VERSION 5.8 ;
BUSBITCHARS "[]" ;
DIVIDERCHAR "/" ;
UNITS
    DATABASE MICRONS 1000 ;
END UNITS

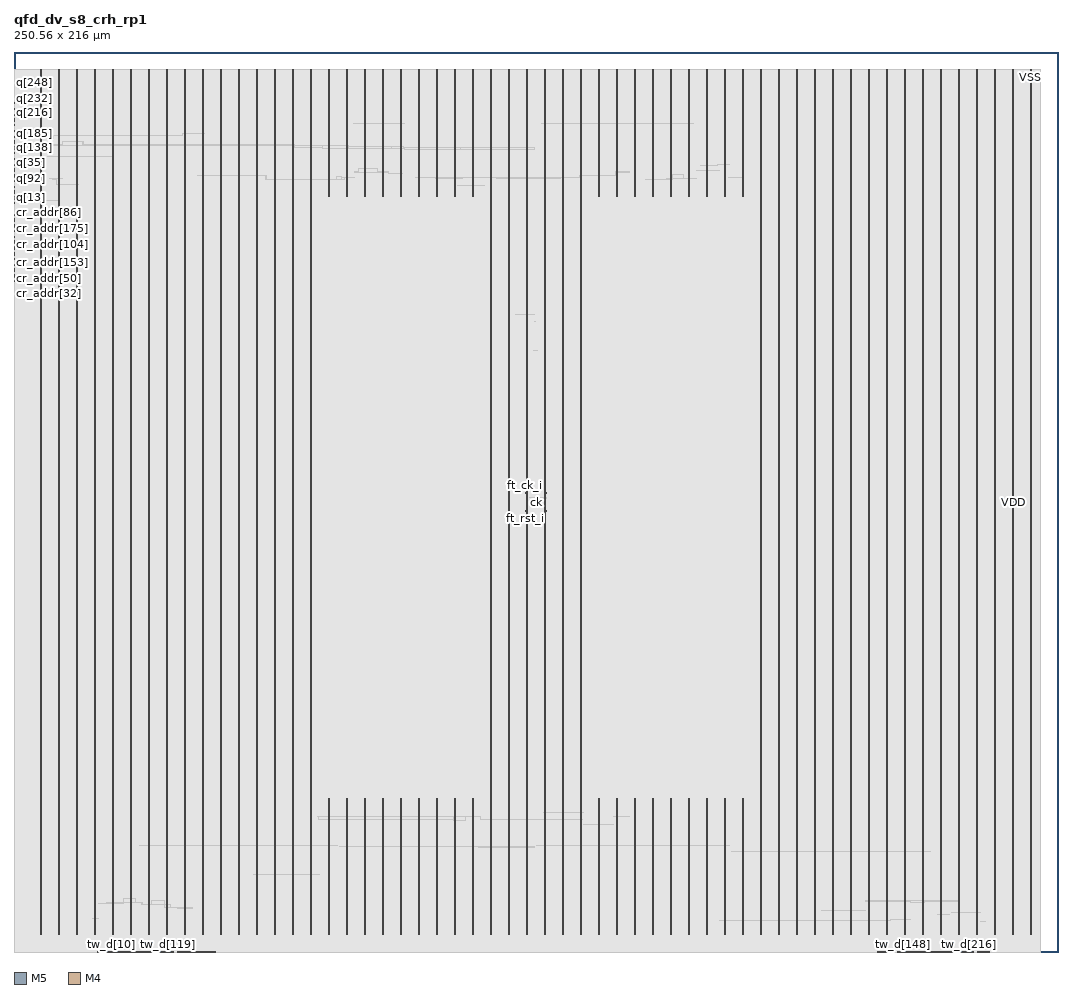
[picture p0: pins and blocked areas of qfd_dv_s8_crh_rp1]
MACRO qfd_dv_s8_crh_rp1
  FOREIGN qfd_dv_s8_crh_rp1 0 0 ;
  CLASS BLOCK ;
  SIZE 250.56 BY 216 ;
  PIN ck
    DIRECTION INPUT ;
    USE SIGNAL ;
    PORT
      LAYER M5 ;
        RECT  125.28 107.808 125.304 108.192 ;
    END
  END ck
  PIN cr_addr[0]
    DIRECTION INPUT ;
    USE SIGNAL ;
    PORT
      LAYER M4 ;
        RECT  0 166.032 0.084 166.056 ;
    END
  END cr_addr[0]
  PIN cr_addr[100]
    DIRECTION INPUT ;
    USE SIGNAL ;
    PORT
      LAYER M4 ;
        RECT  0 169.488 0.084 169.512 ;
    END
  END cr_addr[100]
  PIN cr_addr[101]
    DIRECTION INPUT ;
    USE SIGNAL ;
    PORT
      LAYER M4 ;
        RECT  0 169.584 0.084 169.608 ;
    END
  END cr_addr[101]
  PIN cr_addr[102]
    DIRECTION INPUT ;
    USE SIGNAL ;
    PORT
      LAYER M4 ;
        RECT  0 169.68 0.084 169.704 ;
    END
  END cr_addr[102]
  PIN cr_addr[103]
    DIRECTION INPUT ;
    USE SIGNAL ;
    PORT
      LAYER M4 ;
        RECT  0 169.776 0.084 169.8 ;
    END
  END cr_addr[103]
  PIN cr_addr[104]
    DIRECTION INPUT ;
    USE SIGNAL ;
    PORT
      LAYER M4 ;
        RECT  0 169.872 0.084 169.896 ;
    END
  END cr_addr[104]
  PIN cr_addr[105]
    DIRECTION INPUT ;
    USE SIGNAL ;
    PORT
      LAYER M4 ;
        RECT  0 169.968 0.084 169.992 ;
    END
  END cr_addr[105]
  PIN cr_addr[106]
    DIRECTION INPUT ;
    USE SIGNAL ;
    PORT
      LAYER M4 ;
        RECT  0 170.064 0.084 170.088 ;
    END
  END cr_addr[106]
  PIN cr_addr[107]
    DIRECTION INPUT ;
    USE SIGNAL ;
    PORT
      LAYER M4 ;
        RECT  0 170.16 0.084 170.184 ;
    END
  END cr_addr[107]
  PIN cr_addr[108]
    DIRECTION INPUT ;
    USE SIGNAL ;
    PORT
      LAYER M4 ;
        RECT  0 170.256 0.084 170.28 ;
    END
  END cr_addr[108]
  PIN cr_addr[109]
    DIRECTION INPUT ;
    USE SIGNAL ;
    PORT
      LAYER M4 ;
        RECT  0 170.352 0.084 170.376 ;
    END
  END cr_addr[109]
  PIN cr_addr[10]
    DIRECTION INPUT ;
    USE SIGNAL ;
    PORT
      LAYER M4 ;
        RECT  0 166.992 0.084 167.016 ;
    END
  END cr_addr[10]
  PIN cr_addr[110]
    DIRECTION INPUT ;
    USE SIGNAL ;
    PORT
      LAYER M4 ;
        RECT  0 170.448 0.084 170.472 ;
    END
  END cr_addr[110]
  PIN cr_addr[111]
    DIRECTION INPUT ;
    USE SIGNAL ;
    PORT
      LAYER M4 ;
        RECT  0 170.544 0.084 170.568 ;
    END
  END cr_addr[111]
  PIN cr_addr[112]
    DIRECTION INPUT ;
    USE SIGNAL ;
    PORT
      LAYER M4 ;
        RECT  0 170.64 0.084 170.664 ;
    END
  END cr_addr[112]
  PIN cr_addr[113]
    DIRECTION INPUT ;
    USE SIGNAL ;
    PORT
      LAYER M4 ;
        RECT  0 170.736 0.084 170.76 ;
    END
  END cr_addr[113]
  PIN cr_addr[114]
    DIRECTION INPUT ;
    USE SIGNAL ;
    PORT
      LAYER M4 ;
        RECT  0 170.832 0.084 170.856 ;
    END
  END cr_addr[114]
  PIN cr_addr[115]
    DIRECTION INPUT ;
    USE SIGNAL ;
    PORT
      LAYER M4 ;
        RECT  0 170.928 0.084 170.952 ;
    END
  END cr_addr[115]
  PIN cr_addr[116]
    DIRECTION INPUT ;
    USE SIGNAL ;
    PORT
      LAYER M4 ;
        RECT  0 171.024 0.084 171.048 ;
    END
  END cr_addr[116]
  PIN cr_addr[117]
    DIRECTION INPUT ;
    USE SIGNAL ;
    PORT
      LAYER M4 ;
        RECT  0 171.12 0.084 171.144 ;
    END
  END cr_addr[117]
  PIN cr_addr[118]
    DIRECTION INPUT ;
    USE SIGNAL ;
    PORT
      LAYER M4 ;
        RECT  0 171.216 0.084 171.24 ;
    END
  END cr_addr[118]
  PIN cr_addr[119]
    DIRECTION INPUT ;
    USE SIGNAL ;
    PORT
      LAYER M4 ;
        RECT  0 171.312 0.084 171.336 ;
    END
  END cr_addr[119]
  PIN cr_addr[11]
    DIRECTION INPUT ;
    USE SIGNAL ;
    PORT
      LAYER M4 ;
        RECT  0 167.088 0.084 167.112 ;
    END
  END cr_addr[11]
  PIN cr_addr[120]
    DIRECTION INPUT ;
    USE SIGNAL ;
    PORT
      LAYER M4 ;
        RECT  0 171.408 0.084 171.432 ;
    END
  END cr_addr[120]
  PIN cr_addr[121]
    DIRECTION INPUT ;
    USE SIGNAL ;
    PORT
      LAYER M4 ;
        RECT  0 171.504 0.084 171.528 ;
    END
  END cr_addr[121]
  PIN cr_addr[122]
    DIRECTION INPUT ;
    USE SIGNAL ;
    PORT
      LAYER M4 ;
        RECT  0 171.6 0.084 171.624 ;
    END
  END cr_addr[122]
  PIN cr_addr[123]
    DIRECTION INPUT ;
    USE SIGNAL ;
    PORT
      LAYER M4 ;
        RECT  0 171.696 0.084 171.72 ;
    END
  END cr_addr[123]
  PIN cr_addr[124]
    DIRECTION INPUT ;
    USE SIGNAL ;
    PORT
      LAYER M4 ;
        RECT  0 171.792 0.084 171.816 ;
    END
  END cr_addr[124]
  PIN cr_addr[125]
    DIRECTION INPUT ;
    USE SIGNAL ;
    PORT
      LAYER M4 ;
        RECT  0 171.888 0.084 171.912 ;
    END
  END cr_addr[125]
  PIN cr_addr[126]
    DIRECTION INPUT ;
    USE SIGNAL ;
    PORT
      LAYER M4 ;
        RECT  0 171.984 0.084 172.008 ;
    END
  END cr_addr[126]
  PIN cr_addr[127]
    DIRECTION INPUT ;
    USE SIGNAL ;
    PORT
      LAYER M4 ;
        RECT  0 172.08 0.084 172.104 ;
    END
  END cr_addr[127]
  PIN cr_addr[128]
    DIRECTION INPUT ;
    USE SIGNAL ;
    PORT
      LAYER M4 ;
        RECT  0 162.96 0.084 162.984 ;
    END
  END cr_addr[128]
  PIN cr_addr[129]
    DIRECTION INPUT ;
    USE SIGNAL ;
    PORT
      LAYER M4 ;
        RECT  0 163.056 0.084 163.08 ;
    END
  END cr_addr[129]
  PIN cr_addr[12]
    DIRECTION INPUT ;
    USE SIGNAL ;
    PORT
      LAYER M4 ;
        RECT  0 167.184 0.084 167.208 ;
    END
  END cr_addr[12]
  PIN cr_addr[130]
    DIRECTION INPUT ;
    USE SIGNAL ;
    PORT
      LAYER M4 ;
        RECT  0 163.152 0.084 163.176 ;
    END
  END cr_addr[130]
  PIN cr_addr[131]
    DIRECTION INPUT ;
    USE SIGNAL ;
    PORT
      LAYER M4 ;
        RECT  0 163.248 0.084 163.272 ;
    END
  END cr_addr[131]
  PIN cr_addr[132]
    DIRECTION INPUT ;
    USE SIGNAL ;
    PORT
      LAYER M4 ;
        RECT  0 163.344 0.084 163.368 ;
    END
  END cr_addr[132]
  PIN cr_addr[133]
    DIRECTION INPUT ;
    USE SIGNAL ;
    PORT
      LAYER M4 ;
        RECT  0 163.44 0.084 163.464 ;
    END
  END cr_addr[133]
  PIN cr_addr[134]
    DIRECTION INPUT ;
    USE SIGNAL ;
    PORT
      LAYER M4 ;
        RECT  0 163.536 0.084 163.56 ;
    END
  END cr_addr[134]
  PIN cr_addr[135]
    DIRECTION INPUT ;
    USE SIGNAL ;
    PORT
      LAYER M4 ;
        RECT  0 163.632 0.084 163.656 ;
    END
  END cr_addr[135]
  PIN cr_addr[136]
    DIRECTION INPUT ;
    USE SIGNAL ;
    PORT
      LAYER M4 ;
        RECT  0 163.728 0.084 163.752 ;
    END
  END cr_addr[136]
  PIN cr_addr[137]
    DIRECTION INPUT ;
    USE SIGNAL ;
    PORT
      LAYER M4 ;
        RECT  0 163.824 0.084 163.848 ;
    END
  END cr_addr[137]
  PIN cr_addr[138]
    DIRECTION INPUT ;
    USE SIGNAL ;
    PORT
      LAYER M4 ;
        RECT  0 163.92 0.084 163.944 ;
    END
  END cr_addr[138]
  PIN cr_addr[139]
    DIRECTION INPUT ;
    USE SIGNAL ;
    PORT
      LAYER M4 ;
        RECT  0 164.016 0.084 164.04 ;
    END
  END cr_addr[139]
  PIN cr_addr[13]
    DIRECTION INPUT ;
    USE SIGNAL ;
    PORT
      LAYER M4 ;
        RECT  0 167.28 0.084 167.304 ;
    END
  END cr_addr[13]
  PIN cr_addr[140]
    DIRECTION INPUT ;
    USE SIGNAL ;
    PORT
      LAYER M4 ;
        RECT  0 164.112 0.084 164.136 ;
    END
  END cr_addr[140]
  PIN cr_addr[141]
    DIRECTION INPUT ;
    USE SIGNAL ;
    PORT
      LAYER M4 ;
        RECT  0 164.208 0.084 164.232 ;
    END
  END cr_addr[141]
  PIN cr_addr[142]
    DIRECTION INPUT ;
    USE SIGNAL ;
    PORT
      LAYER M4 ;
        RECT  0 164.304 0.084 164.328 ;
    END
  END cr_addr[142]
  PIN cr_addr[143]
    DIRECTION INPUT ;
    USE SIGNAL ;
    PORT
      LAYER M4 ;
        RECT  0 164.4 0.084 164.424 ;
    END
  END cr_addr[143]
  PIN cr_addr[144]
    DIRECTION INPUT ;
    USE SIGNAL ;
    PORT
      LAYER M4 ;
        RECT  0 164.496 0.084 164.52 ;
    END
  END cr_addr[144]
  PIN cr_addr[145]
    DIRECTION INPUT ;
    USE SIGNAL ;
    PORT
      LAYER M4 ;
        RECT  0 164.592 0.084 164.616 ;
    END
  END cr_addr[145]
  PIN cr_addr[146]
    DIRECTION INPUT ;
    USE SIGNAL ;
    PORT
      LAYER M4 ;
        RECT  0 164.688 0.084 164.712 ;
    END
  END cr_addr[146]
  PIN cr_addr[147]
    DIRECTION INPUT ;
    USE SIGNAL ;
    PORT
      LAYER M4 ;
        RECT  0 164.784 0.084 164.808 ;
    END
  END cr_addr[147]
  PIN cr_addr[148]
    DIRECTION INPUT ;
    USE SIGNAL ;
    PORT
      LAYER M4 ;
        RECT  0 164.88 0.084 164.904 ;
    END
  END cr_addr[148]
  PIN cr_addr[149]
    DIRECTION INPUT ;
    USE SIGNAL ;
    PORT
      LAYER M4 ;
        RECT  0 164.976 0.084 165 ;
    END
  END cr_addr[149]
  PIN cr_addr[14]
    DIRECTION INPUT ;
    USE SIGNAL ;
    PORT
      LAYER M4 ;
        RECT  0 167.376 0.084 167.4 ;
    END
  END cr_addr[14]
  PIN cr_addr[150]
    DIRECTION INPUT ;
    USE SIGNAL ;
    PORT
      LAYER M4 ;
        RECT  0 165.072 0.084 165.096 ;
    END
  END cr_addr[150]
  PIN cr_addr[151]
    DIRECTION INPUT ;
    USE SIGNAL ;
    PORT
      LAYER M4 ;
        RECT  0 165.168 0.084 165.192 ;
    END
  END cr_addr[151]
  PIN cr_addr[152]
    DIRECTION INPUT ;
    USE SIGNAL ;
    PORT
      LAYER M4 ;
        RECT  0 165.264 0.084 165.288 ;
    END
  END cr_addr[152]
  PIN cr_addr[153]
    DIRECTION INPUT ;
    USE SIGNAL ;
    PORT
      LAYER M4 ;
        RECT  0 165.36 0.084 165.384 ;
    END
  END cr_addr[153]
  PIN cr_addr[154]
    DIRECTION INPUT ;
    USE SIGNAL ;
    PORT
      LAYER M4 ;
        RECT  0 165.456 0.084 165.48 ;
    END
  END cr_addr[154]
  PIN cr_addr[155]
    DIRECTION INPUT ;
    USE SIGNAL ;
    PORT
      LAYER M4 ;
        RECT  0 165.552 0.084 165.576 ;
    END
  END cr_addr[155]
  PIN cr_addr[156]
    DIRECTION INPUT ;
    USE SIGNAL ;
    PORT
      LAYER M4 ;
        RECT  0 165.648 0.084 165.672 ;
    END
  END cr_addr[156]
  PIN cr_addr[157]
    DIRECTION INPUT ;
    USE SIGNAL ;
    PORT
      LAYER M4 ;
        RECT  0 165.744 0.084 165.768 ;
    END
  END cr_addr[157]
  PIN cr_addr[158]
    DIRECTION INPUT ;
    USE SIGNAL ;
    PORT
      LAYER M4 ;
        RECT  0 165.84 0.084 165.864 ;
    END
  END cr_addr[158]
  PIN cr_addr[159]
    DIRECTION INPUT ;
    USE SIGNAL ;
    PORT
      LAYER M4 ;
        RECT  0 165.936 0.084 165.96 ;
    END
  END cr_addr[159]
  PIN cr_addr[15]
    DIRECTION INPUT ;
    USE SIGNAL ;
    PORT
      LAYER M4 ;
        RECT  0 167.472 0.084 167.496 ;
    END
  END cr_addr[15]
  PIN cr_addr[160]
    DIRECTION INPUT ;
    USE SIGNAL ;
    PORT
      LAYER M4 ;
        RECT  0 172.176 0.084 172.2 ;
    END
  END cr_addr[160]
  PIN cr_addr[161]
    DIRECTION INPUT ;
    USE SIGNAL ;
    PORT
      LAYER M4 ;
        RECT  0 172.272 0.084 172.296 ;
    END
  END cr_addr[161]
  PIN cr_addr[162]
    DIRECTION INPUT ;
    USE SIGNAL ;
    PORT
      LAYER M4 ;
        RECT  0 172.368 0.084 172.392 ;
    END
  END cr_addr[162]
  PIN cr_addr[163]
    DIRECTION INPUT ;
    USE SIGNAL ;
    PORT
      LAYER M4 ;
        RECT  0 172.464 0.084 172.488 ;
    END
  END cr_addr[163]
  PIN cr_addr[164]
    DIRECTION INPUT ;
    USE SIGNAL ;
    PORT
      LAYER M4 ;
        RECT  0 172.56 0.084 172.584 ;
    END
  END cr_addr[164]
  PIN cr_addr[165]
    DIRECTION INPUT ;
    USE SIGNAL ;
    PORT
      LAYER M4 ;
        RECT  0 172.656 0.084 172.68 ;
    END
  END cr_addr[165]
  PIN cr_addr[166]
    DIRECTION INPUT ;
    USE SIGNAL ;
    PORT
      LAYER M4 ;
        RECT  0 172.752 0.084 172.776 ;
    END
  END cr_addr[166]
  PIN cr_addr[167]
    DIRECTION INPUT ;
    USE SIGNAL ;
    PORT
      LAYER M4 ;
        RECT  0 172.848 0.084 172.872 ;
    END
  END cr_addr[167]
  PIN cr_addr[168]
    DIRECTION INPUT ;
    USE SIGNAL ;
    PORT
      LAYER M4 ;
        RECT  0 172.944 0.084 172.968 ;
    END
  END cr_addr[168]
  PIN cr_addr[169]
    DIRECTION INPUT ;
    USE SIGNAL ;
    PORT
      LAYER M4 ;
        RECT  0 173.04 0.084 173.064 ;
    END
  END cr_addr[169]
  PIN cr_addr[16]
    DIRECTION INPUT ;
    USE SIGNAL ;
    PORT
      LAYER M4 ;
        RECT  0 167.568 0.084 167.592 ;
    END
  END cr_addr[16]
  PIN cr_addr[170]
    DIRECTION INPUT ;
    USE SIGNAL ;
    PORT
      LAYER M4 ;
        RECT  0 173.136 0.084 173.16 ;
    END
  END cr_addr[170]
  PIN cr_addr[171]
    DIRECTION INPUT ;
    USE SIGNAL ;
    PORT
      LAYER M4 ;
        RECT  0 173.232 0.084 173.256 ;
    END
  END cr_addr[171]
  PIN cr_addr[172]
    DIRECTION INPUT ;
    USE SIGNAL ;
    PORT
      LAYER M4 ;
        RECT  0 173.328 0.084 173.352 ;
    END
  END cr_addr[172]
  PIN cr_addr[173]
    DIRECTION INPUT ;
    USE SIGNAL ;
    PORT
      LAYER M4 ;
        RECT  0 173.424 0.084 173.448 ;
    END
  END cr_addr[173]
  PIN cr_addr[174]
    DIRECTION INPUT ;
    USE SIGNAL ;
    PORT
      LAYER M4 ;
        RECT  0 173.52 0.084 173.544 ;
    END
  END cr_addr[174]
  PIN cr_addr[175]
    DIRECTION INPUT ;
    USE SIGNAL ;
    PORT
      LAYER M4 ;
        RECT  0 173.616 0.084 173.64 ;
    END
  END cr_addr[175]
  PIN cr_addr[176]
    DIRECTION INPUT ;
    USE SIGNAL ;
    PORT
      LAYER M4 ;
        RECT  0 173.712 0.084 173.736 ;
    END
  END cr_addr[176]
  PIN cr_addr[177]
    DIRECTION INPUT ;
    USE SIGNAL ;
    PORT
      LAYER M4 ;
        RECT  0 173.808 0.084 173.832 ;
    END
  END cr_addr[177]
  PIN cr_addr[178]
    DIRECTION INPUT ;
    USE SIGNAL ;
    PORT
      LAYER M4 ;
        RECT  0 173.904 0.084 173.928 ;
    END
  END cr_addr[178]
  PIN cr_addr[179]
    DIRECTION INPUT ;
    USE SIGNAL ;
    PORT
      LAYER M4 ;
        RECT  0 174 0.084 174.024 ;
    END
  END cr_addr[179]
  PIN cr_addr[17]
    DIRECTION INPUT ;
    USE SIGNAL ;
    PORT
      LAYER M4 ;
        RECT  0 167.664 0.084 167.688 ;
    END
  END cr_addr[17]
  PIN cr_addr[180]
    DIRECTION INPUT ;
    USE SIGNAL ;
    PORT
      LAYER M4 ;
        RECT  0 174.096 0.084 174.12 ;
    END
  END cr_addr[180]
  PIN cr_addr[181]
    DIRECTION INPUT ;
    USE SIGNAL ;
    PORT
      LAYER M4 ;
        RECT  0 174.192 0.084 174.216 ;
    END
  END cr_addr[181]
  PIN cr_addr[182]
    DIRECTION INPUT ;
    USE SIGNAL ;
    PORT
      LAYER M4 ;
        RECT  0 174.288 0.084 174.312 ;
    END
  END cr_addr[182]
  PIN cr_addr[183]
    DIRECTION INPUT ;
    USE SIGNAL ;
    PORT
      LAYER M4 ;
        RECT  0 174.384 0.084 174.408 ;
    END
  END cr_addr[183]
  PIN cr_addr[184]
    DIRECTION INPUT ;
    USE SIGNAL ;
    PORT
      LAYER M4 ;
        RECT  0 174.48 0.084 174.504 ;
    END
  END cr_addr[184]
  PIN cr_addr[185]
    DIRECTION INPUT ;
    USE SIGNAL ;
    PORT
      LAYER M4 ;
        RECT  0 174.576 0.084 174.6 ;
    END
  END cr_addr[185]
  PIN cr_addr[186]
    DIRECTION INPUT ;
    USE SIGNAL ;
    PORT
      LAYER M4 ;
        RECT  0 174.672 0.084 174.696 ;
    END
  END cr_addr[186]
  PIN cr_addr[187]
    DIRECTION INPUT ;
    USE SIGNAL ;
    PORT
      LAYER M4 ;
        RECT  0 174.768 0.084 174.792 ;
    END
  END cr_addr[187]
  PIN cr_addr[188]
    DIRECTION INPUT ;
    USE SIGNAL ;
    PORT
      LAYER M4 ;
        RECT  0 174.864 0.084 174.888 ;
    END
  END cr_addr[188]
  PIN cr_addr[189]
    DIRECTION INPUT ;
    USE SIGNAL ;
    PORT
      LAYER M4 ;
        RECT  0 174.96 0.084 174.984 ;
    END
  END cr_addr[189]
  PIN cr_addr[18]
    DIRECTION INPUT ;
    USE SIGNAL ;
    PORT
      LAYER M4 ;
        RECT  0 167.76 0.084 167.784 ;
    END
  END cr_addr[18]
  PIN cr_addr[190]
    DIRECTION INPUT ;
    USE SIGNAL ;
    PORT
      LAYER M4 ;
        RECT  0 175.056 0.084 175.08 ;
    END
  END cr_addr[190]
  PIN cr_addr[191]
    DIRECTION INPUT ;
    USE SIGNAL ;
    PORT
      LAYER M4 ;
        RECT  0 175.152 0.084 175.176 ;
    END
  END cr_addr[191]
  PIN cr_addr[19]
    DIRECTION INPUT ;
    USE SIGNAL ;
    PORT
      LAYER M4 ;
        RECT  0 167.856 0.084 167.88 ;
    END
  END cr_addr[19]
  PIN cr_addr[1]
    DIRECTION INPUT ;
    USE SIGNAL ;
    PORT
      LAYER M4 ;
        RECT  0 166.128 0.084 166.152 ;
    END
  END cr_addr[1]
  PIN cr_addr[20]
    DIRECTION INPUT ;
    USE SIGNAL ;
    PORT
      LAYER M4 ;
        RECT  0 167.952 0.084 167.976 ;
    END
  END cr_addr[20]
  PIN cr_addr[21]
    DIRECTION INPUT ;
    USE SIGNAL ;
    PORT
      LAYER M4 ;
        RECT  0 168.048 0.084 168.072 ;
    END
  END cr_addr[21]
  PIN cr_addr[22]
    DIRECTION INPUT ;
    USE SIGNAL ;
    PORT
      LAYER M4 ;
        RECT  0 168.144 0.084 168.168 ;
    END
  END cr_addr[22]
  PIN cr_addr[23]
    DIRECTION INPUT ;
    USE SIGNAL ;
    PORT
      LAYER M4 ;
        RECT  0 168.24 0.084 168.264 ;
    END
  END cr_addr[23]
  PIN cr_addr[24]
    DIRECTION INPUT ;
    USE SIGNAL ;
    PORT
      LAYER M4 ;
        RECT  0 168.336 0.084 168.36 ;
    END
  END cr_addr[24]
  PIN cr_addr[25]
    DIRECTION INPUT ;
    USE SIGNAL ;
    PORT
      LAYER M4 ;
        RECT  0 168.432 0.084 168.456 ;
    END
  END cr_addr[25]
  PIN cr_addr[26]
    DIRECTION INPUT ;
    USE SIGNAL ;
    PORT
      LAYER M4 ;
        RECT  0 168.528 0.084 168.552 ;
    END
  END cr_addr[26]
  PIN cr_addr[27]
    DIRECTION INPUT ;
    USE SIGNAL ;
    PORT
      LAYER M4 ;
        RECT  0 168.624 0.084 168.648 ;
    END
  END cr_addr[27]
  PIN cr_addr[28]
    DIRECTION INPUT ;
    USE SIGNAL ;
    PORT
      LAYER M4 ;
        RECT  0 168.72 0.084 168.744 ;
    END
  END cr_addr[28]
  PIN cr_addr[29]
    DIRECTION INPUT ;
    USE SIGNAL ;
    PORT
      LAYER M4 ;
        RECT  0 168.816 0.084 168.84 ;
    END
  END cr_addr[29]
  PIN cr_addr[2]
    DIRECTION INPUT ;
    USE SIGNAL ;
    PORT
      LAYER M4 ;
        RECT  0 166.224 0.084 166.248 ;
    END
  END cr_addr[2]
  PIN cr_addr[30]
    DIRECTION INPUT ;
    USE SIGNAL ;
    PORT
      LAYER M4 ;
        RECT  0 168.912 0.084 168.936 ;
    END
  END cr_addr[30]
  PIN cr_addr[31]
    DIRECTION INPUT ;
    USE SIGNAL ;
    PORT
      LAYER M4 ;
        RECT  0 169.008 0.084 169.032 ;
    END
  END cr_addr[31]
  PIN cr_addr[32]
    DIRECTION INPUT ;
    USE SIGNAL ;
    PORT
      LAYER M4 ;
        RECT  0 159.888 0.084 159.912 ;
    END
  END cr_addr[32]
  PIN cr_addr[33]
    DIRECTION INPUT ;
    USE SIGNAL ;
    PORT
      LAYER M4 ;
        RECT  0 159.984 0.084 160.008 ;
    END
  END cr_addr[33]
  PIN cr_addr[34]
    DIRECTION INPUT ;
    USE SIGNAL ;
    PORT
      LAYER M4 ;
        RECT  0 160.08 0.084 160.104 ;
    END
  END cr_addr[34]
  PIN cr_addr[35]
    DIRECTION INPUT ;
    USE SIGNAL ;
    PORT
      LAYER M4 ;
        RECT  0 160.176 0.084 160.2 ;
    END
  END cr_addr[35]
  PIN cr_addr[36]
    DIRECTION INPUT ;
    USE SIGNAL ;
    PORT
      LAYER M4 ;
        RECT  0 160.272 0.084 160.296 ;
    END
  END cr_addr[36]
  PIN cr_addr[37]
    DIRECTION INPUT ;
    USE SIGNAL ;
    PORT
      LAYER M4 ;
        RECT  0 160.368 0.084 160.392 ;
    END
  END cr_addr[37]
  PIN cr_addr[38]
    DIRECTION INPUT ;
    USE SIGNAL ;
    PORT
      LAYER M4 ;
        RECT  0 160.464 0.084 160.488 ;
    END
  END cr_addr[38]
  PIN cr_addr[39]
    DIRECTION INPUT ;
    USE SIGNAL ;
    PORT
      LAYER M4 ;
        RECT  0 160.56 0.084 160.584 ;
    END
  END cr_addr[39]
  PIN cr_addr[3]
    DIRECTION INPUT ;
    USE SIGNAL ;
    PORT
      LAYER M4 ;
        RECT  0 166.32 0.084 166.344 ;
    END
  END cr_addr[3]
  PIN cr_addr[40]
    DIRECTION INPUT ;
    USE SIGNAL ;
    PORT
      LAYER M4 ;
        RECT  0 160.656 0.084 160.68 ;
    END
  END cr_addr[40]
  PIN cr_addr[41]
    DIRECTION INPUT ;
    USE SIGNAL ;
    PORT
      LAYER M4 ;
        RECT  0 160.752 0.084 160.776 ;
    END
  END cr_addr[41]
  PIN cr_addr[42]
    DIRECTION INPUT ;
    USE SIGNAL ;
    PORT
      LAYER M4 ;
        RECT  0 160.848 0.084 160.872 ;
    END
  END cr_addr[42]
  PIN cr_addr[43]
    DIRECTION INPUT ;
    USE SIGNAL ;
    PORT
      LAYER M4 ;
        RECT  0 160.944 0.084 160.968 ;
    END
  END cr_addr[43]
  PIN cr_addr[44]
    DIRECTION INPUT ;
    USE SIGNAL ;
    PORT
      LAYER M4 ;
        RECT  0 161.04 0.084 161.064 ;
    END
  END cr_addr[44]
  PIN cr_addr[45]
    DIRECTION INPUT ;
    USE SIGNAL ;
    PORT
      LAYER M4 ;
        RECT  0 161.136 0.084 161.16 ;
    END
  END cr_addr[45]
  PIN cr_addr[46]
    DIRECTION INPUT ;
    USE SIGNAL ;
    PORT
      LAYER M4 ;
        RECT  0 161.232 0.084 161.256 ;
    END
  END cr_addr[46]
  PIN cr_addr[47]
    DIRECTION INPUT ;
    USE SIGNAL ;
    PORT
      LAYER M4 ;
        RECT  0 161.328 0.084 161.352 ;
    END
  END cr_addr[47]
  PIN cr_addr[48]
    DIRECTION INPUT ;
    USE SIGNAL ;
    PORT
      LAYER M4 ;
        RECT  0 161.424 0.084 161.448 ;
    END
  END cr_addr[48]
  PIN cr_addr[49]
    DIRECTION INPUT ;
    USE SIGNAL ;
    PORT
      LAYER M4 ;
        RECT  0 161.52 0.084 161.544 ;
    END
  END cr_addr[49]
  PIN cr_addr[4]
    DIRECTION INPUT ;
    USE SIGNAL ;
    PORT
      LAYER M4 ;
        RECT  0 166.416 0.084 166.44 ;
    END
  END cr_addr[4]
  PIN cr_addr[50]
    DIRECTION INPUT ;
    USE SIGNAL ;
    PORT
      LAYER M4 ;
        RECT  0 161.616 0.084 161.64 ;
    END
  END cr_addr[50]
  PIN cr_addr[51]
    DIRECTION INPUT ;
    USE SIGNAL ;
    PORT
      LAYER M4 ;
        RECT  0 161.712 0.084 161.736 ;
    END
  END cr_addr[51]
  PIN cr_addr[52]
    DIRECTION INPUT ;
    USE SIGNAL ;
    PORT
      LAYER M4 ;
        RECT  0 161.808 0.084 161.832 ;
    END
  END cr_addr[52]
  PIN cr_addr[53]
    DIRECTION INPUT ;
    USE SIGNAL ;
    PORT
      LAYER M4 ;
        RECT  0 161.904 0.084 161.928 ;
    END
  END cr_addr[53]
  PIN cr_addr[54]
    DIRECTION INPUT ;
    USE SIGNAL ;
    PORT
      LAYER M4 ;
        RECT  0 162 0.084 162.024 ;
    END
  END cr_addr[54]
  PIN cr_addr[55]
    DIRECTION INPUT ;
    USE SIGNAL ;
    PORT
      LAYER M4 ;
        RECT  0 162.096 0.084 162.12 ;
    END
  END cr_addr[55]
  PIN cr_addr[56]
    DIRECTION INPUT ;
    USE SIGNAL ;
    PORT
      LAYER M4 ;
        RECT  0 162.192 0.084 162.216 ;
    END
  END cr_addr[56]
  PIN cr_addr[57]
    DIRECTION INPUT ;
    USE SIGNAL ;
    PORT
      LAYER M4 ;
        RECT  0 162.288 0.084 162.312 ;
    END
  END cr_addr[57]
  PIN cr_addr[58]
    DIRECTION INPUT ;
    USE SIGNAL ;
    PORT
      LAYER M4 ;
        RECT  0 162.384 0.084 162.408 ;
    END
  END cr_addr[58]
  PIN cr_addr[59]
    DIRECTION INPUT ;
    USE SIGNAL ;
    PORT
      LAYER M4 ;
        RECT  0 162.48 0.084 162.504 ;
    END
  END cr_addr[59]
  PIN cr_addr[5]
    DIRECTION INPUT ;
    USE SIGNAL ;
    PORT
      LAYER M4 ;
        RECT  0 166.512 0.084 166.536 ;
    END
  END cr_addr[5]
  PIN cr_addr[60]
    DIRECTION INPUT ;
    USE SIGNAL ;
    PORT
      LAYER M4 ;
        RECT  0 162.576 0.084 162.6 ;
    END
  END cr_addr[60]
  PIN cr_addr[61]
    DIRECTION INPUT ;
    USE SIGNAL ;
    PORT
      LAYER M4 ;
        RECT  0 162.672 0.084 162.696 ;
    END
  END cr_addr[61]
  PIN cr_addr[62]
    DIRECTION INPUT ;
    USE SIGNAL ;
    PORT
      LAYER M4 ;
        RECT  0 162.768 0.084 162.792 ;
    END
  END cr_addr[62]
  PIN cr_addr[63]
    DIRECTION INPUT ;
    USE SIGNAL ;
    PORT
      LAYER M4 ;
        RECT  0 162.864 0.084 162.888 ;
    END
  END cr_addr[63]
  PIN cr_addr[64]
    DIRECTION INPUT ;
    USE SIGNAL ;
    PORT
      LAYER M4 ;
        RECT  0 175.248 0.084 175.272 ;
    END
  END cr_addr[64]
  PIN cr_addr[65]
    DIRECTION INPUT ;
    USE SIGNAL ;
    PORT
      LAYER M4 ;
        RECT  0 175.344 0.084 175.368 ;
    END
  END cr_addr[65]
  PIN cr_addr[66]
    DIRECTION INPUT ;
    USE SIGNAL ;
    PORT
      LAYER M4 ;
        RECT  0 175.44 0.084 175.464 ;
    END
  END cr_addr[66]
  PIN cr_addr[67]
    DIRECTION INPUT ;
    USE SIGNAL ;
    PORT
      LAYER M4 ;
        RECT  0 175.536 0.084 175.56 ;
    END
  END cr_addr[67]
  PIN cr_addr[68]
    DIRECTION INPUT ;
    USE SIGNAL ;
    PORT
      LAYER M4 ;
        RECT  0 175.632 0.084 175.656 ;
    END
  END cr_addr[68]
  PIN cr_addr[69]
    DIRECTION INPUT ;
    USE SIGNAL ;
    PORT
      LAYER M4 ;
        RECT  0 175.728 0.084 175.752 ;
    END
  END cr_addr[69]
  PIN cr_addr[6]
    DIRECTION INPUT ;
    USE SIGNAL ;
    PORT
      LAYER M4 ;
        RECT  0 166.608 0.084 166.632 ;
    END
  END cr_addr[6]
  PIN cr_addr[70]
    DIRECTION INPUT ;
    USE SIGNAL ;
    PORT
      LAYER M4 ;
        RECT  0 175.824 0.084 175.848 ;
    END
  END cr_addr[70]
  PIN cr_addr[71]
    DIRECTION INPUT ;
    USE SIGNAL ;
    PORT
      LAYER M4 ;
        RECT  0 175.92 0.084 175.944 ;
    END
  END cr_addr[71]
  PIN cr_addr[72]
    DIRECTION INPUT ;
    USE SIGNAL ;
    PORT
      LAYER M4 ;
        RECT  0 176.016 0.084 176.04 ;
    END
  END cr_addr[72]
  PIN cr_addr[73]
    DIRECTION INPUT ;
    USE SIGNAL ;
    PORT
      LAYER M4 ;
        RECT  0 176.112 0.084 176.136 ;
    END
  END cr_addr[73]
  PIN cr_addr[74]
    DIRECTION INPUT ;
    USE SIGNAL ;
    PORT
      LAYER M4 ;
        RECT  0 176.208 0.084 176.232 ;
    END
  END cr_addr[74]
  PIN cr_addr[75]
    DIRECTION INPUT ;
    USE SIGNAL ;
    PORT
      LAYER M4 ;
        RECT  0 176.304 0.084 176.328 ;
    END
  END cr_addr[75]
  PIN cr_addr[76]
    DIRECTION INPUT ;
    USE SIGNAL ;
    PORT
      LAYER M4 ;
        RECT  0 176.4 0.084 176.424 ;
    END
  END cr_addr[76]
  PIN cr_addr[77]
    DIRECTION INPUT ;
    USE SIGNAL ;
    PORT
      LAYER M4 ;
        RECT  0 176.496 0.084 176.52 ;
    END
  END cr_addr[77]
  PIN cr_addr[78]
    DIRECTION INPUT ;
    USE SIGNAL ;
    PORT
      LAYER M4 ;
        RECT  0 176.592 0.084 176.616 ;
    END
  END cr_addr[78]
  PIN cr_addr[79]
    DIRECTION INPUT ;
    USE SIGNAL ;
    PORT
      LAYER M4 ;
        RECT  0 176.688 0.084 176.712 ;
    END
  END cr_addr[79]
  PIN cr_addr[7]
    DIRECTION INPUT ;
    USE SIGNAL ;
    PORT
      LAYER M4 ;
        RECT  0 166.704 0.084 166.728 ;
    END
  END cr_addr[7]
  PIN cr_addr[80]
    DIRECTION INPUT ;
    USE SIGNAL ;
    PORT
      LAYER M4 ;
        RECT  0 176.784 0.084 176.808 ;
    END
  END cr_addr[80]
  PIN cr_addr[81]
    DIRECTION INPUT ;
    USE SIGNAL ;
    PORT
      LAYER M4 ;
        RECT  0 176.88 0.084 176.904 ;
    END
  END cr_addr[81]
  PIN cr_addr[82]
    DIRECTION INPUT ;
    USE SIGNAL ;
    PORT
      LAYER M4 ;
        RECT  0 176.976 0.084 177 ;
    END
  END cr_addr[82]
  PIN cr_addr[83]
    DIRECTION INPUT ;
    USE SIGNAL ;
    PORT
      LAYER M4 ;
        RECT  0 177.072 0.084 177.096 ;
    END
  END cr_addr[83]
  PIN cr_addr[84]
    DIRECTION INPUT ;
    USE SIGNAL ;
    PORT
      LAYER M4 ;
        RECT  0 177.168 0.084 177.192 ;
    END
  END cr_addr[84]
  PIN cr_addr[85]
    DIRECTION INPUT ;
    USE SIGNAL ;
    PORT
      LAYER M4 ;
        RECT  0 177.264 0.084 177.288 ;
    END
  END cr_addr[85]
  PIN cr_addr[86]
    DIRECTION INPUT ;
    USE SIGNAL ;
    PORT
      LAYER M4 ;
        RECT  0 177.36 0.084 177.384 ;
    END
  END cr_addr[86]
  PIN cr_addr[87]
    DIRECTION INPUT ;
    USE SIGNAL ;
    PORT
      LAYER M4 ;
        RECT  0 177.456 0.084 177.48 ;
    END
  END cr_addr[87]
  PIN cr_addr[88]
    DIRECTION INPUT ;
    USE SIGNAL ;
    PORT
      LAYER M4 ;
        RECT  0 177.552 0.084 177.576 ;
    END
  END cr_addr[88]
  PIN cr_addr[89]
    DIRECTION INPUT ;
    USE SIGNAL ;
    PORT
      LAYER M4 ;
        RECT  0 177.648 0.084 177.672 ;
    END
  END cr_addr[89]
  PIN cr_addr[8]
    DIRECTION INPUT ;
    USE SIGNAL ;
    PORT
      LAYER M4 ;
        RECT  0 166.8 0.084 166.824 ;
    END
  END cr_addr[8]
  PIN cr_addr[90]
    DIRECTION INPUT ;
    USE SIGNAL ;
    PORT
      LAYER M4 ;
        RECT  0 177.744 0.084 177.768 ;
    END
  END cr_addr[90]
  PIN cr_addr[91]
    DIRECTION INPUT ;
    USE SIGNAL ;
    PORT
      LAYER M4 ;
        RECT  0 177.84 0.084 177.864 ;
    END
  END cr_addr[91]
  PIN cr_addr[92]
    DIRECTION INPUT ;
    USE SIGNAL ;
    PORT
      LAYER M4 ;
        RECT  0 177.936 0.084 177.96 ;
    END
  END cr_addr[92]
  PIN cr_addr[93]
    DIRECTION INPUT ;
    USE SIGNAL ;
    PORT
      LAYER M4 ;
        RECT  0 178.032 0.084 178.056 ;
    END
  END cr_addr[93]
  PIN cr_addr[94]
    DIRECTION INPUT ;
    USE SIGNAL ;
    PORT
      LAYER M4 ;
        RECT  0 178.128 0.084 178.152 ;
    END
  END cr_addr[94]
  PIN cr_addr[95]
    DIRECTION INPUT ;
    USE SIGNAL ;
    PORT
      LAYER M4 ;
        RECT  0 178.224 0.084 178.248 ;
    END
  END cr_addr[95]
  PIN cr_addr[96]
    DIRECTION INPUT ;
    USE SIGNAL ;
    PORT
      LAYER M4 ;
        RECT  0 169.104 0.084 169.128 ;
    END
  END cr_addr[96]
  PIN cr_addr[97]
    DIRECTION INPUT ;
    USE SIGNAL ;
    PORT
      LAYER M4 ;
        RECT  0 169.2 0.084 169.224 ;
    END
  END cr_addr[97]
  PIN cr_addr[98]
    DIRECTION INPUT ;
    USE SIGNAL ;
    PORT
      LAYER M4 ;
        RECT  0 169.296 0.084 169.32 ;
    END
  END cr_addr[98]
  PIN cr_addr[99]
    DIRECTION INPUT ;
    USE SIGNAL ;
    PORT
      LAYER M4 ;
        RECT  0 169.392 0.084 169.416 ;
    END
  END cr_addr[99]
  PIN cr_addr[9]
    DIRECTION INPUT ;
    USE SIGNAL ;
    PORT
      LAYER M4 ;
        RECT  0 166.896 0.084 166.92 ;
    END
  END cr_addr[9]
  PIN cr_re[0]
    DIRECTION INPUT ;
    USE SIGNAL ;
    PORT
      LAYER M4 ;
        RECT  0 179.088 0.084 179.112 ;
    END
  END cr_re[0]
  PIN cr_re[1]
    DIRECTION INPUT ;
    USE SIGNAL ;
    PORT
      LAYER M4 ;
        RECT  0 179.184 0.084 179.208 ;
    END
  END cr_re[1]
  PIN cr_re[2]
    DIRECTION INPUT ;
    USE SIGNAL ;
    PORT
      LAYER M4 ;
        RECT  0 179.28 0.084 179.304 ;
    END
  END cr_re[2]
  PIN cr_re[3]
    DIRECTION INPUT ;
    USE SIGNAL ;
    PORT
      LAYER M4 ;
        RECT  0 179.376 0.084 179.4 ;
    END
  END cr_re[3]
  PIN cr_re[4]
    DIRECTION INPUT ;
    USE SIGNAL ;
    PORT
      LAYER M4 ;
        RECT  0 179.472 0.084 179.496 ;
    END
  END cr_re[4]
  PIN cr_re[5]
    DIRECTION INPUT ;
    USE SIGNAL ;
    PORT
      LAYER M4 ;
        RECT  0 179.568 0.084 179.592 ;
    END
  END cr_re[5]
  PIN cr_re[6]
    DIRECTION INPUT ;
    USE SIGNAL ;
    PORT
      LAYER M4 ;
        RECT  0 179.664 0.084 179.688 ;
    END
  END cr_re[6]
  PIN cr_re[7]
    DIRECTION INPUT ;
    USE SIGNAL ;
    PORT
      LAYER M4 ;
        RECT  0 179.76 0.084 179.784 ;
    END
  END cr_re[7]
  PIN fault
    DIRECTION OUTPUT ;
    USE SIGNAL ;
    PORT
      LAYER M5 ;
        RECT  20.016 0 20.04 0.084 ;
    END
  END fault
  PIN q[0]
    DIRECTION OUTPUT ;
    USE SIGNAL ;
    PORT
      LAYER M4 ;
        RECT  0 179.856 0.084 179.88 ;
    END
  END q[0]
  PIN q[100]
    DIRECTION OUTPUT ;
    USE SIGNAL ;
    PORT
      LAYER M4 ;
        RECT  0 186.384 0.084 186.408 ;
    END
  END q[100]
  PIN q[101]
    DIRECTION OUTPUT ;
    USE SIGNAL ;
    PORT
      LAYER M4 ;
        RECT  0 186.48 0.084 186.504 ;
    END
  END q[101]
  PIN q[102]
    DIRECTION OUTPUT ;
    USE SIGNAL ;
    PORT
      LAYER M4 ;
        RECT  0 186.576 0.084 186.6 ;
    END
  END q[102]
  PIN q[103]
    DIRECTION OUTPUT ;
    USE SIGNAL ;
    PORT
      LAYER M4 ;
        RECT  0 186.672 0.084 186.696 ;
    END
  END q[103]
  PIN q[104]
    DIRECTION OUTPUT ;
    USE SIGNAL ;
    PORT
      LAYER M4 ;
        RECT  0 186.768 0.084 186.792 ;
    END
  END q[104]
  PIN q[105]
    DIRECTION OUTPUT ;
    USE SIGNAL ;
    PORT
      LAYER M4 ;
        RECT  0 186.864 0.084 186.888 ;
    END
  END q[105]
  PIN q[106]
    DIRECTION OUTPUT ;
    USE SIGNAL ;
    PORT
      LAYER M4 ;
        RECT  0 186.96 0.084 186.984 ;
    END
  END q[106]
  PIN q[107]
    DIRECTION OUTPUT ;
    USE SIGNAL ;
    PORT
      LAYER M4 ;
        RECT  0 187.056 0.084 187.08 ;
    END
  END q[107]
  PIN q[108]
    DIRECTION OUTPUT ;
    USE SIGNAL ;
    PORT
      LAYER M4 ;
        RECT  0 187.152 0.084 187.176 ;
    END
  END q[108]
  PIN q[109]
    DIRECTION OUTPUT ;
    USE SIGNAL ;
    PORT
      LAYER M4 ;
        RECT  0 187.248 0.084 187.272 ;
    END
  END q[109]
  PIN q[10]
    DIRECTION OUTPUT ;
    USE SIGNAL ;
    PORT
      LAYER M4 ;
        RECT  0 180.816 0.084 180.84 ;
    END
  END q[10]
  PIN q[110]
    DIRECTION OUTPUT ;
    USE SIGNAL ;
    PORT
      LAYER M4 ;
        RECT  0 187.344 0.084 187.368 ;
    END
  END q[110]
  PIN q[111]
    DIRECTION OUTPUT ;
    USE SIGNAL ;
    PORT
      LAYER M4 ;
        RECT  0 187.44 0.084 187.464 ;
    END
  END q[111]
  PIN q[112]
    DIRECTION OUTPUT ;
    USE SIGNAL ;
    PORT
      LAYER M4 ;
        RECT  0 187.536 0.084 187.56 ;
    END
  END q[112]
  PIN q[113]
    DIRECTION OUTPUT ;
    USE SIGNAL ;
    PORT
      LAYER M4 ;
        RECT  0 187.632 0.084 187.656 ;
    END
  END q[113]
  PIN q[114]
    DIRECTION OUTPUT ;
    USE SIGNAL ;
    PORT
      LAYER M4 ;
        RECT  0 187.728 0.084 187.752 ;
    END
  END q[114]
  PIN q[115]
    DIRECTION OUTPUT ;
    USE SIGNAL ;
    PORT
      LAYER M4 ;
        RECT  0 187.824 0.084 187.848 ;
    END
  END q[115]
  PIN q[116]
    DIRECTION OUTPUT ;
    USE SIGNAL ;
    PORT
      LAYER M4 ;
        RECT  0 187.92 0.084 187.944 ;
    END
  END q[116]
  PIN q[117]
    DIRECTION OUTPUT ;
    USE SIGNAL ;
    PORT
      LAYER M4 ;
        RECT  0 188.016 0.084 188.04 ;
    END
  END q[117]
  PIN q[118]
    DIRECTION OUTPUT ;
    USE SIGNAL ;
    PORT
      LAYER M4 ;
        RECT  0 188.112 0.084 188.136 ;
    END
  END q[118]
  PIN q[119]
    DIRECTION OUTPUT ;
    USE SIGNAL ;
    PORT
      LAYER M4 ;
        RECT  0 188.208 0.084 188.232 ;
    END
  END q[119]
  PIN q[11]
    DIRECTION OUTPUT ;
    USE SIGNAL ;
    PORT
      LAYER M4 ;
        RECT  0 180.912 0.084 180.936 ;
    END
  END q[11]
  PIN q[120]
    DIRECTION OUTPUT ;
    USE SIGNAL ;
    PORT
      LAYER M4 ;
        RECT  0 191.376 0.084 191.4 ;
    END
  END q[120]
  PIN q[121]
    DIRECTION OUTPUT ;
    USE SIGNAL ;
    PORT
      LAYER M4 ;
        RECT  0 191.472 0.084 191.496 ;
    END
  END q[121]
  PIN q[122]
    DIRECTION OUTPUT ;
    USE SIGNAL ;
    PORT
      LAYER M4 ;
        RECT  0 191.568 0.084 191.592 ;
    END
  END q[122]
  PIN q[123]
    DIRECTION OUTPUT ;
    USE SIGNAL ;
    PORT
      LAYER M4 ;
        RECT  0 191.664 0.084 191.688 ;
    END
  END q[123]
  PIN q[124]
    DIRECTION OUTPUT ;
    USE SIGNAL ;
    PORT
      LAYER M4 ;
        RECT  0 191.76 0.084 191.784 ;
    END
  END q[124]
  PIN q[125]
    DIRECTION OUTPUT ;
    USE SIGNAL ;
    PORT
      LAYER M4 ;
        RECT  0 191.856 0.084 191.88 ;
    END
  END q[125]
  PIN q[126]
    DIRECTION OUTPUT ;
    USE SIGNAL ;
    PORT
      LAYER M4 ;
        RECT  0 191.952 0.084 191.976 ;
    END
  END q[126]
  PIN q[127]
    DIRECTION OUTPUT ;
    USE SIGNAL ;
    PORT
      LAYER M4 ;
        RECT  0 192.048 0.084 192.072 ;
    END
  END q[127]
  PIN q[128]
    DIRECTION OUTPUT ;
    USE SIGNAL ;
    PORT
      LAYER M4 ;
        RECT  0 192.144 0.084 192.168 ;
    END
  END q[128]
  PIN q[129]
    DIRECTION OUTPUT ;
    USE SIGNAL ;
    PORT
      LAYER M4 ;
        RECT  0 192.24 0.084 192.264 ;
    END
  END q[129]
  PIN q[12]
    DIRECTION OUTPUT ;
    USE SIGNAL ;
    PORT
      LAYER M4 ;
        RECT  0 181.008 0.084 181.032 ;
    END
  END q[12]
  PIN q[130]
    DIRECTION OUTPUT ;
    USE SIGNAL ;
    PORT
      LAYER M4 ;
        RECT  0 192.336 0.084 192.36 ;
    END
  END q[130]
  PIN q[131]
    DIRECTION OUTPUT ;
    USE SIGNAL ;
    PORT
      LAYER M4 ;
        RECT  0 192.432 0.084 192.456 ;
    END
  END q[131]
  PIN q[132]
    DIRECTION OUTPUT ;
    USE SIGNAL ;
    PORT
      LAYER M4 ;
        RECT  0 192.528 0.084 192.552 ;
    END
  END q[132]
  PIN q[133]
    DIRECTION OUTPUT ;
    USE SIGNAL ;
    PORT
      LAYER M4 ;
        RECT  0 192.624 0.084 192.648 ;
    END
  END q[133]
  PIN q[134]
    DIRECTION OUTPUT ;
    USE SIGNAL ;
    PORT
      LAYER M4 ;
        RECT  0 192.72 0.084 192.744 ;
    END
  END q[134]
  PIN q[135]
    DIRECTION OUTPUT ;
    USE SIGNAL ;
    PORT
      LAYER M4 ;
        RECT  0 192.816 0.084 192.84 ;
    END
  END q[135]
  PIN q[136]
    DIRECTION OUTPUT ;
    USE SIGNAL ;
    PORT
      LAYER M4 ;
        RECT  0 192.912 0.084 192.936 ;
    END
  END q[136]
  PIN q[137]
    DIRECTION OUTPUT ;
    USE SIGNAL ;
    PORT
      LAYER M4 ;
        RECT  0 193.008 0.084 193.032 ;
    END
  END q[137]
  PIN q[138]
    DIRECTION OUTPUT ;
    USE SIGNAL ;
    PORT
      LAYER M4 ;
        RECT  0 193.104 0.084 193.128 ;
    END
  END q[138]
  PIN q[139]
    DIRECTION OUTPUT ;
    USE SIGNAL ;
    PORT
      LAYER M4 ;
        RECT  0 193.2 0.084 193.224 ;
    END
  END q[139]
  PIN q[13]
    DIRECTION OUTPUT ;
    USE SIGNAL ;
    PORT
      LAYER M4 ;
        RECT  0 181.104 0.084 181.128 ;
    END
  END q[13]
  PIN q[140]
    DIRECTION OUTPUT ;
    USE SIGNAL ;
    PORT
      LAYER M4 ;
        RECT  0 193.296 0.084 193.32 ;
    END
  END q[140]
  PIN q[141]
    DIRECTION OUTPUT ;
    USE SIGNAL ;
    PORT
      LAYER M4 ;
        RECT  0 193.392 0.084 193.416 ;
    END
  END q[141]
  PIN q[142]
    DIRECTION OUTPUT ;
    USE SIGNAL ;
    PORT
      LAYER M4 ;
        RECT  0 193.488 0.084 193.512 ;
    END
  END q[142]
  PIN q[143]
    DIRECTION OUTPUT ;
    USE SIGNAL ;
    PORT
      LAYER M4 ;
        RECT  0 193.584 0.084 193.608 ;
    END
  END q[143]
  PIN q[144]
    DIRECTION OUTPUT ;
    USE SIGNAL ;
    PORT
      LAYER M4 ;
        RECT  0 193.68 0.084 193.704 ;
    END
  END q[144]
  PIN q[145]
    DIRECTION OUTPUT ;
    USE SIGNAL ;
    PORT
      LAYER M4 ;
        RECT  0 193.776 0.084 193.8 ;
    END
  END q[145]
  PIN q[146]
    DIRECTION OUTPUT ;
    USE SIGNAL ;
    PORT
      LAYER M4 ;
        RECT  0 193.872 0.084 193.896 ;
    END
  END q[146]
  PIN q[147]
    DIRECTION OUTPUT ;
    USE SIGNAL ;
    PORT
      LAYER M4 ;
        RECT  0 193.968 0.084 193.992 ;
    END
  END q[147]
  PIN q[148]
    DIRECTION OUTPUT ;
    USE SIGNAL ;
    PORT
      LAYER M4 ;
        RECT  0 194.064 0.084 194.088 ;
    END
  END q[148]
  PIN q[149]
    DIRECTION OUTPUT ;
    USE SIGNAL ;
    PORT
      LAYER M4 ;
        RECT  0 194.16 0.084 194.184 ;
    END
  END q[149]
  PIN q[14]
    DIRECTION OUTPUT ;
    USE SIGNAL ;
    PORT
      LAYER M4 ;
        RECT  0 181.2 0.084 181.224 ;
    END
  END q[14]
  PIN q[150]
    DIRECTION OUTPUT ;
    USE SIGNAL ;
    PORT
      LAYER M4 ;
        RECT  0 194.256 0.084 194.28 ;
    END
  END q[150]
  PIN q[151]
    DIRECTION OUTPUT ;
    USE SIGNAL ;
    PORT
      LAYER M4 ;
        RECT  0 194.352 0.084 194.376 ;
    END
  END q[151]
  PIN q[152]
    DIRECTION OUTPUT ;
    USE SIGNAL ;
    PORT
      LAYER M4 ;
        RECT  0 182.16 0.084 182.184 ;
    END
  END q[152]
  PIN q[153]
    DIRECTION OUTPUT ;
    USE SIGNAL ;
    PORT
      LAYER M4 ;
        RECT  0 182.256 0.084 182.28 ;
    END
  END q[153]
  PIN q[154]
    DIRECTION OUTPUT ;
    USE SIGNAL ;
    PORT
      LAYER M4 ;
        RECT  0 182.352 0.084 182.376 ;
    END
  END q[154]
  PIN q[155]
    DIRECTION OUTPUT ;
    USE SIGNAL ;
    PORT
      LAYER M4 ;
        RECT  0 182.448 0.084 182.472 ;
    END
  END q[155]
  PIN q[156]
    DIRECTION OUTPUT ;
    USE SIGNAL ;
    PORT
      LAYER M4 ;
        RECT  0 182.544 0.084 182.568 ;
    END
  END q[156]
  PIN q[157]
    DIRECTION OUTPUT ;
    USE SIGNAL ;
    PORT
      LAYER M4 ;
        RECT  0 182.64 0.084 182.664 ;
    END
  END q[157]
  PIN q[158]
    DIRECTION OUTPUT ;
    USE SIGNAL ;
    PORT
      LAYER M4 ;
        RECT  0 182.736 0.084 182.76 ;
    END
  END q[158]
  PIN q[159]
    DIRECTION OUTPUT ;
    USE SIGNAL ;
    PORT
      LAYER M4 ;
        RECT  0 182.832 0.084 182.856 ;
    END
  END q[159]
  PIN q[15]
    DIRECTION OUTPUT ;
    USE SIGNAL ;
    PORT
      LAYER M4 ;
        RECT  0 181.296 0.084 181.32 ;
    END
  END q[15]
  PIN q[160]
    DIRECTION OUTPUT ;
    USE SIGNAL ;
    PORT
      LAYER M4 ;
        RECT  0 182.928 0.084 182.952 ;
    END
  END q[160]
  PIN q[161]
    DIRECTION OUTPUT ;
    USE SIGNAL ;
    PORT
      LAYER M4 ;
        RECT  0 183.024 0.084 183.048 ;
    END
  END q[161]
  PIN q[162]
    DIRECTION OUTPUT ;
    USE SIGNAL ;
    PORT
      LAYER M4 ;
        RECT  0 183.12 0.084 183.144 ;
    END
  END q[162]
  PIN q[163]
    DIRECTION OUTPUT ;
    USE SIGNAL ;
    PORT
      LAYER M4 ;
        RECT  0 183.216 0.084 183.24 ;
    END
  END q[163]
  PIN q[164]
    DIRECTION OUTPUT ;
    USE SIGNAL ;
    PORT
      LAYER M4 ;
        RECT  0 183.312 0.084 183.336 ;
    END
  END q[164]
  PIN q[165]
    DIRECTION OUTPUT ;
    USE SIGNAL ;
    PORT
      LAYER M4 ;
        RECT  0 183.408 0.084 183.432 ;
    END
  END q[165]
  PIN q[166]
    DIRECTION OUTPUT ;
    USE SIGNAL ;
    PORT
      LAYER M4 ;
        RECT  0 183.504 0.084 183.528 ;
    END
  END q[166]
  PIN q[167]
    DIRECTION OUTPUT ;
    USE SIGNAL ;
    PORT
      LAYER M4 ;
        RECT  0 183.6 0.084 183.624 ;
    END
  END q[167]
  PIN q[168]
    DIRECTION OUTPUT ;
    USE SIGNAL ;
    PORT
      LAYER M4 ;
        RECT  0 183.696 0.084 183.72 ;
    END
  END q[168]
  PIN q[169]
    DIRECTION OUTPUT ;
    USE SIGNAL ;
    PORT
      LAYER M4 ;
        RECT  0 183.792 0.084 183.816 ;
    END
  END q[169]
  PIN q[16]
    DIRECTION OUTPUT ;
    USE SIGNAL ;
    PORT
      LAYER M4 ;
        RECT  0 181.392 0.084 181.416 ;
    END
  END q[16]
  PIN q[170]
    DIRECTION OUTPUT ;
    USE SIGNAL ;
    PORT
      LAYER M4 ;
        RECT  0 183.888 0.084 183.912 ;
    END
  END q[170]
  PIN q[171]
    DIRECTION OUTPUT ;
    USE SIGNAL ;
    PORT
      LAYER M4 ;
        RECT  0 183.984 0.084 184.008 ;
    END
  END q[171]
  PIN q[172]
    DIRECTION OUTPUT ;
    USE SIGNAL ;
    PORT
      LAYER M4 ;
        RECT  0 184.08 0.084 184.104 ;
    END
  END q[172]
  PIN q[173]
    DIRECTION OUTPUT ;
    USE SIGNAL ;
    PORT
      LAYER M4 ;
        RECT  0 184.176 0.084 184.2 ;
    END
  END q[173]
  PIN q[174]
    DIRECTION OUTPUT ;
    USE SIGNAL ;
    PORT
      LAYER M4 ;
        RECT  0 184.272 0.084 184.296 ;
    END
  END q[174]
  PIN q[175]
    DIRECTION OUTPUT ;
    USE SIGNAL ;
    PORT
      LAYER M4 ;
        RECT  0 184.368 0.084 184.392 ;
    END
  END q[175]
  PIN q[176]
    DIRECTION OUTPUT ;
    USE SIGNAL ;
    PORT
      LAYER M4 ;
        RECT  0 184.464 0.084 184.488 ;
    END
  END q[176]
  PIN q[177]
    DIRECTION OUTPUT ;
    USE SIGNAL ;
    PORT
      LAYER M4 ;
        RECT  0 184.56 0.084 184.584 ;
    END
  END q[177]
  PIN q[178]
    DIRECTION OUTPUT ;
    USE SIGNAL ;
    PORT
      LAYER M4 ;
        RECT  0 184.656 0.084 184.68 ;
    END
  END q[178]
  PIN q[179]
    DIRECTION OUTPUT ;
    USE SIGNAL ;
    PORT
      LAYER M4 ;
        RECT  0 184.752 0.084 184.776 ;
    END
  END q[179]
  PIN q[17]
    DIRECTION OUTPUT ;
    USE SIGNAL ;
    PORT
      LAYER M4 ;
        RECT  0 181.488 0.084 181.512 ;
    END
  END q[17]
  PIN q[180]
    DIRECTION OUTPUT ;
    USE SIGNAL ;
    PORT
      LAYER M4 ;
        RECT  0 184.848 0.084 184.872 ;
    END
  END q[180]
  PIN q[181]
    DIRECTION OUTPUT ;
    USE SIGNAL ;
    PORT
      LAYER M4 ;
        RECT  0 184.944 0.084 184.968 ;
    END
  END q[181]
  PIN q[182]
    DIRECTION OUTPUT ;
    USE SIGNAL ;
    PORT
      LAYER M4 ;
        RECT  0 185.04 0.084 185.064 ;
    END
  END q[182]
  PIN q[183]
    DIRECTION OUTPUT ;
    USE SIGNAL ;
    PORT
      LAYER M4 ;
        RECT  0 185.136 0.084 185.16 ;
    END
  END q[183]
  PIN q[184]
    DIRECTION OUTPUT ;
    USE SIGNAL ;
    PORT
      LAYER M4 ;
        RECT  0 198.288 0.084 198.312 ;
    END
  END q[184]
  PIN q[185]
    DIRECTION OUTPUT ;
    USE SIGNAL ;
    PORT
      LAYER M4 ;
        RECT  0 198.384 0.084 198.408 ;
    END
  END q[185]
  PIN q[186]
    DIRECTION OUTPUT ;
    USE SIGNAL ;
    PORT
      LAYER M4 ;
        RECT  0 198.48 0.084 198.504 ;
    END
  END q[186]
  PIN q[187]
    DIRECTION OUTPUT ;
    USE SIGNAL ;
    PORT
      LAYER M4 ;
        RECT  0 198.576 0.084 198.6 ;
    END
  END q[187]
  PIN q[188]
    DIRECTION OUTPUT ;
    USE SIGNAL ;
    PORT
      LAYER M4 ;
        RECT  0 198.672 0.084 198.696 ;
    END
  END q[188]
  PIN q[189]
    DIRECTION OUTPUT ;
    USE SIGNAL ;
    PORT
      LAYER M4 ;
        RECT  0 198.768 0.084 198.792 ;
    END
  END q[189]
  PIN q[18]
    DIRECTION OUTPUT ;
    USE SIGNAL ;
    PORT
      LAYER M4 ;
        RECT  0 181.584 0.084 181.608 ;
    END
  END q[18]
  PIN q[190]
    DIRECTION OUTPUT ;
    USE SIGNAL ;
    PORT
      LAYER M4 ;
        RECT  0 198.864 0.084 198.888 ;
    END
  END q[190]
  PIN q[191]
    DIRECTION OUTPUT ;
    USE SIGNAL ;
    PORT
      LAYER M4 ;
        RECT  0 198.96 0.084 198.984 ;
    END
  END q[191]
  PIN q[192]
    DIRECTION OUTPUT ;
    USE SIGNAL ;
    PORT
      LAYER M4 ;
        RECT  0 199.056 0.084 199.08 ;
    END
  END q[192]
  PIN q[193]
    DIRECTION OUTPUT ;
    USE SIGNAL ;
    PORT
      LAYER M4 ;
        RECT  0 199.152 0.084 199.176 ;
    END
  END q[193]
  PIN q[194]
    DIRECTION OUTPUT ;
    USE SIGNAL ;
    PORT
      LAYER M4 ;
        RECT  0 199.248 0.084 199.272 ;
    END
  END q[194]
  PIN q[195]
    DIRECTION OUTPUT ;
    USE SIGNAL ;
    PORT
      LAYER M4 ;
        RECT  0 199.344 0.084 199.368 ;
    END
  END q[195]
  PIN q[196]
    DIRECTION OUTPUT ;
    USE SIGNAL ;
    PORT
      LAYER M4 ;
        RECT  0 199.44 0.084 199.464 ;
    END
  END q[196]
  PIN q[197]
    DIRECTION OUTPUT ;
    USE SIGNAL ;
    PORT
      LAYER M4 ;
        RECT  0 199.536 0.084 199.56 ;
    END
  END q[197]
  PIN q[198]
    DIRECTION OUTPUT ;
    USE SIGNAL ;
    PORT
      LAYER M4 ;
        RECT  0 199.632 0.084 199.656 ;
    END
  END q[198]
  PIN q[199]
    DIRECTION OUTPUT ;
    USE SIGNAL ;
    PORT
      LAYER M4 ;
        RECT  0 199.728 0.084 199.752 ;
    END
  END q[199]
  PIN q[19]
    DIRECTION OUTPUT ;
    USE SIGNAL ;
    PORT
      LAYER M4 ;
        RECT  0 181.68 0.084 181.704 ;
    END
  END q[19]
  PIN q[1]
    DIRECTION OUTPUT ;
    USE SIGNAL ;
    PORT
      LAYER M4 ;
        RECT  0 179.952 0.084 179.976 ;
    END
  END q[1]
  PIN q[200]
    DIRECTION OUTPUT ;
    USE SIGNAL ;
    PORT
      LAYER M4 ;
        RECT  0 199.824 0.084 199.848 ;
    END
  END q[200]
  PIN q[201]
    DIRECTION OUTPUT ;
    USE SIGNAL ;
    PORT
      LAYER M4 ;
        RECT  0 199.92 0.084 199.944 ;
    END
  END q[201]
  PIN q[202]
    DIRECTION OUTPUT ;
    USE SIGNAL ;
    PORT
      LAYER M4 ;
        RECT  0 200.016 0.084 200.04 ;
    END
  END q[202]
  PIN q[203]
    DIRECTION OUTPUT ;
    USE SIGNAL ;
    PORT
      LAYER M4 ;
        RECT  0 200.112 0.084 200.136 ;
    END
  END q[203]
  PIN q[204]
    DIRECTION OUTPUT ;
    USE SIGNAL ;
    PORT
      LAYER M4 ;
        RECT  0 200.208 0.084 200.232 ;
    END
  END q[204]
  PIN q[205]
    DIRECTION OUTPUT ;
    USE SIGNAL ;
    PORT
      LAYER M4 ;
        RECT  0 200.304 0.084 200.328 ;
    END
  END q[205]
  PIN q[206]
    DIRECTION OUTPUT ;
    USE SIGNAL ;
    PORT
      LAYER M4 ;
        RECT  0 200.4 0.084 200.424 ;
    END
  END q[206]
  PIN q[207]
    DIRECTION OUTPUT ;
    USE SIGNAL ;
    PORT
      LAYER M4 ;
        RECT  0 200.496 0.084 200.52 ;
    END
  END q[207]
  PIN q[208]
    DIRECTION OUTPUT ;
    USE SIGNAL ;
    PORT
      LAYER M4 ;
        RECT  0 200.592 0.084 200.616 ;
    END
  END q[208]
  PIN q[209]
    DIRECTION OUTPUT ;
    USE SIGNAL ;
    PORT
      LAYER M4 ;
        RECT  0 200.688 0.084 200.712 ;
    END
  END q[209]
  PIN q[20]
    DIRECTION OUTPUT ;
    USE SIGNAL ;
    PORT
      LAYER M4 ;
        RECT  0 181.776 0.084 181.8 ;
    END
  END q[20]
  PIN q[210]
    DIRECTION OUTPUT ;
    USE SIGNAL ;
    PORT
      LAYER M4 ;
        RECT  0 200.784 0.084 200.808 ;
    END
  END q[210]
  PIN q[211]
    DIRECTION OUTPUT ;
    USE SIGNAL ;
    PORT
      LAYER M4 ;
        RECT  0 200.88 0.084 200.904 ;
    END
  END q[211]
  PIN q[212]
    DIRECTION OUTPUT ;
    USE SIGNAL ;
    PORT
      LAYER M4 ;
        RECT  0 200.976 0.084 201 ;
    END
  END q[212]
  PIN q[213]
    DIRECTION OUTPUT ;
    USE SIGNAL ;
    PORT
      LAYER M4 ;
        RECT  0 201.072 0.084 201.096 ;
    END
  END q[213]
  PIN q[214]
    DIRECTION OUTPUT ;
    USE SIGNAL ;
    PORT
      LAYER M4 ;
        RECT  0 201.168 0.084 201.192 ;
    END
  END q[214]
  PIN q[215]
    DIRECTION OUTPUT ;
    USE SIGNAL ;
    PORT
      LAYER M4 ;
        RECT  0 201.264 0.084 201.288 ;
    END
  END q[215]
  PIN q[216]
    DIRECTION OUTPUT ;
    USE SIGNAL ;
    PORT
      LAYER M4 ;
        RECT  0 201.36 0.084 201.384 ;
    END
  END q[216]
  PIN q[217]
    DIRECTION OUTPUT ;
    USE SIGNAL ;
    PORT
      LAYER M4 ;
        RECT  0 201.456 0.084 201.48 ;
    END
  END q[217]
  PIN q[218]
    DIRECTION OUTPUT ;
    USE SIGNAL ;
    PORT
      LAYER M4 ;
        RECT  0 201.552 0.084 201.576 ;
    END
  END q[218]
  PIN q[219]
    DIRECTION OUTPUT ;
    USE SIGNAL ;
    PORT
      LAYER M4 ;
        RECT  0 201.648 0.084 201.672 ;
    END
  END q[219]
  PIN q[21]
    DIRECTION OUTPUT ;
    USE SIGNAL ;
    PORT
      LAYER M4 ;
        RECT  0 181.872 0.084 181.896 ;
    END
  END q[21]
  PIN q[220]
    DIRECTION OUTPUT ;
    USE SIGNAL ;
    PORT
      LAYER M4 ;
        RECT  0 201.744 0.084 201.768 ;
    END
  END q[220]
  PIN q[221]
    DIRECTION OUTPUT ;
    USE SIGNAL ;
    PORT
      LAYER M4 ;
        RECT  0 201.84 0.084 201.864 ;
    END
  END q[221]
  PIN q[222]
    DIRECTION OUTPUT ;
    USE SIGNAL ;
    PORT
      LAYER M4 ;
        RECT  0 201.936 0.084 201.96 ;
    END
  END q[222]
  PIN q[223]
    DIRECTION OUTPUT ;
    USE SIGNAL ;
    PORT
      LAYER M4 ;
        RECT  0 202.032 0.084 202.056 ;
    END
  END q[223]
  PIN q[224]
    DIRECTION OUTPUT ;
    USE SIGNAL ;
    PORT
      LAYER M4 ;
        RECT  0 202.128 0.084 202.152 ;
    END
  END q[224]
  PIN q[225]
    DIRECTION OUTPUT ;
    USE SIGNAL ;
    PORT
      LAYER M4 ;
        RECT  0 202.224 0.084 202.248 ;
    END
  END q[225]
  PIN q[226]
    DIRECTION OUTPUT ;
    USE SIGNAL ;
    PORT
      LAYER M4 ;
        RECT  0 202.32 0.084 202.344 ;
    END
  END q[226]
  PIN q[227]
    DIRECTION OUTPUT ;
    USE SIGNAL ;
    PORT
      LAYER M4 ;
        RECT  0 202.416 0.084 202.44 ;
    END
  END q[227]
  PIN q[228]
    DIRECTION OUTPUT ;
    USE SIGNAL ;
    PORT
      LAYER M4 ;
        RECT  0 202.512 0.084 202.536 ;
    END
  END q[228]
  PIN q[229]
    DIRECTION OUTPUT ;
    USE SIGNAL ;
    PORT
      LAYER M4 ;
        RECT  0 202.608 0.084 202.632 ;
    END
  END q[229]
  PIN q[22]
    DIRECTION OUTPUT ;
    USE SIGNAL ;
    PORT
      LAYER M4 ;
        RECT  0 181.968 0.084 181.992 ;
    END
  END q[22]
  PIN q[230]
    DIRECTION OUTPUT ;
    USE SIGNAL ;
    PORT
      LAYER M4 ;
        RECT  0 202.704 0.084 202.728 ;
    END
  END q[230]
  PIN q[231]
    DIRECTION OUTPUT ;
    USE SIGNAL ;
    PORT
      LAYER M4 ;
        RECT  0 202.8 0.084 202.824 ;
    END
  END q[231]
  PIN q[232]
    DIRECTION OUTPUT ;
    USE SIGNAL ;
    PORT
      LAYER M4 ;
        RECT  0 202.896 0.084 202.92 ;
    END
  END q[232]
  PIN q[233]
    DIRECTION OUTPUT ;
    USE SIGNAL ;
    PORT
      LAYER M4 ;
        RECT  0 202.992 0.084 203.016 ;
    END
  END q[233]
  PIN q[234]
    DIRECTION OUTPUT ;
    USE SIGNAL ;
    PORT
      LAYER M4 ;
        RECT  0 203.088 0.084 203.112 ;
    END
  END q[234]
  PIN q[235]
    DIRECTION OUTPUT ;
    USE SIGNAL ;
    PORT
      LAYER M4 ;
        RECT  0 203.184 0.084 203.208 ;
    END
  END q[235]
  PIN q[236]
    DIRECTION OUTPUT ;
    USE SIGNAL ;
    PORT
      LAYER M4 ;
        RECT  0 203.28 0.084 203.304 ;
    END
  END q[236]
  PIN q[237]
    DIRECTION OUTPUT ;
    USE SIGNAL ;
    PORT
      LAYER M4 ;
        RECT  0 203.376 0.084 203.4 ;
    END
  END q[237]
  PIN q[238]
    DIRECTION OUTPUT ;
    USE SIGNAL ;
    PORT
      LAYER M4 ;
        RECT  0 203.472 0.084 203.496 ;
    END
  END q[238]
  PIN q[239]
    DIRECTION OUTPUT ;
    USE SIGNAL ;
    PORT
      LAYER M4 ;
        RECT  0 203.568 0.084 203.592 ;
    END
  END q[239]
  PIN q[23]
    DIRECTION OUTPUT ;
    USE SIGNAL ;
    PORT
      LAYER M4 ;
        RECT  0 182.064 0.084 182.088 ;
    END
  END q[23]
  PIN q[240]
    DIRECTION OUTPUT ;
    USE SIGNAL ;
    PORT
      LAYER M4 ;
        RECT  0 203.664 0.084 203.688 ;
    END
  END q[240]
  PIN q[241]
    DIRECTION OUTPUT ;
    USE SIGNAL ;
    PORT
      LAYER M4 ;
        RECT  0 203.76 0.084 203.784 ;
    END
  END q[241]
  PIN q[242]
    DIRECTION OUTPUT ;
    USE SIGNAL ;
    PORT
      LAYER M4 ;
        RECT  0 203.856 0.084 203.88 ;
    END
  END q[242]
  PIN q[243]
    DIRECTION OUTPUT ;
    USE SIGNAL ;
    PORT
      LAYER M4 ;
        RECT  0 203.952 0.084 203.976 ;
    END
  END q[243]
  PIN q[244]
    DIRECTION OUTPUT ;
    USE SIGNAL ;
    PORT
      LAYER M4 ;
        RECT  0 204.048 0.084 204.072 ;
    END
  END q[244]
  PIN q[245]
    DIRECTION OUTPUT ;
    USE SIGNAL ;
    PORT
      LAYER M4 ;
        RECT  0 204.144 0.084 204.168 ;
    END
  END q[245]
  PIN q[246]
    DIRECTION OUTPUT ;
    USE SIGNAL ;
    PORT
      LAYER M4 ;
        RECT  0 204.24 0.084 204.264 ;
    END
  END q[246]
  PIN q[247]
    DIRECTION OUTPUT ;
    USE SIGNAL ;
    PORT
      LAYER M4 ;
        RECT  0 204.336 0.084 204.36 ;
    END
  END q[247]
  PIN q[248]
    DIRECTION OUTPUT ;
    USE SIGNAL ;
    PORT
      LAYER M4 ;
        RECT  0 206.736 0.084 206.76 ;
    END
  END q[248]
  PIN q[249]
    DIRECTION OUTPUT ;
    USE SIGNAL ;
    PORT
      LAYER M4 ;
        RECT  0 206.832 0.084 206.856 ;
    END
  END q[249]
  PIN q[24]
    DIRECTION OUTPUT ;
    USE SIGNAL ;
    PORT
      LAYER M4 ;
        RECT  0 188.304 0.084 188.328 ;
    END
  END q[24]
  PIN q[250]
    DIRECTION OUTPUT ;
    USE SIGNAL ;
    PORT
      LAYER M4 ;
        RECT  0 206.928 0.084 206.952 ;
    END
  END q[250]
  PIN q[251]
    DIRECTION OUTPUT ;
    USE SIGNAL ;
    PORT
      LAYER M4 ;
        RECT  0 207.024 0.084 207.048 ;
    END
  END q[251]
  PIN q[252]
    DIRECTION OUTPUT ;
    USE SIGNAL ;
    PORT
      LAYER M4 ;
        RECT  0 207.12 0.084 207.144 ;
    END
  END q[252]
  PIN q[253]
    DIRECTION OUTPUT ;
    USE SIGNAL ;
    PORT
      LAYER M4 ;
        RECT  0 207.216 0.084 207.24 ;
    END
  END q[253]
  PIN q[254]
    DIRECTION OUTPUT ;
    USE SIGNAL ;
    PORT
      LAYER M4 ;
        RECT  0 207.312 0.084 207.336 ;
    END
  END q[254]
  PIN q[255]
    DIRECTION OUTPUT ;
    USE SIGNAL ;
    PORT
      LAYER M4 ;
        RECT  0 207.408 0.084 207.432 ;
    END
  END q[255]
  PIN q[25]
    DIRECTION OUTPUT ;
    USE SIGNAL ;
    PORT
      LAYER M4 ;
        RECT  0 188.4 0.084 188.424 ;
    END
  END q[25]
  PIN q[26]
    DIRECTION OUTPUT ;
    USE SIGNAL ;
    PORT
      LAYER M4 ;
        RECT  0 188.496 0.084 188.52 ;
    END
  END q[26]
  PIN q[27]
    DIRECTION OUTPUT ;
    USE SIGNAL ;
    PORT
      LAYER M4 ;
        RECT  0 188.592 0.084 188.616 ;
    END
  END q[27]
  PIN q[28]
    DIRECTION OUTPUT ;
    USE SIGNAL ;
    PORT
      LAYER M4 ;
        RECT  0 188.688 0.084 188.712 ;
    END
  END q[28]
  PIN q[29]
    DIRECTION OUTPUT ;
    USE SIGNAL ;
    PORT
      LAYER M4 ;
        RECT  0 188.784 0.084 188.808 ;
    END
  END q[29]
  PIN q[2]
    DIRECTION OUTPUT ;
    USE SIGNAL ;
    PORT
      LAYER M4 ;
        RECT  0 180.048 0.084 180.072 ;
    END
  END q[2]
  PIN q[30]
    DIRECTION OUTPUT ;
    USE SIGNAL ;
    PORT
      LAYER M4 ;
        RECT  0 188.88 0.084 188.904 ;
    END
  END q[30]
  PIN q[31]
    DIRECTION OUTPUT ;
    USE SIGNAL ;
    PORT
      LAYER M4 ;
        RECT  0 188.976 0.084 189 ;
    END
  END q[31]
  PIN q[32]
    DIRECTION OUTPUT ;
    USE SIGNAL ;
    PORT
      LAYER M4 ;
        RECT  0 189.072 0.084 189.096 ;
    END
  END q[32]
  PIN q[33]
    DIRECTION OUTPUT ;
    USE SIGNAL ;
    PORT
      LAYER M4 ;
        RECT  0 189.168 0.084 189.192 ;
    END
  END q[33]
  PIN q[34]
    DIRECTION OUTPUT ;
    USE SIGNAL ;
    PORT
      LAYER M4 ;
        RECT  0 189.264 0.084 189.288 ;
    END
  END q[34]
  PIN q[35]
    DIRECTION OUTPUT ;
    USE SIGNAL ;
    PORT
      LAYER M4 ;
        RECT  0 189.36 0.084 189.384 ;
    END
  END q[35]
  PIN q[36]
    DIRECTION OUTPUT ;
    USE SIGNAL ;
    PORT
      LAYER M4 ;
        RECT  0 189.456 0.084 189.48 ;
    END
  END q[36]
  PIN q[37]
    DIRECTION OUTPUT ;
    USE SIGNAL ;
    PORT
      LAYER M4 ;
        RECT  0 189.552 0.084 189.576 ;
    END
  END q[37]
  PIN q[38]
    DIRECTION OUTPUT ;
    USE SIGNAL ;
    PORT
      LAYER M4 ;
        RECT  0 189.648 0.084 189.672 ;
    END
  END q[38]
  PIN q[39]
    DIRECTION OUTPUT ;
    USE SIGNAL ;
    PORT
      LAYER M4 ;
        RECT  0 189.744 0.084 189.768 ;
    END
  END q[39]
  PIN q[3]
    DIRECTION OUTPUT ;
    USE SIGNAL ;
    PORT
      LAYER M4 ;
        RECT  0 180.144 0.084 180.168 ;
    END
  END q[3]
  PIN q[40]
    DIRECTION OUTPUT ;
    USE SIGNAL ;
    PORT
      LAYER M4 ;
        RECT  0 189.84 0.084 189.864 ;
    END
  END q[40]
  PIN q[41]
    DIRECTION OUTPUT ;
    USE SIGNAL ;
    PORT
      LAYER M4 ;
        RECT  0 189.936 0.084 189.96 ;
    END
  END q[41]
  PIN q[42]
    DIRECTION OUTPUT ;
    USE SIGNAL ;
    PORT
      LAYER M4 ;
        RECT  0 190.032 0.084 190.056 ;
    END
  END q[42]
  PIN q[43]
    DIRECTION OUTPUT ;
    USE SIGNAL ;
    PORT
      LAYER M4 ;
        RECT  0 190.128 0.084 190.152 ;
    END
  END q[43]
  PIN q[44]
    DIRECTION OUTPUT ;
    USE SIGNAL ;
    PORT
      LAYER M4 ;
        RECT  0 190.224 0.084 190.248 ;
    END
  END q[44]
  PIN q[45]
    DIRECTION OUTPUT ;
    USE SIGNAL ;
    PORT
      LAYER M4 ;
        RECT  0 190.32 0.084 190.344 ;
    END
  END q[45]
  PIN q[46]
    DIRECTION OUTPUT ;
    USE SIGNAL ;
    PORT
      LAYER M4 ;
        RECT  0 190.416 0.084 190.44 ;
    END
  END q[46]
  PIN q[47]
    DIRECTION OUTPUT ;
    USE SIGNAL ;
    PORT
      LAYER M4 ;
        RECT  0 190.512 0.084 190.536 ;
    END
  END q[47]
  PIN q[48]
    DIRECTION OUTPUT ;
    USE SIGNAL ;
    PORT
      LAYER M4 ;
        RECT  0 190.608 0.084 190.632 ;
    END
  END q[48]
  PIN q[49]
    DIRECTION OUTPUT ;
    USE SIGNAL ;
    PORT
      LAYER M4 ;
        RECT  0 190.704 0.084 190.728 ;
    END
  END q[49]
  PIN q[4]
    DIRECTION OUTPUT ;
    USE SIGNAL ;
    PORT
      LAYER M4 ;
        RECT  0 180.24 0.084 180.264 ;
    END
  END q[4]
  PIN q[50]
    DIRECTION OUTPUT ;
    USE SIGNAL ;
    PORT
      LAYER M4 ;
        RECT  0 190.8 0.084 190.824 ;
    END
  END q[50]
  PIN q[51]
    DIRECTION OUTPUT ;
    USE SIGNAL ;
    PORT
      LAYER M4 ;
        RECT  0 190.896 0.084 190.92 ;
    END
  END q[51]
  PIN q[52]
    DIRECTION OUTPUT ;
    USE SIGNAL ;
    PORT
      LAYER M4 ;
        RECT  0 190.992 0.084 191.016 ;
    END
  END q[52]
  PIN q[53]
    DIRECTION OUTPUT ;
    USE SIGNAL ;
    PORT
      LAYER M4 ;
        RECT  0 191.088 0.084 191.112 ;
    END
  END q[53]
  PIN q[54]
    DIRECTION OUTPUT ;
    USE SIGNAL ;
    PORT
      LAYER M4 ;
        RECT  0 191.184 0.084 191.208 ;
    END
  END q[54]
  PIN q[55]
    DIRECTION OUTPUT ;
    USE SIGNAL ;
    PORT
      LAYER M4 ;
        RECT  0 191.28 0.084 191.304 ;
    END
  END q[55]
  PIN q[56]
    DIRECTION OUTPUT ;
    USE SIGNAL ;
    PORT
      LAYER M4 ;
        RECT  0 194.448 0.084 194.472 ;
    END
  END q[56]
  PIN q[57]
    DIRECTION OUTPUT ;
    USE SIGNAL ;
    PORT
      LAYER M4 ;
        RECT  0 194.544 0.084 194.568 ;
    END
  END q[57]
  PIN q[58]
    DIRECTION OUTPUT ;
    USE SIGNAL ;
    PORT
      LAYER M4 ;
        RECT  0 194.64 0.084 194.664 ;
    END
  END q[58]
  PIN q[59]
    DIRECTION OUTPUT ;
    USE SIGNAL ;
    PORT
      LAYER M4 ;
        RECT  0 194.736 0.084 194.76 ;
    END
  END q[59]
  PIN q[5]
    DIRECTION OUTPUT ;
    USE SIGNAL ;
    PORT
      LAYER M4 ;
        RECT  0 180.336 0.084 180.36 ;
    END
  END q[5]
  PIN q[60]
    DIRECTION OUTPUT ;
    USE SIGNAL ;
    PORT
      LAYER M4 ;
        RECT  0 194.832 0.084 194.856 ;
    END
  END q[60]
  PIN q[61]
    DIRECTION OUTPUT ;
    USE SIGNAL ;
    PORT
      LAYER M4 ;
        RECT  0 194.928 0.084 194.952 ;
    END
  END q[61]
  PIN q[62]
    DIRECTION OUTPUT ;
    USE SIGNAL ;
    PORT
      LAYER M4 ;
        RECT  0 195.024 0.084 195.048 ;
    END
  END q[62]
  PIN q[63]
    DIRECTION OUTPUT ;
    USE SIGNAL ;
    PORT
      LAYER M4 ;
        RECT  0 195.12 0.084 195.144 ;
    END
  END q[63]
  PIN q[64]
    DIRECTION OUTPUT ;
    USE SIGNAL ;
    PORT
      LAYER M4 ;
        RECT  0 195.216 0.084 195.24 ;
    END
  END q[64]
  PIN q[65]
    DIRECTION OUTPUT ;
    USE SIGNAL ;
    PORT
      LAYER M4 ;
        RECT  0 195.312 0.084 195.336 ;
    END
  END q[65]
  PIN q[66]
    DIRECTION OUTPUT ;
    USE SIGNAL ;
    PORT
      LAYER M4 ;
        RECT  0 195.408 0.084 195.432 ;
    END
  END q[66]
  PIN q[67]
    DIRECTION OUTPUT ;
    USE SIGNAL ;
    PORT
      LAYER M4 ;
        RECT  0 195.504 0.084 195.528 ;
    END
  END q[67]
  PIN q[68]
    DIRECTION OUTPUT ;
    USE SIGNAL ;
    PORT
      LAYER M4 ;
        RECT  0 195.6 0.084 195.624 ;
    END
  END q[68]
  PIN q[69]
    DIRECTION OUTPUT ;
    USE SIGNAL ;
    PORT
      LAYER M4 ;
        RECT  0 195.696 0.084 195.72 ;
    END
  END q[69]
  PIN q[6]
    DIRECTION OUTPUT ;
    USE SIGNAL ;
    PORT
      LAYER M4 ;
        RECT  0 180.432 0.084 180.456 ;
    END
  END q[6]
  PIN q[70]
    DIRECTION OUTPUT ;
    USE SIGNAL ;
    PORT
      LAYER M4 ;
        RECT  0 195.792 0.084 195.816 ;
    END
  END q[70]
  PIN q[71]
    DIRECTION OUTPUT ;
    USE SIGNAL ;
    PORT
      LAYER M4 ;
        RECT  0 195.888 0.084 195.912 ;
    END
  END q[71]
  PIN q[72]
    DIRECTION OUTPUT ;
    USE SIGNAL ;
    PORT
      LAYER M4 ;
        RECT  0 195.984 0.084 196.008 ;
    END
  END q[72]
  PIN q[73]
    DIRECTION OUTPUT ;
    USE SIGNAL ;
    PORT
      LAYER M4 ;
        RECT  0 196.08 0.084 196.104 ;
    END
  END q[73]
  PIN q[74]
    DIRECTION OUTPUT ;
    USE SIGNAL ;
    PORT
      LAYER M4 ;
        RECT  0 196.176 0.084 196.2 ;
    END
  END q[74]
  PIN q[75]
    DIRECTION OUTPUT ;
    USE SIGNAL ;
    PORT
      LAYER M4 ;
        RECT  0 196.272 0.084 196.296 ;
    END
  END q[75]
  PIN q[76]
    DIRECTION OUTPUT ;
    USE SIGNAL ;
    PORT
      LAYER M4 ;
        RECT  0 196.368 0.084 196.392 ;
    END
  END q[76]
  PIN q[77]
    DIRECTION OUTPUT ;
    USE SIGNAL ;
    PORT
      LAYER M4 ;
        RECT  0 196.464 0.084 196.488 ;
    END
  END q[77]
  PIN q[78]
    DIRECTION OUTPUT ;
    USE SIGNAL ;
    PORT
      LAYER M4 ;
        RECT  0 196.56 0.084 196.584 ;
    END
  END q[78]
  PIN q[79]
    DIRECTION OUTPUT ;
    USE SIGNAL ;
    PORT
      LAYER M4 ;
        RECT  0 196.656 0.084 196.68 ;
    END
  END q[79]
  PIN q[7]
    DIRECTION OUTPUT ;
    USE SIGNAL ;
    PORT
      LAYER M4 ;
        RECT  0 180.528 0.084 180.552 ;
    END
  END q[7]
  PIN q[80]
    DIRECTION OUTPUT ;
    USE SIGNAL ;
    PORT
      LAYER M4 ;
        RECT  0 196.752 0.084 196.776 ;
    END
  END q[80]
  PIN q[81]
    DIRECTION OUTPUT ;
    USE SIGNAL ;
    PORT
      LAYER M4 ;
        RECT  0 196.848 0.084 196.872 ;
    END
  END q[81]
  PIN q[82]
    DIRECTION OUTPUT ;
    USE SIGNAL ;
    PORT
      LAYER M4 ;
        RECT  0 196.944 0.084 196.968 ;
    END
  END q[82]
  PIN q[83]
    DIRECTION OUTPUT ;
    USE SIGNAL ;
    PORT
      LAYER M4 ;
        RECT  0 197.04 0.084 197.064 ;
    END
  END q[83]
  PIN q[84]
    DIRECTION OUTPUT ;
    USE SIGNAL ;
    PORT
      LAYER M4 ;
        RECT  0 197.136 0.084 197.16 ;
    END
  END q[84]
  PIN q[85]
    DIRECTION OUTPUT ;
    USE SIGNAL ;
    PORT
      LAYER M4 ;
        RECT  0 197.232 0.084 197.256 ;
    END
  END q[85]
  PIN q[86]
    DIRECTION OUTPUT ;
    USE SIGNAL ;
    PORT
      LAYER M4 ;
        RECT  0 197.328 0.084 197.352 ;
    END
  END q[86]
  PIN q[87]
    DIRECTION OUTPUT ;
    USE SIGNAL ;
    PORT
      LAYER M4 ;
        RECT  0 197.424 0.084 197.448 ;
    END
  END q[87]
  PIN q[88]
    DIRECTION OUTPUT ;
    USE SIGNAL ;
    PORT
      LAYER M4 ;
        RECT  0 185.232 0.084 185.256 ;
    END
  END q[88]
  PIN q[89]
    DIRECTION OUTPUT ;
    USE SIGNAL ;
    PORT
      LAYER M4 ;
        RECT  0 185.328 0.084 185.352 ;
    END
  END q[89]
  PIN q[8]
    DIRECTION OUTPUT ;
    USE SIGNAL ;
    PORT
      LAYER M4 ;
        RECT  0 180.624 0.084 180.648 ;
    END
  END q[8]
  PIN q[90]
    DIRECTION OUTPUT ;
    USE SIGNAL ;
    PORT
      LAYER M4 ;
        RECT  0 185.424 0.084 185.448 ;
    END
  END q[90]
  PIN q[91]
    DIRECTION OUTPUT ;
    USE SIGNAL ;
    PORT
      LAYER M4 ;
        RECT  0 185.52 0.084 185.544 ;
    END
  END q[91]
  PIN q[92]
    DIRECTION OUTPUT ;
    USE SIGNAL ;
    PORT
      LAYER M4 ;
        RECT  0 185.616 0.084 185.64 ;
    END
  END q[92]
  PIN q[93]
    DIRECTION OUTPUT ;
    USE SIGNAL ;
    PORT
      LAYER M4 ;
        RECT  0 185.712 0.084 185.736 ;
    END
  END q[93]
  PIN q[94]
    DIRECTION OUTPUT ;
    USE SIGNAL ;
    PORT
      LAYER M4 ;
        RECT  0 185.808 0.084 185.832 ;
    END
  END q[94]
  PIN q[95]
    DIRECTION OUTPUT ;
    USE SIGNAL ;
    PORT
      LAYER M4 ;
        RECT  0 185.904 0.084 185.928 ;
    END
  END q[95]
  PIN q[96]
    DIRECTION OUTPUT ;
    USE SIGNAL ;
    PORT
      LAYER M4 ;
        RECT  0 186 0.084 186.024 ;
    END
  END q[96]
  PIN q[97]
    DIRECTION OUTPUT ;
    USE SIGNAL ;
    PORT
      LAYER M4 ;
        RECT  0 186.096 0.084 186.12 ;
    END
  END q[97]
  PIN q[98]
    DIRECTION OUTPUT ;
    USE SIGNAL ;
    PORT
      LAYER M4 ;
        RECT  0 186.192 0.084 186.216 ;
    END
  END q[98]
  PIN q[99]
    DIRECTION OUTPUT ;
    USE SIGNAL ;
    PORT
      LAYER M4 ;
        RECT  0 186.288 0.084 186.312 ;
    END
  END q[99]
  PIN q[9]
    DIRECTION OUTPUT ;
    USE SIGNAL ;
    PORT
      LAYER M4 ;
        RECT  0 180.72 0.084 180.744 ;
    END
  END q[9]
  PIN rst_n
    DIRECTION INPUT ;
    USE SIGNAL ;
    PORT
      LAYER M5 ;
        RECT  20.112 0 20.136 0.084 ;
    END
  END rst_n
  PIN tw_addr[0]
    DIRECTION INPUT ;
    USE SIGNAL ;
    PORT
      LAYER M5 ;
        RECT  20.208 0 20.232 0.084 ;
    END
  END tw_addr[0]
  PIN tw_addr[10]
    DIRECTION INPUT ;
    USE SIGNAL ;
    PORT
      LAYER M5 ;
        RECT  21.168 0 21.192 0.084 ;
    END
  END tw_addr[10]
  PIN tw_addr[11]
    DIRECTION INPUT ;
    USE SIGNAL ;
    PORT
      LAYER M5 ;
        RECT  21.264 0 21.288 0.084 ;
    END
  END tw_addr[11]
  PIN tw_addr[12]
    DIRECTION INPUT ;
    USE SIGNAL ;
    PORT
      LAYER M5 ;
        RECT  21.36 0 21.384 0.084 ;
    END
  END tw_addr[12]
  PIN tw_addr[13]
    DIRECTION INPUT ;
    USE SIGNAL ;
    PORT
      LAYER M5 ;
        RECT  21.456 0 21.48 0.084 ;
    END
  END tw_addr[13]
  PIN tw_addr[14]
    DIRECTION INPUT ;
    USE SIGNAL ;
    PORT
      LAYER M5 ;
        RECT  21.552 0 21.576 0.084 ;
    END
  END tw_addr[14]
  PIN tw_addr[15]
    DIRECTION INPUT ;
    USE SIGNAL ;
    PORT
      LAYER M5 ;
        RECT  21.648 0 21.672 0.084 ;
    END
  END tw_addr[15]
  PIN tw_addr[16]
    DIRECTION INPUT ;
    USE SIGNAL ;
    PORT
      LAYER M5 ;
        RECT  21.744 0 21.768 0.084 ;
    END
  END tw_addr[16]
  PIN tw_addr[17]
    DIRECTION INPUT ;
    USE SIGNAL ;
    PORT
      LAYER M5 ;
        RECT  21.84 0 21.864 0.084 ;
    END
  END tw_addr[17]
  PIN tw_addr[18]
    DIRECTION INPUT ;
    USE SIGNAL ;
    PORT
      LAYER M5 ;
        RECT  21.936 0 21.96 0.084 ;
    END
  END tw_addr[18]
  PIN tw_addr[19]
    DIRECTION INPUT ;
    USE SIGNAL ;
    PORT
      LAYER M5 ;
        RECT  22.032 0 22.056 0.084 ;
    END
  END tw_addr[19]
  PIN tw_addr[1]
    DIRECTION INPUT ;
    USE SIGNAL ;
    PORT
      LAYER M5 ;
        RECT  20.304 0 20.328 0.084 ;
    END
  END tw_addr[1]
  PIN tw_addr[20]
    DIRECTION INPUT ;
    USE SIGNAL ;
    PORT
      LAYER M5 ;
        RECT  22.128 0 22.152 0.084 ;
    END
  END tw_addr[20]
  PIN tw_addr[21]
    DIRECTION INPUT ;
    USE SIGNAL ;
    PORT
      LAYER M5 ;
        RECT  22.224 0 22.248 0.084 ;
    END
  END tw_addr[21]
  PIN tw_addr[22]
    DIRECTION INPUT ;
    USE SIGNAL ;
    PORT
      LAYER M5 ;
        RECT  22.32 0 22.344 0.084 ;
    END
  END tw_addr[22]
  PIN tw_addr[23]
    DIRECTION INPUT ;
    USE SIGNAL ;
    PORT
      LAYER M5 ;
        RECT  22.416 0 22.44 0.084 ;
    END
  END tw_addr[23]
  PIN tw_addr[2]
    DIRECTION INPUT ;
    USE SIGNAL ;
    PORT
      LAYER M5 ;
        RECT  20.4 0 20.424 0.084 ;
    END
  END tw_addr[2]
  PIN tw_addr[3]
    DIRECTION INPUT ;
    USE SIGNAL ;
    PORT
      LAYER M5 ;
        RECT  20.496 0 20.52 0.084 ;
    END
  END tw_addr[3]
  PIN tw_addr[4]
    DIRECTION INPUT ;
    USE SIGNAL ;
    PORT
      LAYER M5 ;
        RECT  20.592 0 20.616 0.084 ;
    END
  END tw_addr[4]
  PIN tw_addr[5]
    DIRECTION INPUT ;
    USE SIGNAL ;
    PORT
      LAYER M5 ;
        RECT  20.688 0 20.712 0.084 ;
    END
  END tw_addr[5]
  PIN tw_addr[6]
    DIRECTION INPUT ;
    USE SIGNAL ;
    PORT
      LAYER M5 ;
        RECT  20.784 0 20.808 0.084 ;
    END
  END tw_addr[6]
  PIN tw_addr[7]
    DIRECTION INPUT ;
    USE SIGNAL ;
    PORT
      LAYER M5 ;
        RECT  20.88 0 20.904 0.084 ;
    END
  END tw_addr[7]
  PIN tw_addr[8]
    DIRECTION INPUT ;
    USE SIGNAL ;
    PORT
      LAYER M5 ;
        RECT  20.976 0 21 0.084 ;
    END
  END tw_addr[8]
  PIN tw_addr[9]
    DIRECTION INPUT ;
    USE SIGNAL ;
    PORT
      LAYER M5 ;
        RECT  21.072 0 21.096 0.084 ;
    END
  END tw_addr[9]
  PIN tw_d[0]
    DIRECTION INPUT ;
    USE SIGNAL ;
    PORT
      LAYER M5 ;
        RECT  22.512 0 22.536 0.084 ;
    END
  END tw_d[0]
  PIN tw_d[100]
    DIRECTION INPUT ;
    USE SIGNAL ;
    PORT
      LAYER M5 ;
        RECT  29.04 0 29.064 0.084 ;
    END
  END tw_d[100]
  PIN tw_d[101]
    DIRECTION INPUT ;
    USE SIGNAL ;
    PORT
      LAYER M5 ;
        RECT  35.28 0 35.304 0.084 ;
    END
  END tw_d[101]
  PIN tw_d[102]
    DIRECTION INPUT ;
    USE SIGNAL ;
    PORT
      LAYER M5 ;
        RECT  35.376 0 35.4 0.084 ;
    END
  END tw_d[102]
  PIN tw_d[103]
    DIRECTION INPUT ;
    USE SIGNAL ;
    PORT
      LAYER M5 ;
        RECT  35.472 0 35.496 0.084 ;
    END
  END tw_d[103]
  PIN tw_d[104]
    DIRECTION INPUT ;
    USE SIGNAL ;
    PORT
      LAYER M5 ;
        RECT  35.568 0 35.592 0.084 ;
    END
  END tw_d[104]
  PIN tw_d[105]
    DIRECTION INPUT ;
    USE SIGNAL ;
    PORT
      LAYER M5 ;
        RECT  35.664 0 35.688 0.084 ;
    END
  END tw_d[105]
  PIN tw_d[106]
    DIRECTION INPUT ;
    USE SIGNAL ;
    PORT
      LAYER M5 ;
        RECT  35.76 0 35.784 0.084 ;
    END
  END tw_d[106]
  PIN tw_d[107]
    DIRECTION INPUT ;
    USE SIGNAL ;
    PORT
      LAYER M5 ;
        RECT  35.856 0 35.88 0.084 ;
    END
  END tw_d[107]
  PIN tw_d[108]
    DIRECTION INPUT ;
    USE SIGNAL ;
    PORT
      LAYER M5 ;
        RECT  35.952 0 35.976 0.084 ;
    END
  END tw_d[108]
  PIN tw_d[109]
    DIRECTION INPUT ;
    USE SIGNAL ;
    PORT
      LAYER M5 ;
        RECT  36.048 0 36.072 0.084 ;
    END
  END tw_d[109]
  PIN tw_d[10]
    DIRECTION INPUT ;
    USE SIGNAL ;
    PORT
      LAYER M5 ;
        RECT  23.472 0 23.496 0.084 ;
    END
  END tw_d[10]
  PIN tw_d[110]
    DIRECTION INPUT ;
    USE SIGNAL ;
    PORT
      LAYER M5 ;
        RECT  36.144 0 36.168 0.084 ;
    END
  END tw_d[110]
  PIN tw_d[111]
    DIRECTION INPUT ;
    USE SIGNAL ;
    PORT
      LAYER M5 ;
        RECT  36.24 0 36.264 0.084 ;
    END
  END tw_d[111]
  PIN tw_d[112]
    DIRECTION INPUT ;
    USE SIGNAL ;
    PORT
      LAYER M5 ;
        RECT  36.336 0 36.36 0.084 ;
    END
  END tw_d[112]
  PIN tw_d[113]
    DIRECTION INPUT ;
    USE SIGNAL ;
    PORT
      LAYER M5 ;
        RECT  36.432 0 36.456 0.084 ;
    END
  END tw_d[113]
  PIN tw_d[114]
    DIRECTION INPUT ;
    USE SIGNAL ;
    PORT
      LAYER M5 ;
        RECT  36.528 0 36.552 0.084 ;
    END
  END tw_d[114]
  PIN tw_d[115]
    DIRECTION INPUT ;
    USE SIGNAL ;
    PORT
      LAYER M5 ;
        RECT  36.624 0 36.648 0.084 ;
    END
  END tw_d[115]
  PIN tw_d[116]
    DIRECTION INPUT ;
    USE SIGNAL ;
    PORT
      LAYER M5 ;
        RECT  36.72 0 36.744 0.084 ;
    END
  END tw_d[116]
  PIN tw_d[117]
    DIRECTION INPUT ;
    USE SIGNAL ;
    PORT
      LAYER M5 ;
        RECT  36.816 0 36.84 0.084 ;
    END
  END tw_d[117]
  PIN tw_d[118]
    DIRECTION INPUT ;
    USE SIGNAL ;
    PORT
      LAYER M5 ;
        RECT  36.912 0 36.936 0.084 ;
    END
  END tw_d[118]
  PIN tw_d[119]
    DIRECTION INPUT ;
    USE SIGNAL ;
    PORT
      LAYER M5 ;
        RECT  37.008 0 37.032 0.084 ;
    END
  END tw_d[119]
  PIN tw_d[11]
    DIRECTION INPUT ;
    USE SIGNAL ;
    PORT
      LAYER M5 ;
        RECT  23.568 0 23.592 0.084 ;
    END
  END tw_d[11]
  PIN tw_d[120]
    DIRECTION INPUT ;
    USE SIGNAL ;
    PORT
      LAYER M5 ;
        RECT  37.104 0 37.128 0.084 ;
    END
  END tw_d[120]
  PIN tw_d[121]
    DIRECTION INPUT ;
    USE SIGNAL ;
    PORT
      LAYER M5 ;
        RECT  37.2 0 37.224 0.084 ;
    END
  END tw_d[121]
  PIN tw_d[122]
    DIRECTION INPUT ;
    USE SIGNAL ;
    PORT
      LAYER M5 ;
        RECT  37.296 0 37.32 0.084 ;
    END
  END tw_d[122]
  PIN tw_d[123]
    DIRECTION INPUT ;
    USE SIGNAL ;
    PORT
      LAYER M5 ;
        RECT  37.392 0 37.416 0.084 ;
    END
  END tw_d[123]
  PIN tw_d[124]
    DIRECTION INPUT ;
    USE SIGNAL ;
    PORT
      LAYER M5 ;
        RECT  37.488 0 37.512 0.084 ;
    END
  END tw_d[124]
  PIN tw_d[125]
    DIRECTION INPUT ;
    USE SIGNAL ;
    PORT
      LAYER M5 ;
        RECT  37.584 0 37.608 0.084 ;
    END
  END tw_d[125]
  PIN tw_d[126]
    DIRECTION INPUT ;
    USE SIGNAL ;
    PORT
      LAYER M5 ;
        RECT  37.68 0 37.704 0.084 ;
    END
  END tw_d[126]
  PIN tw_d[127]
    DIRECTION INPUT ;
    USE SIGNAL ;
    PORT
      LAYER M5 ;
        RECT  37.776 0 37.8 0.084 ;
    END
  END tw_d[127]
  PIN tw_d[128]
    DIRECTION INPUT ;
    USE SIGNAL ;
    PORT
      LAYER M5 ;
        RECT  37.872 0 37.896 0.084 ;
    END
  END tw_d[128]
  PIN tw_d[129]
    DIRECTION INPUT ;
    USE SIGNAL ;
    PORT
      LAYER M5 ;
        RECT  37.968 0 37.992 0.084 ;
    END
  END tw_d[129]
  PIN tw_d[12]
    DIRECTION INPUT ;
    USE SIGNAL ;
    PORT
      LAYER M5 ;
        RECT  23.664 0 23.688 0.084 ;
    END
  END tw_d[12]
  PIN tw_d[130]
    DIRECTION INPUT ;
    USE SIGNAL ;
    PORT
      LAYER M5 ;
        RECT  38.064 0 38.088 0.084 ;
    END
  END tw_d[130]
  PIN tw_d[131]
    DIRECTION INPUT ;
    USE SIGNAL ;
    PORT
      LAYER M5 ;
        RECT  38.16 0 38.184 0.084 ;
    END
  END tw_d[131]
  PIN tw_d[132]
    DIRECTION INPUT ;
    USE SIGNAL ;
    PORT
      LAYER M5 ;
        RECT  38.256 0 38.28 0.084 ;
    END
  END tw_d[132]
  PIN tw_d[133]
    DIRECTION INPUT ;
    USE SIGNAL ;
    PORT
      LAYER M5 ;
        RECT  211.92 0 211.944 0.084 ;
    END
  END tw_d[133]
  PIN tw_d[134]
    DIRECTION INPUT ;
    USE SIGNAL ;
    PORT
      LAYER M5 ;
        RECT  212.016 0 212.04 0.084 ;
    END
  END tw_d[134]
  PIN tw_d[135]
    DIRECTION INPUT ;
    USE SIGNAL ;
    PORT
      LAYER M5 ;
        RECT  212.112 0 212.136 0.084 ;
    END
  END tw_d[135]
  PIN tw_d[136]
    DIRECTION INPUT ;
    USE SIGNAL ;
    PORT
      LAYER M5 ;
        RECT  212.208 0 212.232 0.084 ;
    END
  END tw_d[136]
  PIN tw_d[137]
    DIRECTION INPUT ;
    USE SIGNAL ;
    PORT
      LAYER M5 ;
        RECT  212.304 0 212.328 0.084 ;
    END
  END tw_d[137]
  PIN tw_d[138]
    DIRECTION INPUT ;
    USE SIGNAL ;
    PORT
      LAYER M5 ;
        RECT  212.4 0 212.424 0.084 ;
    END
  END tw_d[138]
  PIN tw_d[139]
    DIRECTION INPUT ;
    USE SIGNAL ;
    PORT
      LAYER M5 ;
        RECT  212.496 0 212.52 0.084 ;
    END
  END tw_d[139]
  PIN tw_d[13]
    DIRECTION INPUT ;
    USE SIGNAL ;
    PORT
      LAYER M5 ;
        RECT  23.76 0 23.784 0.084 ;
    END
  END tw_d[13]
  PIN tw_d[140]
    DIRECTION INPUT ;
    USE SIGNAL ;
    PORT
      LAYER M5 ;
        RECT  212.592 0 212.616 0.084 ;
    END
  END tw_d[140]
  PIN tw_d[141]
    DIRECTION INPUT ;
    USE SIGNAL ;
    PORT
      LAYER M5 ;
        RECT  212.688 0 212.712 0.084 ;
    END
  END tw_d[141]
  PIN tw_d[142]
    DIRECTION INPUT ;
    USE SIGNAL ;
    PORT
      LAYER M5 ;
        RECT  212.784 0 212.808 0.084 ;
    END
  END tw_d[142]
  PIN tw_d[143]
    DIRECTION INPUT ;
    USE SIGNAL ;
    PORT
      LAYER M5 ;
        RECT  212.88 0 212.904 0.084 ;
    END
  END tw_d[143]
  PIN tw_d[144]
    DIRECTION INPUT ;
    USE SIGNAL ;
    PORT
      LAYER M5 ;
        RECT  212.976 0 213 0.084 ;
    END
  END tw_d[144]
  PIN tw_d[145]
    DIRECTION INPUT ;
    USE SIGNAL ;
    PORT
      LAYER M5 ;
        RECT  213.072 0 213.096 0.084 ;
    END
  END tw_d[145]
  PIN tw_d[146]
    DIRECTION INPUT ;
    USE SIGNAL ;
    PORT
      LAYER M5 ;
        RECT  213.168 0 213.192 0.084 ;
    END
  END tw_d[146]
  PIN tw_d[147]
    DIRECTION INPUT ;
    USE SIGNAL ;
    PORT
      LAYER M5 ;
        RECT  213.264 0 213.288 0.084 ;
    END
  END tw_d[147]
  PIN tw_d[148]
    DIRECTION INPUT ;
    USE SIGNAL ;
    PORT
      LAYER M5 ;
        RECT  213.36 0 213.384 0.084 ;
    END
  END tw_d[148]
  PIN tw_d[149]
    DIRECTION INPUT ;
    USE SIGNAL ;
    PORT
      LAYER M5 ;
        RECT  213.456 0 213.48 0.084 ;
    END
  END tw_d[149]
  PIN tw_d[14]
    DIRECTION INPUT ;
    USE SIGNAL ;
    PORT
      LAYER M5 ;
        RECT  23.856 0 23.88 0.084 ;
    END
  END tw_d[14]
  PIN tw_d[150]
    DIRECTION INPUT ;
    USE SIGNAL ;
    PORT
      LAYER M5 ;
        RECT  213.552 0 213.576 0.084 ;
    END
  END tw_d[150]
  PIN tw_d[151]
    DIRECTION INPUT ;
    USE SIGNAL ;
    PORT
      LAYER M5 ;
        RECT  213.648 0 213.672 0.084 ;
    END
  END tw_d[151]
  PIN tw_d[152]
    DIRECTION INPUT ;
    USE SIGNAL ;
    PORT
      LAYER M5 ;
        RECT  213.744 0 213.768 0.084 ;
    END
  END tw_d[152]
  PIN tw_d[153]
    DIRECTION INPUT ;
    USE SIGNAL ;
    PORT
      LAYER M5 ;
        RECT  213.84 0 213.864 0.084 ;
    END
  END tw_d[153]
  PIN tw_d[154]
    DIRECTION INPUT ;
    USE SIGNAL ;
    PORT
      LAYER M5 ;
        RECT  213.936 0 213.96 0.084 ;
    END
  END tw_d[154]
  PIN tw_d[155]
    DIRECTION INPUT ;
    USE SIGNAL ;
    PORT
      LAYER M5 ;
        RECT  214.032 0 214.056 0.084 ;
    END
  END tw_d[155]
  PIN tw_d[156]
    DIRECTION INPUT ;
    USE SIGNAL ;
    PORT
      LAYER M5 ;
        RECT  214.128 0 214.152 0.084 ;
    END
  END tw_d[156]
  PIN tw_d[157]
    DIRECTION INPUT ;
    USE SIGNAL ;
    PORT
      LAYER M5 ;
        RECT  214.224 0 214.248 0.084 ;
    END
  END tw_d[157]
  PIN tw_d[158]
    DIRECTION INPUT ;
    USE SIGNAL ;
    PORT
      LAYER M5 ;
        RECT  214.32 0 214.344 0.084 ;
    END
  END tw_d[158]
  PIN tw_d[159]
    DIRECTION INPUT ;
    USE SIGNAL ;
    PORT
      LAYER M5 ;
        RECT  214.416 0 214.44 0.084 ;
    END
  END tw_d[159]
  PIN tw_d[15]
    DIRECTION INPUT ;
    USE SIGNAL ;
    PORT
      LAYER M5 ;
        RECT  23.952 0 23.976 0.084 ;
    END
  END tw_d[15]
  PIN tw_d[160]
    DIRECTION INPUT ;
    USE SIGNAL ;
    PORT
      LAYER M5 ;
        RECT  214.512 0 214.536 0.084 ;
    END
  END tw_d[160]
  PIN tw_d[161]
    DIRECTION INPUT ;
    USE SIGNAL ;
    PORT
      LAYER M5 ;
        RECT  214.608 0 214.632 0.084 ;
    END
  END tw_d[161]
  PIN tw_d[162]
    DIRECTION INPUT ;
    USE SIGNAL ;
    PORT
      LAYER M5 ;
        RECT  214.704 0 214.728 0.084 ;
    END
  END tw_d[162]
  PIN tw_d[163]
    DIRECTION INPUT ;
    USE SIGNAL ;
    PORT
      LAYER M5 ;
        RECT  214.8 0 214.824 0.084 ;
    END
  END tw_d[163]
  PIN tw_d[164]
    DIRECTION INPUT ;
    USE SIGNAL ;
    PORT
      LAYER M5 ;
        RECT  214.896 0 214.92 0.084 ;
    END
  END tw_d[164]
  PIN tw_d[165]
    DIRECTION INPUT ;
    USE SIGNAL ;
    PORT
      LAYER M5 ;
        RECT  224.208 0 224.232 0.084 ;
    END
  END tw_d[165]
  PIN tw_d[166]
    DIRECTION INPUT ;
    USE SIGNAL ;
    PORT
      LAYER M5 ;
        RECT  224.304 0 224.328 0.084 ;
    END
  END tw_d[166]
  PIN tw_d[167]
    DIRECTION INPUT ;
    USE SIGNAL ;
    PORT
      LAYER M5 ;
        RECT  224.4 0 224.424 0.084 ;
    END
  END tw_d[167]
  PIN tw_d[168]
    DIRECTION INPUT ;
    USE SIGNAL ;
    PORT
      LAYER M5 ;
        RECT  224.496 0 224.52 0.084 ;
    END
  END tw_d[168]
  PIN tw_d[169]
    DIRECTION INPUT ;
    USE SIGNAL ;
    PORT
      LAYER M5 ;
        RECT  224.592 0 224.616 0.084 ;
    END
  END tw_d[169]
  PIN tw_d[16]
    DIRECTION INPUT ;
    USE SIGNAL ;
    PORT
      LAYER M5 ;
        RECT  24.048 0 24.072 0.084 ;
    END
  END tw_d[16]
  PIN tw_d[170]
    DIRECTION INPUT ;
    USE SIGNAL ;
    PORT
      LAYER M5 ;
        RECT  224.688 0 224.712 0.084 ;
    END
  END tw_d[170]
  PIN tw_d[171]
    DIRECTION INPUT ;
    USE SIGNAL ;
    PORT
      LAYER M5 ;
        RECT  224.784 0 224.808 0.084 ;
    END
  END tw_d[171]
  PIN tw_d[172]
    DIRECTION INPUT ;
    USE SIGNAL ;
    PORT
      LAYER M5 ;
        RECT  224.88 0 224.904 0.084 ;
    END
  END tw_d[172]
  PIN tw_d[173]
    DIRECTION INPUT ;
    USE SIGNAL ;
    PORT
      LAYER M5 ;
        RECT  224.976 0 225 0.084 ;
    END
  END tw_d[173]
  PIN tw_d[174]
    DIRECTION INPUT ;
    USE SIGNAL ;
    PORT
      LAYER M5 ;
        RECT  225.072 0 225.096 0.084 ;
    END
  END tw_d[174]
  PIN tw_d[175]
    DIRECTION INPUT ;
    USE SIGNAL ;
    PORT
      LAYER M5 ;
        RECT  225.168 0 225.192 0.084 ;
    END
  END tw_d[175]
  PIN tw_d[176]
    DIRECTION INPUT ;
    USE SIGNAL ;
    PORT
      LAYER M5 ;
        RECT  225.264 0 225.288 0.084 ;
    END
  END tw_d[176]
  PIN tw_d[177]
    DIRECTION INPUT ;
    USE SIGNAL ;
    PORT
      LAYER M5 ;
        RECT  225.36 0 225.384 0.084 ;
    END
  END tw_d[177]
  PIN tw_d[178]
    DIRECTION INPUT ;
    USE SIGNAL ;
    PORT
      LAYER M5 ;
        RECT  225.456 0 225.48 0.084 ;
    END
  END tw_d[178]
  PIN tw_d[179]
    DIRECTION INPUT ;
    USE SIGNAL ;
    PORT
      LAYER M5 ;
        RECT  225.552 0 225.576 0.084 ;
    END
  END tw_d[179]
  PIN tw_d[17]
    DIRECTION INPUT ;
    USE SIGNAL ;
    PORT
      LAYER M5 ;
        RECT  24.144 0 24.168 0.084 ;
    END
  END tw_d[17]
  PIN tw_d[180]
    DIRECTION INPUT ;
    USE SIGNAL ;
    PORT
      LAYER M5 ;
        RECT  225.648 0 225.672 0.084 ;
    END
  END tw_d[180]
  PIN tw_d[181]
    DIRECTION INPUT ;
    USE SIGNAL ;
    PORT
      LAYER M5 ;
        RECT  225.744 0 225.768 0.084 ;
    END
  END tw_d[181]
  PIN tw_d[182]
    DIRECTION INPUT ;
    USE SIGNAL ;
    PORT
      LAYER M5 ;
        RECT  225.84 0 225.864 0.084 ;
    END
  END tw_d[182]
  PIN tw_d[183]
    DIRECTION INPUT ;
    USE SIGNAL ;
    PORT
      LAYER M5 ;
        RECT  225.936 0 225.96 0.084 ;
    END
  END tw_d[183]
  PIN tw_d[184]
    DIRECTION INPUT ;
    USE SIGNAL ;
    PORT
      LAYER M5 ;
        RECT  226.032 0 226.056 0.084 ;
    END
  END tw_d[184]
  PIN tw_d[185]
    DIRECTION INPUT ;
    USE SIGNAL ;
    PORT
      LAYER M5 ;
        RECT  226.128 0 226.152 0.084 ;
    END
  END tw_d[185]
  PIN tw_d[186]
    DIRECTION INPUT ;
    USE SIGNAL ;
    PORT
      LAYER M5 ;
        RECT  226.224 0 226.248 0.084 ;
    END
  END tw_d[186]
  PIN tw_d[187]
    DIRECTION INPUT ;
    USE SIGNAL ;
    PORT
      LAYER M5 ;
        RECT  226.32 0 226.344 0.084 ;
    END
  END tw_d[187]
  PIN tw_d[188]
    DIRECTION INPUT ;
    USE SIGNAL ;
    PORT
      LAYER M5 ;
        RECT  226.416 0 226.44 0.084 ;
    END
  END tw_d[188]
  PIN tw_d[189]
    DIRECTION INPUT ;
    USE SIGNAL ;
    PORT
      LAYER M5 ;
        RECT  226.512 0 226.536 0.084 ;
    END
  END tw_d[189]
  PIN tw_d[18]
    DIRECTION INPUT ;
    USE SIGNAL ;
    PORT
      LAYER M5 ;
        RECT  24.24 0 24.264 0.084 ;
    END
  END tw_d[18]
  PIN tw_d[190]
    DIRECTION INPUT ;
    USE SIGNAL ;
    PORT
      LAYER M5 ;
        RECT  226.608 0 226.632 0.084 ;
    END
  END tw_d[190]
  PIN tw_d[191]
    DIRECTION INPUT ;
    USE SIGNAL ;
    PORT
      LAYER M5 ;
        RECT  226.704 0 226.728 0.084 ;
    END
  END tw_d[191]
  PIN tw_d[192]
    DIRECTION INPUT ;
    USE SIGNAL ;
    PORT
      LAYER M5 ;
        RECT  226.8 0 226.824 0.084 ;
    END
  END tw_d[192]
  PIN tw_d[193]
    DIRECTION INPUT ;
    USE SIGNAL ;
    PORT
      LAYER M5 ;
        RECT  226.896 0 226.92 0.084 ;
    END
  END tw_d[193]
  PIN tw_d[194]
    DIRECTION INPUT ;
    USE SIGNAL ;
    PORT
      LAYER M5 ;
        RECT  226.992 0 227.016 0.084 ;
    END
  END tw_d[194]
  PIN tw_d[195]
    DIRECTION INPUT ;
    USE SIGNAL ;
    PORT
      LAYER M5 ;
        RECT  227.088 0 227.112 0.084 ;
    END
  END tw_d[195]
  PIN tw_d[196]
    DIRECTION INPUT ;
    USE SIGNAL ;
    PORT
      LAYER M5 ;
        RECT  227.184 0 227.208 0.084 ;
    END
  END tw_d[196]
  PIN tw_d[197]
    DIRECTION INPUT ;
    USE SIGNAL ;
    PORT
      LAYER M5 ;
        RECT  227.28 0 227.304 0.084 ;
    END
  END tw_d[197]
  PIN tw_d[198]
    DIRECTION INPUT ;
    USE SIGNAL ;
    PORT
      LAYER M5 ;
        RECT  227.376 0 227.4 0.084 ;
    END
  END tw_d[198]
  PIN tw_d[199]
    DIRECTION INPUT ;
    USE SIGNAL ;
    PORT
      LAYER M5 ;
        RECT  227.472 0 227.496 0.084 ;
    END
  END tw_d[199]
  PIN tw_d[19]
    DIRECTION INPUT ;
    USE SIGNAL ;
    PORT
      LAYER M5 ;
        RECT  24.336 0 24.36 0.084 ;
    END
  END tw_d[19]
  PIN tw_d[1]
    DIRECTION INPUT ;
    USE SIGNAL ;
    PORT
      LAYER M5 ;
        RECT  22.608 0 22.632 0.084 ;
    END
  END tw_d[1]
  PIN tw_d[200]
    DIRECTION INPUT ;
    USE SIGNAL ;
    PORT
      LAYER M5 ;
        RECT  227.568 0 227.592 0.084 ;
    END
  END tw_d[200]
  PIN tw_d[201]
    DIRECTION INPUT ;
    USE SIGNAL ;
    PORT
      LAYER M5 ;
        RECT  227.664 0 227.688 0.084 ;
    END
  END tw_d[201]
  PIN tw_d[202]
    DIRECTION INPUT ;
    USE SIGNAL ;
    PORT
      LAYER M5 ;
        RECT  227.76 0 227.784 0.084 ;
    END
  END tw_d[202]
  PIN tw_d[203]
    DIRECTION INPUT ;
    USE SIGNAL ;
    PORT
      LAYER M5 ;
        RECT  227.856 0 227.88 0.084 ;
    END
  END tw_d[203]
  PIN tw_d[204]
    DIRECTION INPUT ;
    USE SIGNAL ;
    PORT
      LAYER M5 ;
        RECT  227.952 0 227.976 0.084 ;
    END
  END tw_d[204]
  PIN tw_d[205]
    DIRECTION INPUT ;
    USE SIGNAL ;
    PORT
      LAYER M5 ;
        RECT  228.048 0 228.072 0.084 ;
    END
  END tw_d[205]
  PIN tw_d[206]
    DIRECTION INPUT ;
    USE SIGNAL ;
    PORT
      LAYER M5 ;
        RECT  228.144 0 228.168 0.084 ;
    END
  END tw_d[206]
  PIN tw_d[207]
    DIRECTION INPUT ;
    USE SIGNAL ;
    PORT
      LAYER M5 ;
        RECT  228.24 0 228.264 0.084 ;
    END
  END tw_d[207]
  PIN tw_d[208]
    DIRECTION INPUT ;
    USE SIGNAL ;
    PORT
      LAYER M5 ;
        RECT  228.336 0 228.36 0.084 ;
    END
  END tw_d[208]
  PIN tw_d[209]
    DIRECTION INPUT ;
    USE SIGNAL ;
    PORT
      LAYER M5 ;
        RECT  228.432 0 228.456 0.084 ;
    END
  END tw_d[209]
  PIN tw_d[20]
    DIRECTION INPUT ;
    USE SIGNAL ;
    PORT
      LAYER M5 ;
        RECT  24.432 0 24.456 0.084 ;
    END
  END tw_d[20]
  PIN tw_d[210]
    DIRECTION INPUT ;
    USE SIGNAL ;
    PORT
      LAYER M5 ;
        RECT  228.528 0 228.552 0.084 ;
    END
  END tw_d[210]
  PIN tw_d[211]
    DIRECTION INPUT ;
    USE SIGNAL ;
    PORT
      LAYER M5 ;
        RECT  228.624 0 228.648 0.084 ;
    END
  END tw_d[211]
  PIN tw_d[212]
    DIRECTION INPUT ;
    USE SIGNAL ;
    PORT
      LAYER M5 ;
        RECT  228.72 0 228.744 0.084 ;
    END
  END tw_d[212]
  PIN tw_d[213]
    DIRECTION INPUT ;
    USE SIGNAL ;
    PORT
      LAYER M5 ;
        RECT  228.816 0 228.84 0.084 ;
    END
  END tw_d[213]
  PIN tw_d[214]
    DIRECTION INPUT ;
    USE SIGNAL ;
    PORT
      LAYER M5 ;
        RECT  228.912 0 228.936 0.084 ;
    END
  END tw_d[214]
  PIN tw_d[215]
    DIRECTION INPUT ;
    USE SIGNAL ;
    PORT
      LAYER M5 ;
        RECT  229.008 0 229.032 0.084 ;
    END
  END tw_d[215]
  PIN tw_d[216]
    DIRECTION INPUT ;
    USE SIGNAL ;
    PORT
      LAYER M5 ;
        RECT  229.104 0 229.128 0.084 ;
    END
  END tw_d[216]
  PIN tw_d[217]
    DIRECTION INPUT ;
    USE SIGNAL ;
    PORT
      LAYER M5 ;
        RECT  229.2 0 229.224 0.084 ;
    END
  END tw_d[217]
  PIN tw_d[218]
    DIRECTION INPUT ;
    USE SIGNAL ;
    PORT
      LAYER M5 ;
        RECT  229.296 0 229.32 0.084 ;
    END
  END tw_d[218]
  PIN tw_d[219]
    DIRECTION INPUT ;
    USE SIGNAL ;
    PORT
      LAYER M5 ;
        RECT  229.392 0 229.416 0.084 ;
    END
  END tw_d[219]
  PIN tw_d[21]
    DIRECTION INPUT ;
    USE SIGNAL ;
    PORT
      LAYER M5 ;
        RECT  24.528 0 24.552 0.084 ;
    END
  END tw_d[21]
  PIN tw_d[220]
    DIRECTION INPUT ;
    USE SIGNAL ;
    PORT
      LAYER M5 ;
        RECT  229.488 0 229.512 0.084 ;
    END
  END tw_d[220]
  PIN tw_d[221]
    DIRECTION INPUT ;
    USE SIGNAL ;
    PORT
      LAYER M5 ;
        RECT  229.584 0 229.608 0.084 ;
    END
  END tw_d[221]
  PIN tw_d[222]
    DIRECTION INPUT ;
    USE SIGNAL ;
    PORT
      LAYER M5 ;
        RECT  229.68 0 229.704 0.084 ;
    END
  END tw_d[222]
  PIN tw_d[223]
    DIRECTION INPUT ;
    USE SIGNAL ;
    PORT
      LAYER M5 ;
        RECT  229.776 0 229.8 0.084 ;
    END
  END tw_d[223]
  PIN tw_d[224]
    DIRECTION INPUT ;
    USE SIGNAL ;
    PORT
      LAYER M5 ;
        RECT  229.872 0 229.896 0.084 ;
    END
  END tw_d[224]
  PIN tw_d[225]
    DIRECTION INPUT ;
    USE SIGNAL ;
    PORT
      LAYER M5 ;
        RECT  229.968 0 229.992 0.084 ;
    END
  END tw_d[225]
  PIN tw_d[226]
    DIRECTION INPUT ;
    USE SIGNAL ;
    PORT
      LAYER M5 ;
        RECT  230.064 0 230.088 0.084 ;
    END
  END tw_d[226]
  PIN tw_d[227]
    DIRECTION INPUT ;
    USE SIGNAL ;
    PORT
      LAYER M5 ;
        RECT  230.16 0 230.184 0.084 ;
    END
  END tw_d[227]
  PIN tw_d[228]
    DIRECTION INPUT ;
    USE SIGNAL ;
    PORT
      LAYER M5 ;
        RECT  230.256 0 230.28 0.084 ;
    END
  END tw_d[228]
  PIN tw_d[229]
    DIRECTION INPUT ;
    USE SIGNAL ;
    PORT
      LAYER M5 ;
        RECT  218.064 0 218.088 0.084 ;
    END
  END tw_d[229]
  PIN tw_d[22]
    DIRECTION INPUT ;
    USE SIGNAL ;
    PORT
      LAYER M5 ;
        RECT  24.624 0 24.648 0.084 ;
    END
  END tw_d[22]
  PIN tw_d[230]
    DIRECTION INPUT ;
    USE SIGNAL ;
    PORT
      LAYER M5 ;
        RECT  218.16 0 218.184 0.084 ;
    END
  END tw_d[230]
  PIN tw_d[231]
    DIRECTION INPUT ;
    USE SIGNAL ;
    PORT
      LAYER M5 ;
        RECT  218.256 0 218.28 0.084 ;
    END
  END tw_d[231]
  PIN tw_d[232]
    DIRECTION INPUT ;
    USE SIGNAL ;
    PORT
      LAYER M5 ;
        RECT  218.352 0 218.376 0.084 ;
    END
  END tw_d[232]
  PIN tw_d[233]
    DIRECTION INPUT ;
    USE SIGNAL ;
    PORT
      LAYER M5 ;
        RECT  218.448 0 218.472 0.084 ;
    END
  END tw_d[233]
  PIN tw_d[234]
    DIRECTION INPUT ;
    USE SIGNAL ;
    PORT
      LAYER M5 ;
        RECT  218.544 0 218.568 0.084 ;
    END
  END tw_d[234]
  PIN tw_d[235]
    DIRECTION INPUT ;
    USE SIGNAL ;
    PORT
      LAYER M5 ;
        RECT  218.64 0 218.664 0.084 ;
    END
  END tw_d[235]
  PIN tw_d[236]
    DIRECTION INPUT ;
    USE SIGNAL ;
    PORT
      LAYER M5 ;
        RECT  218.736 0 218.76 0.084 ;
    END
  END tw_d[236]
  PIN tw_d[237]
    DIRECTION INPUT ;
    USE SIGNAL ;
    PORT
      LAYER M5 ;
        RECT  218.832 0 218.856 0.084 ;
    END
  END tw_d[237]
  PIN tw_d[238]
    DIRECTION INPUT ;
    USE SIGNAL ;
    PORT
      LAYER M5 ;
        RECT  218.928 0 218.952 0.084 ;
    END
  END tw_d[238]
  PIN tw_d[239]
    DIRECTION INPUT ;
    USE SIGNAL ;
    PORT
      LAYER M5 ;
        RECT  219.024 0 219.048 0.084 ;
    END
  END tw_d[239]
  PIN tw_d[23]
    DIRECTION INPUT ;
    USE SIGNAL ;
    PORT
      LAYER M5 ;
        RECT  24.72 0 24.744 0.084 ;
    END
  END tw_d[23]
  PIN tw_d[240]
    DIRECTION INPUT ;
    USE SIGNAL ;
    PORT
      LAYER M5 ;
        RECT  219.12 0 219.144 0.084 ;
    END
  END tw_d[240]
  PIN tw_d[241]
    DIRECTION INPUT ;
    USE SIGNAL ;
    PORT
      LAYER M5 ;
        RECT  219.216 0 219.24 0.084 ;
    END
  END tw_d[241]
  PIN tw_d[242]
    DIRECTION INPUT ;
    USE SIGNAL ;
    PORT
      LAYER M5 ;
        RECT  219.312 0 219.336 0.084 ;
    END
  END tw_d[242]
  PIN tw_d[243]
    DIRECTION INPUT ;
    USE SIGNAL ;
    PORT
      LAYER M5 ;
        RECT  219.408 0 219.432 0.084 ;
    END
  END tw_d[243]
  PIN tw_d[244]
    DIRECTION INPUT ;
    USE SIGNAL ;
    PORT
      LAYER M5 ;
        RECT  219.504 0 219.528 0.084 ;
    END
  END tw_d[244]
  PIN tw_d[245]
    DIRECTION INPUT ;
    USE SIGNAL ;
    PORT
      LAYER M5 ;
        RECT  219.6 0 219.624 0.084 ;
    END
  END tw_d[245]
  PIN tw_d[246]
    DIRECTION INPUT ;
    USE SIGNAL ;
    PORT
      LAYER M5 ;
        RECT  219.696 0 219.72 0.084 ;
    END
  END tw_d[246]
  PIN tw_d[247]
    DIRECTION INPUT ;
    USE SIGNAL ;
    PORT
      LAYER M5 ;
        RECT  219.792 0 219.816 0.084 ;
    END
  END tw_d[247]
  PIN tw_d[248]
    DIRECTION INPUT ;
    USE SIGNAL ;
    PORT
      LAYER M5 ;
        RECT  219.888 0 219.912 0.084 ;
    END
  END tw_d[248]
  PIN tw_d[249]
    DIRECTION INPUT ;
    USE SIGNAL ;
    PORT
      LAYER M5 ;
        RECT  219.984 0 220.008 0.084 ;
    END
  END tw_d[249]
  PIN tw_d[24]
    DIRECTION INPUT ;
    USE SIGNAL ;
    PORT
      LAYER M5 ;
        RECT  24.816 0 24.84 0.084 ;
    END
  END tw_d[24]
  PIN tw_d[250]
    DIRECTION INPUT ;
    USE SIGNAL ;
    PORT
      LAYER M5 ;
        RECT  220.08 0 220.104 0.084 ;
    END
  END tw_d[250]
  PIN tw_d[251]
    DIRECTION INPUT ;
    USE SIGNAL ;
    PORT
      LAYER M5 ;
        RECT  220.176 0 220.2 0.084 ;
    END
  END tw_d[251]
  PIN tw_d[252]
    DIRECTION INPUT ;
    USE SIGNAL ;
    PORT
      LAYER M5 ;
        RECT  220.272 0 220.296 0.084 ;
    END
  END tw_d[252]
  PIN tw_d[253]
    DIRECTION INPUT ;
    USE SIGNAL ;
    PORT
      LAYER M5 ;
        RECT  220.368 0 220.392 0.084 ;
    END
  END tw_d[253]
  PIN tw_d[254]
    DIRECTION INPUT ;
    USE SIGNAL ;
    PORT
      LAYER M5 ;
        RECT  220.464 0 220.488 0.084 ;
    END
  END tw_d[254]
  PIN tw_d[255]
    DIRECTION INPUT ;
    USE SIGNAL ;
    PORT
      LAYER M5 ;
        RECT  220.56 0 220.584 0.084 ;
    END
  END tw_d[255]
  PIN tw_d[256]
    DIRECTION INPUT ;
    USE SIGNAL ;
    PORT
      LAYER M5 ;
        RECT  220.656 0 220.68 0.084 ;
    END
  END tw_d[256]
  PIN tw_d[257]
    DIRECTION INPUT ;
    USE SIGNAL ;
    PORT
      LAYER M5 ;
        RECT  220.752 0 220.776 0.084 ;
    END
  END tw_d[257]
  PIN tw_d[258]
    DIRECTION INPUT ;
    USE SIGNAL ;
    PORT
      LAYER M5 ;
        RECT  220.848 0 220.872 0.084 ;
    END
  END tw_d[258]
  PIN tw_d[259]
    DIRECTION INPUT ;
    USE SIGNAL ;
    PORT
      LAYER M5 ;
        RECT  220.944 0 220.968 0.084 ;
    END
  END tw_d[259]
  PIN tw_d[25]
    DIRECTION INPUT ;
    USE SIGNAL ;
    PORT
      LAYER M5 ;
        RECT  24.912 0 24.936 0.084 ;
    END
  END tw_d[25]
  PIN tw_d[260]
    DIRECTION INPUT ;
    USE SIGNAL ;
    PORT
      LAYER M5 ;
        RECT  221.04 0 221.064 0.084 ;
    END
  END tw_d[260]
  PIN tw_d[261]
    DIRECTION INPUT ;
    USE SIGNAL ;
    PORT
      LAYER M5 ;
        RECT  32.208 0 32.232 0.084 ;
    END
  END tw_d[261]
  PIN tw_d[262]
    DIRECTION INPUT ;
    USE SIGNAL ;
    PORT
      LAYER M5 ;
        RECT  32.304 0 32.328 0.084 ;
    END
  END tw_d[262]
  PIN tw_d[263]
    DIRECTION INPUT ;
    USE SIGNAL ;
    PORT
      LAYER M5 ;
        RECT  32.4 0 32.424 0.084 ;
    END
  END tw_d[263]
  PIN tw_d[264]
    DIRECTION INPUT ;
    USE SIGNAL ;
    PORT
      LAYER M5 ;
        RECT  32.496 0 32.52 0.084 ;
    END
  END tw_d[264]
  PIN tw_d[265]
    DIRECTION INPUT ;
    USE SIGNAL ;
    PORT
      LAYER M5 ;
        RECT  32.592 0 32.616 0.084 ;
    END
  END tw_d[265]
  PIN tw_d[266]
    DIRECTION INPUT ;
    USE SIGNAL ;
    PORT
      LAYER M5 ;
        RECT  32.688 0 32.712 0.084 ;
    END
  END tw_d[266]
  PIN tw_d[267]
    DIRECTION INPUT ;
    USE SIGNAL ;
    PORT
      LAYER M5 ;
        RECT  32.784 0 32.808 0.084 ;
    END
  END tw_d[267]
  PIN tw_d[268]
    DIRECTION INPUT ;
    USE SIGNAL ;
    PORT
      LAYER M5 ;
        RECT  32.88 0 32.904 0.084 ;
    END
  END tw_d[268]
  PIN tw_d[269]
    DIRECTION INPUT ;
    USE SIGNAL ;
    PORT
      LAYER M5 ;
        RECT  32.976 0 33 0.084 ;
    END
  END tw_d[269]
  PIN tw_d[26]
    DIRECTION INPUT ;
    USE SIGNAL ;
    PORT
      LAYER M5 ;
        RECT  25.008 0 25.032 0.084 ;
    END
  END tw_d[26]
  PIN tw_d[270]
    DIRECTION INPUT ;
    USE SIGNAL ;
    PORT
      LAYER M5 ;
        RECT  33.072 0 33.096 0.084 ;
    END
  END tw_d[270]
  PIN tw_d[271]
    DIRECTION INPUT ;
    USE SIGNAL ;
    PORT
      LAYER M5 ;
        RECT  33.168 0 33.192 0.084 ;
    END
  END tw_d[271]
  PIN tw_d[272]
    DIRECTION INPUT ;
    USE SIGNAL ;
    PORT
      LAYER M5 ;
        RECT  33.264 0 33.288 0.084 ;
    END
  END tw_d[272]
  PIN tw_d[273]
    DIRECTION INPUT ;
    USE SIGNAL ;
    PORT
      LAYER M5 ;
        RECT  33.36 0 33.384 0.084 ;
    END
  END tw_d[273]
  PIN tw_d[274]
    DIRECTION INPUT ;
    USE SIGNAL ;
    PORT
      LAYER M5 ;
        RECT  33.456 0 33.48 0.084 ;
    END
  END tw_d[274]
  PIN tw_d[275]
    DIRECTION INPUT ;
    USE SIGNAL ;
    PORT
      LAYER M5 ;
        RECT  33.552 0 33.576 0.084 ;
    END
  END tw_d[275]
  PIN tw_d[276]
    DIRECTION INPUT ;
    USE SIGNAL ;
    PORT
      LAYER M5 ;
        RECT  33.648 0 33.672 0.084 ;
    END
  END tw_d[276]
  PIN tw_d[277]
    DIRECTION INPUT ;
    USE SIGNAL ;
    PORT
      LAYER M5 ;
        RECT  33.744 0 33.768 0.084 ;
    END
  END tw_d[277]
  PIN tw_d[278]
    DIRECTION INPUT ;
    USE SIGNAL ;
    PORT
      LAYER M5 ;
        RECT  33.84 0 33.864 0.084 ;
    END
  END tw_d[278]
  PIN tw_d[279]
    DIRECTION INPUT ;
    USE SIGNAL ;
    PORT
      LAYER M5 ;
        RECT  33.936 0 33.96 0.084 ;
    END
  END tw_d[279]
  PIN tw_d[27]
    DIRECTION INPUT ;
    USE SIGNAL ;
    PORT
      LAYER M5 ;
        RECT  25.104 0 25.128 0.084 ;
    END
  END tw_d[27]
  PIN tw_d[280]
    DIRECTION INPUT ;
    USE SIGNAL ;
    PORT
      LAYER M5 ;
        RECT  34.032 0 34.056 0.084 ;
    END
  END tw_d[280]
  PIN tw_d[281]
    DIRECTION INPUT ;
    USE SIGNAL ;
    PORT
      LAYER M5 ;
        RECT  34.128 0 34.152 0.084 ;
    END
  END tw_d[281]
  PIN tw_d[282]
    DIRECTION INPUT ;
    USE SIGNAL ;
    PORT
      LAYER M5 ;
        RECT  34.224 0 34.248 0.084 ;
    END
  END tw_d[282]
  PIN tw_d[283]
    DIRECTION INPUT ;
    USE SIGNAL ;
    PORT
      LAYER M5 ;
        RECT  34.32 0 34.344 0.084 ;
    END
  END tw_d[283]
  PIN tw_d[284]
    DIRECTION INPUT ;
    USE SIGNAL ;
    PORT
      LAYER M5 ;
        RECT  34.416 0 34.44 0.084 ;
    END
  END tw_d[284]
  PIN tw_d[285]
    DIRECTION INPUT ;
    USE SIGNAL ;
    PORT
      LAYER M5 ;
        RECT  34.512 0 34.536 0.084 ;
    END
  END tw_d[285]
  PIN tw_d[286]
    DIRECTION INPUT ;
    USE SIGNAL ;
    PORT
      LAYER M5 ;
        RECT  34.608 0 34.632 0.084 ;
    END
  END tw_d[286]
  PIN tw_d[287]
    DIRECTION INPUT ;
    USE SIGNAL ;
    PORT
      LAYER M5 ;
        RECT  34.704 0 34.728 0.084 ;
    END
  END tw_d[287]
  PIN tw_d[288]
    DIRECTION INPUT ;
    USE SIGNAL ;
    PORT
      LAYER M5 ;
        RECT  34.8 0 34.824 0.084 ;
    END
  END tw_d[288]
  PIN tw_d[289]
    DIRECTION INPUT ;
    USE SIGNAL ;
    PORT
      LAYER M5 ;
        RECT  34.896 0 34.92 0.084 ;
    END
  END tw_d[289]
  PIN tw_d[28]
    DIRECTION INPUT ;
    USE SIGNAL ;
    PORT
      LAYER M5 ;
        RECT  25.2 0 25.224 0.084 ;
    END
  END tw_d[28]
  PIN tw_d[290]
    DIRECTION INPUT ;
    USE SIGNAL ;
    PORT
      LAYER M5 ;
        RECT  34.992 0 35.016 0.084 ;
    END
  END tw_d[290]
  PIN tw_d[291]
    DIRECTION INPUT ;
    USE SIGNAL ;
    PORT
      LAYER M5 ;
        RECT  35.088 0 35.112 0.084 ;
    END
  END tw_d[291]
  PIN tw_d[292]
    DIRECTION INPUT ;
    USE SIGNAL ;
    PORT
      LAYER M5 ;
        RECT  35.184 0 35.208 0.084 ;
    END
  END tw_d[292]
  PIN tw_d[293]
    DIRECTION INPUT ;
    USE SIGNAL ;
    PORT
      LAYER M5 ;
        RECT  42.192 0 42.216 0.084 ;
    END
  END tw_d[293]
  PIN tw_d[294]
    DIRECTION INPUT ;
    USE SIGNAL ;
    PORT
      LAYER M5 ;
        RECT  42.288 0 42.312 0.084 ;
    END
  END tw_d[294]
  PIN tw_d[295]
    DIRECTION INPUT ;
    USE SIGNAL ;
    PORT
      LAYER M5 ;
        RECT  42.384 0 42.408 0.084 ;
    END
  END tw_d[295]
  PIN tw_d[296]
    DIRECTION INPUT ;
    USE SIGNAL ;
    PORT
      LAYER M5 ;
        RECT  42.48 0 42.504 0.084 ;
    END
  END tw_d[296]
  PIN tw_d[297]
    DIRECTION INPUT ;
    USE SIGNAL ;
    PORT
      LAYER M5 ;
        RECT  42.576 0 42.6 0.084 ;
    END
  END tw_d[297]
  PIN tw_d[298]
    DIRECTION INPUT ;
    USE SIGNAL ;
    PORT
      LAYER M5 ;
        RECT  42.672 0 42.696 0.084 ;
    END
  END tw_d[298]
  PIN tw_d[299]
    DIRECTION INPUT ;
    USE SIGNAL ;
    PORT
      LAYER M5 ;
        RECT  42.768 0 42.792 0.084 ;
    END
  END tw_d[299]
  PIN tw_d[29]
    DIRECTION INPUT ;
    USE SIGNAL ;
    PORT
      LAYER M5 ;
        RECT  25.296 0 25.32 0.084 ;
    END
  END tw_d[29]
  PIN tw_d[2]
    DIRECTION INPUT ;
    USE SIGNAL ;
    PORT
      LAYER M5 ;
        RECT  22.704 0 22.728 0.084 ;
    END
  END tw_d[2]
  PIN tw_d[300]
    DIRECTION INPUT ;
    USE SIGNAL ;
    PORT
      LAYER M5 ;
        RECT  42.864 0 42.888 0.084 ;
    END
  END tw_d[300]
  PIN tw_d[301]
    DIRECTION INPUT ;
    USE SIGNAL ;
    PORT
      LAYER M5 ;
        RECT  42.96 0 42.984 0.084 ;
    END
  END tw_d[301]
  PIN tw_d[302]
    DIRECTION INPUT ;
    USE SIGNAL ;
    PORT
      LAYER M5 ;
        RECT  43.056 0 43.08 0.084 ;
    END
  END tw_d[302]
  PIN tw_d[303]
    DIRECTION INPUT ;
    USE SIGNAL ;
    PORT
      LAYER M5 ;
        RECT  43.152 0 43.176 0.084 ;
    END
  END tw_d[303]
  PIN tw_d[304]
    DIRECTION INPUT ;
    USE SIGNAL ;
    PORT
      LAYER M5 ;
        RECT  43.248 0 43.272 0.084 ;
    END
  END tw_d[304]
  PIN tw_d[305]
    DIRECTION INPUT ;
    USE SIGNAL ;
    PORT
      LAYER M5 ;
        RECT  43.344 0 43.368 0.084 ;
    END
  END tw_d[305]
  PIN tw_d[306]
    DIRECTION INPUT ;
    USE SIGNAL ;
    PORT
      LAYER M5 ;
        RECT  43.44 0 43.464 0.084 ;
    END
  END tw_d[306]
  PIN tw_d[307]
    DIRECTION INPUT ;
    USE SIGNAL ;
    PORT
      LAYER M5 ;
        RECT  43.536 0 43.56 0.084 ;
    END
  END tw_d[307]
  PIN tw_d[308]
    DIRECTION INPUT ;
    USE SIGNAL ;
    PORT
      LAYER M5 ;
        RECT  43.632 0 43.656 0.084 ;
    END
  END tw_d[308]
  PIN tw_d[309]
    DIRECTION INPUT ;
    USE SIGNAL ;
    PORT
      LAYER M5 ;
        RECT  43.728 0 43.752 0.084 ;
    END
  END tw_d[309]
  PIN tw_d[30]
    DIRECTION INPUT ;
    USE SIGNAL ;
    PORT
      LAYER M5 ;
        RECT  25.392 0 25.416 0.084 ;
    END
  END tw_d[30]
  PIN tw_d[310]
    DIRECTION INPUT ;
    USE SIGNAL ;
    PORT
      LAYER M5 ;
        RECT  43.824 0 43.848 0.084 ;
    END
  END tw_d[310]
  PIN tw_d[311]
    DIRECTION INPUT ;
    USE SIGNAL ;
    PORT
      LAYER M5 ;
        RECT  43.92 0 43.944 0.084 ;
    END
  END tw_d[311]
  PIN tw_d[312]
    DIRECTION INPUT ;
    USE SIGNAL ;
    PORT
      LAYER M5 ;
        RECT  44.016 0 44.04 0.084 ;
    END
  END tw_d[312]
  PIN tw_d[313]
    DIRECTION INPUT ;
    USE SIGNAL ;
    PORT
      LAYER M5 ;
        RECT  44.112 0 44.136 0.084 ;
    END
  END tw_d[313]
  PIN tw_d[314]
    DIRECTION INPUT ;
    USE SIGNAL ;
    PORT
      LAYER M5 ;
        RECT  44.208 0 44.232 0.084 ;
    END
  END tw_d[314]
  PIN tw_d[315]
    DIRECTION INPUT ;
    USE SIGNAL ;
    PORT
      LAYER M5 ;
        RECT  44.304 0 44.328 0.084 ;
    END
  END tw_d[315]
  PIN tw_d[316]
    DIRECTION INPUT ;
    USE SIGNAL ;
    PORT
      LAYER M5 ;
        RECT  44.4 0 44.424 0.084 ;
    END
  END tw_d[316]
  PIN tw_d[317]
    DIRECTION INPUT ;
    USE SIGNAL ;
    PORT
      LAYER M5 ;
        RECT  44.496 0 44.52 0.084 ;
    END
  END tw_d[317]
  PIN tw_d[318]
    DIRECTION INPUT ;
    USE SIGNAL ;
    PORT
      LAYER M5 ;
        RECT  44.592 0 44.616 0.084 ;
    END
  END tw_d[318]
  PIN tw_d[319]
    DIRECTION INPUT ;
    USE SIGNAL ;
    PORT
      LAYER M5 ;
        RECT  44.688 0 44.712 0.084 ;
    END
  END tw_d[319]
  PIN tw_d[31]
    DIRECTION INPUT ;
    USE SIGNAL ;
    PORT
      LAYER M5 ;
        RECT  25.488 0 25.512 0.084 ;
    END
  END tw_d[31]
  PIN tw_d[320]
    DIRECTION INPUT ;
    USE SIGNAL ;
    PORT
      LAYER M5 ;
        RECT  44.784 0 44.808 0.084 ;
    END
  END tw_d[320]
  PIN tw_d[321]
    DIRECTION INPUT ;
    USE SIGNAL ;
    PORT
      LAYER M5 ;
        RECT  44.88 0 44.904 0.084 ;
    END
  END tw_d[321]
  PIN tw_d[322]
    DIRECTION INPUT ;
    USE SIGNAL ;
    PORT
      LAYER M5 ;
        RECT  44.976 0 45 0.084 ;
    END
  END tw_d[322]
  PIN tw_d[323]
    DIRECTION INPUT ;
    USE SIGNAL ;
    PORT
      LAYER M5 ;
        RECT  45.072 0 45.096 0.084 ;
    END
  END tw_d[323]
  PIN tw_d[324]
    DIRECTION INPUT ;
    USE SIGNAL ;
    PORT
      LAYER M5 ;
        RECT  45.168 0 45.192 0.084 ;
    END
  END tw_d[324]
  PIN tw_d[325]
    DIRECTION INPUT ;
    USE SIGNAL ;
    PORT
      LAYER M5 ;
        RECT  45.264 0 45.288 0.084 ;
    END
  END tw_d[325]
  PIN tw_d[326]
    DIRECTION INPUT ;
    USE SIGNAL ;
    PORT
      LAYER M5 ;
        RECT  45.36 0 45.384 0.084 ;
    END
  END tw_d[326]
  PIN tw_d[327]
    DIRECTION INPUT ;
    USE SIGNAL ;
    PORT
      LAYER M5 ;
        RECT  45.456 0 45.48 0.084 ;
    END
  END tw_d[327]
  PIN tw_d[328]
    DIRECTION INPUT ;
    USE SIGNAL ;
    PORT
      LAYER M5 ;
        RECT  45.552 0 45.576 0.084 ;
    END
  END tw_d[328]
  PIN tw_d[329]
    DIRECTION INPUT ;
    USE SIGNAL ;
    PORT
      LAYER M5 ;
        RECT  45.648 0 45.672 0.084 ;
    END
  END tw_d[329]
  PIN tw_d[32]
    DIRECTION INPUT ;
    USE SIGNAL ;
    PORT
      LAYER M5 ;
        RECT  25.584 0 25.608 0.084 ;
    END
  END tw_d[32]
  PIN tw_d[330]
    DIRECTION INPUT ;
    USE SIGNAL ;
    PORT
      LAYER M5 ;
        RECT  45.744 0 45.768 0.084 ;
    END
  END tw_d[330]
  PIN tw_d[331]
    DIRECTION INPUT ;
    USE SIGNAL ;
    PORT
      LAYER M5 ;
        RECT  45.84 0 45.864 0.084 ;
    END
  END tw_d[331]
  PIN tw_d[332]
    DIRECTION INPUT ;
    USE SIGNAL ;
    PORT
      LAYER M5 ;
        RECT  45.936 0 45.96 0.084 ;
    END
  END tw_d[332]
  PIN tw_d[333]
    DIRECTION INPUT ;
    USE SIGNAL ;
    PORT
      LAYER M5 ;
        RECT  46.032 0 46.056 0.084 ;
    END
  END tw_d[333]
  PIN tw_d[334]
    DIRECTION INPUT ;
    USE SIGNAL ;
    PORT
      LAYER M5 ;
        RECT  46.128 0 46.152 0.084 ;
    END
  END tw_d[334]
  PIN tw_d[335]
    DIRECTION INPUT ;
    USE SIGNAL ;
    PORT
      LAYER M5 ;
        RECT  46.224 0 46.248 0.084 ;
    END
  END tw_d[335]
  PIN tw_d[336]
    DIRECTION INPUT ;
    USE SIGNAL ;
    PORT
      LAYER M5 ;
        RECT  46.32 0 46.344 0.084 ;
    END
  END tw_d[336]
  PIN tw_d[337]
    DIRECTION INPUT ;
    USE SIGNAL ;
    PORT
      LAYER M5 ;
        RECT  46.416 0 46.44 0.084 ;
    END
  END tw_d[337]
  PIN tw_d[338]
    DIRECTION INPUT ;
    USE SIGNAL ;
    PORT
      LAYER M5 ;
        RECT  46.512 0 46.536 0.084 ;
    END
  END tw_d[338]
  PIN tw_d[339]
    DIRECTION INPUT ;
    USE SIGNAL ;
    PORT
      LAYER M5 ;
        RECT  46.608 0 46.632 0.084 ;
    END
  END tw_d[339]
  PIN tw_d[33]
    DIRECTION INPUT ;
    USE SIGNAL ;
    PORT
      LAYER M5 ;
        RECT  25.68 0 25.704 0.084 ;
    END
  END tw_d[33]
  PIN tw_d[340]
    DIRECTION INPUT ;
    USE SIGNAL ;
    PORT
      LAYER M5 ;
        RECT  46.704 0 46.728 0.084 ;
    END
  END tw_d[340]
  PIN tw_d[341]
    DIRECTION INPUT ;
    USE SIGNAL ;
    PORT
      LAYER M5 ;
        RECT  46.8 0 46.824 0.084 ;
    END
  END tw_d[341]
  PIN tw_d[342]
    DIRECTION INPUT ;
    USE SIGNAL ;
    PORT
      LAYER M5 ;
        RECT  46.896 0 46.92 0.084 ;
    END
  END tw_d[342]
  PIN tw_d[343]
    DIRECTION INPUT ;
    USE SIGNAL ;
    PORT
      LAYER M5 ;
        RECT  46.992 0 47.016 0.084 ;
    END
  END tw_d[343]
  PIN tw_d[344]
    DIRECTION INPUT ;
    USE SIGNAL ;
    PORT
      LAYER M5 ;
        RECT  47.088 0 47.112 0.084 ;
    END
  END tw_d[344]
  PIN tw_d[345]
    DIRECTION INPUT ;
    USE SIGNAL ;
    PORT
      LAYER M5 ;
        RECT  47.184 0 47.208 0.084 ;
    END
  END tw_d[345]
  PIN tw_d[346]
    DIRECTION INPUT ;
    USE SIGNAL ;
    PORT
      LAYER M5 ;
        RECT  47.28 0 47.304 0.084 ;
    END
  END tw_d[346]
  PIN tw_d[347]
    DIRECTION INPUT ;
    USE SIGNAL ;
    PORT
      LAYER M5 ;
        RECT  47.376 0 47.4 0.084 ;
    END
  END tw_d[347]
  PIN tw_d[348]
    DIRECTION INPUT ;
    USE SIGNAL ;
    PORT
      LAYER M5 ;
        RECT  47.472 0 47.496 0.084 ;
    END
  END tw_d[348]
  PIN tw_d[349]
    DIRECTION INPUT ;
    USE SIGNAL ;
    PORT
      LAYER M5 ;
        RECT  47.568 0 47.592 0.084 ;
    END
  END tw_d[349]
  PIN tw_d[34]
    DIRECTION INPUT ;
    USE SIGNAL ;
    PORT
      LAYER M5 ;
        RECT  25.776 0 25.8 0.084 ;
    END
  END tw_d[34]
  PIN tw_d[350]
    DIRECTION INPUT ;
    USE SIGNAL ;
    PORT
      LAYER M5 ;
        RECT  47.664 0 47.688 0.084 ;
    END
  END tw_d[350]
  PIN tw_d[351]
    DIRECTION INPUT ;
    USE SIGNAL ;
    PORT
      LAYER M5 ;
        RECT  47.76 0 47.784 0.084 ;
    END
  END tw_d[351]
  PIN tw_d[352]
    DIRECTION INPUT ;
    USE SIGNAL ;
    PORT
      LAYER M5 ;
        RECT  47.856 0 47.88 0.084 ;
    END
  END tw_d[352]
  PIN tw_d[353]
    DIRECTION INPUT ;
    USE SIGNAL ;
    PORT
      LAYER M5 ;
        RECT  47.952 0 47.976 0.084 ;
    END
  END tw_d[353]
  PIN tw_d[354]
    DIRECTION INPUT ;
    USE SIGNAL ;
    PORT
      LAYER M5 ;
        RECT  48.048 0 48.072 0.084 ;
    END
  END tw_d[354]
  PIN tw_d[355]
    DIRECTION INPUT ;
    USE SIGNAL ;
    PORT
      LAYER M5 ;
        RECT  48.144 0 48.168 0.084 ;
    END
  END tw_d[355]
  PIN tw_d[356]
    DIRECTION INPUT ;
    USE SIGNAL ;
    PORT
      LAYER M5 ;
        RECT  48.24 0 48.264 0.084 ;
    END
  END tw_d[356]
  PIN tw_d[357]
    DIRECTION INPUT ;
    USE SIGNAL ;
    PORT
      LAYER M5 ;
        RECT  39.12 0 39.144 0.084 ;
    END
  END tw_d[357]
  PIN tw_d[358]
    DIRECTION INPUT ;
    USE SIGNAL ;
    PORT
      LAYER M5 ;
        RECT  39.216 0 39.24 0.084 ;
    END
  END tw_d[358]
  PIN tw_d[359]
    DIRECTION INPUT ;
    USE SIGNAL ;
    PORT
      LAYER M5 ;
        RECT  39.312 0 39.336 0.084 ;
    END
  END tw_d[359]
  PIN tw_d[35]
    DIRECTION INPUT ;
    USE SIGNAL ;
    PORT
      LAYER M5 ;
        RECT  25.872 0 25.896 0.084 ;
    END
  END tw_d[35]
  PIN tw_d[360]
    DIRECTION INPUT ;
    USE SIGNAL ;
    PORT
      LAYER M5 ;
        RECT  39.408 0 39.432 0.084 ;
    END
  END tw_d[360]
  PIN tw_d[361]
    DIRECTION INPUT ;
    USE SIGNAL ;
    PORT
      LAYER M5 ;
        RECT  39.504 0 39.528 0.084 ;
    END
  END tw_d[361]
  PIN tw_d[362]
    DIRECTION INPUT ;
    USE SIGNAL ;
    PORT
      LAYER M5 ;
        RECT  39.6 0 39.624 0.084 ;
    END
  END tw_d[362]
  PIN tw_d[363]
    DIRECTION INPUT ;
    USE SIGNAL ;
    PORT
      LAYER M5 ;
        RECT  39.696 0 39.72 0.084 ;
    END
  END tw_d[363]
  PIN tw_d[364]
    DIRECTION INPUT ;
    USE SIGNAL ;
    PORT
      LAYER M5 ;
        RECT  39.792 0 39.816 0.084 ;
    END
  END tw_d[364]
  PIN tw_d[365]
    DIRECTION INPUT ;
    USE SIGNAL ;
    PORT
      LAYER M5 ;
        RECT  39.888 0 39.912 0.084 ;
    END
  END tw_d[365]
  PIN tw_d[366]
    DIRECTION INPUT ;
    USE SIGNAL ;
    PORT
      LAYER M5 ;
        RECT  39.984 0 40.008 0.084 ;
    END
  END tw_d[366]
  PIN tw_d[367]
    DIRECTION INPUT ;
    USE SIGNAL ;
    PORT
      LAYER M5 ;
        RECT  40.08 0 40.104 0.084 ;
    END
  END tw_d[367]
  PIN tw_d[368]
    DIRECTION INPUT ;
    USE SIGNAL ;
    PORT
      LAYER M5 ;
        RECT  40.176 0 40.2 0.084 ;
    END
  END tw_d[368]
  PIN tw_d[369]
    DIRECTION INPUT ;
    USE SIGNAL ;
    PORT
      LAYER M5 ;
        RECT  40.272 0 40.296 0.084 ;
    END
  END tw_d[369]
  PIN tw_d[36]
    DIRECTION INPUT ;
    USE SIGNAL ;
    PORT
      LAYER M5 ;
        RECT  25.968 0 25.992 0.084 ;
    END
  END tw_d[36]
  PIN tw_d[370]
    DIRECTION INPUT ;
    USE SIGNAL ;
    PORT
      LAYER M5 ;
        RECT  40.368 0 40.392 0.084 ;
    END
  END tw_d[370]
  PIN tw_d[371]
    DIRECTION INPUT ;
    USE SIGNAL ;
    PORT
      LAYER M5 ;
        RECT  40.464 0 40.488 0.084 ;
    END
  END tw_d[371]
  PIN tw_d[372]
    DIRECTION INPUT ;
    USE SIGNAL ;
    PORT
      LAYER M5 ;
        RECT  40.56 0 40.584 0.084 ;
    END
  END tw_d[372]
  PIN tw_d[373]
    DIRECTION INPUT ;
    USE SIGNAL ;
    PORT
      LAYER M5 ;
        RECT  40.656 0 40.68 0.084 ;
    END
  END tw_d[373]
  PIN tw_d[374]
    DIRECTION INPUT ;
    USE SIGNAL ;
    PORT
      LAYER M5 ;
        RECT  40.752 0 40.776 0.084 ;
    END
  END tw_d[374]
  PIN tw_d[375]
    DIRECTION INPUT ;
    USE SIGNAL ;
    PORT
      LAYER M5 ;
        RECT  40.848 0 40.872 0.084 ;
    END
  END tw_d[375]
  PIN tw_d[376]
    DIRECTION INPUT ;
    USE SIGNAL ;
    PORT
      LAYER M5 ;
        RECT  40.944 0 40.968 0.084 ;
    END
  END tw_d[376]
  PIN tw_d[377]
    DIRECTION INPUT ;
    USE SIGNAL ;
    PORT
      LAYER M5 ;
        RECT  41.04 0 41.064 0.084 ;
    END
  END tw_d[377]
  PIN tw_d[378]
    DIRECTION INPUT ;
    USE SIGNAL ;
    PORT
      LAYER M5 ;
        RECT  41.136 0 41.16 0.084 ;
    END
  END tw_d[378]
  PIN tw_d[379]
    DIRECTION INPUT ;
    USE SIGNAL ;
    PORT
      LAYER M5 ;
        RECT  41.232 0 41.256 0.084 ;
    END
  END tw_d[379]
  PIN tw_d[37]
    DIRECTION INPUT ;
    USE SIGNAL ;
    PORT
      LAYER M5 ;
        RECT  29.136 0 29.16 0.084 ;
    END
  END tw_d[37]
  PIN tw_d[380]
    DIRECTION INPUT ;
    USE SIGNAL ;
    PORT
      LAYER M5 ;
        RECT  41.328 0 41.352 0.084 ;
    END
  END tw_d[380]
  PIN tw_d[381]
    DIRECTION INPUT ;
    USE SIGNAL ;
    PORT
      LAYER M5 ;
        RECT  41.424 0 41.448 0.084 ;
    END
  END tw_d[381]
  PIN tw_d[382]
    DIRECTION INPUT ;
    USE SIGNAL ;
    PORT
      LAYER M5 ;
        RECT  41.52 0 41.544 0.084 ;
    END
  END tw_d[382]
  PIN tw_d[383]
    DIRECTION INPUT ;
    USE SIGNAL ;
    PORT
      LAYER M5 ;
        RECT  41.616 0 41.64 0.084 ;
    END
  END tw_d[383]
  PIN tw_d[384]
    DIRECTION INPUT ;
    USE SIGNAL ;
    PORT
      LAYER M5 ;
        RECT  41.712 0 41.736 0.084 ;
    END
  END tw_d[384]
  PIN tw_d[385]
    DIRECTION INPUT ;
    USE SIGNAL ;
    PORT
      LAYER M5 ;
        RECT  41.808 0 41.832 0.084 ;
    END
  END tw_d[385]
  PIN tw_d[386]
    DIRECTION INPUT ;
    USE SIGNAL ;
    PORT
      LAYER M5 ;
        RECT  41.904 0 41.928 0.084 ;
    END
  END tw_d[386]
  PIN tw_d[387]
    DIRECTION INPUT ;
    USE SIGNAL ;
    PORT
      LAYER M5 ;
        RECT  42 0 42.024 0.084 ;
    END
  END tw_d[387]
  PIN tw_d[388]
    DIRECTION INPUT ;
    USE SIGNAL ;
    PORT
      LAYER M5 ;
        RECT  42.096 0 42.12 0.084 ;
    END
  END tw_d[388]
  PIN tw_d[389]
    DIRECTION INPUT ;
    USE SIGNAL ;
    PORT
      LAYER M5 ;
        RECT  214.992 0 215.016 0.084 ;
    END
  END tw_d[389]
  PIN tw_d[38]
    DIRECTION INPUT ;
    USE SIGNAL ;
    PORT
      LAYER M5 ;
        RECT  29.232 0 29.256 0.084 ;
    END
  END tw_d[38]
  PIN tw_d[390]
    DIRECTION INPUT ;
    USE SIGNAL ;
    PORT
      LAYER M5 ;
        RECT  215.088 0 215.112 0.084 ;
    END
  END tw_d[390]
  PIN tw_d[391]
    DIRECTION INPUT ;
    USE SIGNAL ;
    PORT
      LAYER M5 ;
        RECT  215.184 0 215.208 0.084 ;
    END
  END tw_d[391]
  PIN tw_d[392]
    DIRECTION INPUT ;
    USE SIGNAL ;
    PORT
      LAYER M5 ;
        RECT  215.28 0 215.304 0.084 ;
    END
  END tw_d[392]
  PIN tw_d[393]
    DIRECTION INPUT ;
    USE SIGNAL ;
    PORT
      LAYER M5 ;
        RECT  215.376 0 215.4 0.084 ;
    END
  END tw_d[393]
  PIN tw_d[394]
    DIRECTION INPUT ;
    USE SIGNAL ;
    PORT
      LAYER M5 ;
        RECT  215.472 0 215.496 0.084 ;
    END
  END tw_d[394]
  PIN tw_d[395]
    DIRECTION INPUT ;
    USE SIGNAL ;
    PORT
      LAYER M5 ;
        RECT  215.568 0 215.592 0.084 ;
    END
  END tw_d[395]
  PIN tw_d[396]
    DIRECTION INPUT ;
    USE SIGNAL ;
    PORT
      LAYER M5 ;
        RECT  215.664 0 215.688 0.084 ;
    END
  END tw_d[396]
  PIN tw_d[397]
    DIRECTION INPUT ;
    USE SIGNAL ;
    PORT
      LAYER M5 ;
        RECT  215.76 0 215.784 0.084 ;
    END
  END tw_d[397]
  PIN tw_d[398]
    DIRECTION INPUT ;
    USE SIGNAL ;
    PORT
      LAYER M5 ;
        RECT  215.856 0 215.88 0.084 ;
    END
  END tw_d[398]
  PIN tw_d[399]
    DIRECTION INPUT ;
    USE SIGNAL ;
    PORT
      LAYER M5 ;
        RECT  215.952 0 215.976 0.084 ;
    END
  END tw_d[399]
  PIN tw_d[39]
    DIRECTION INPUT ;
    USE SIGNAL ;
    PORT
      LAYER M5 ;
        RECT  29.328 0 29.352 0.084 ;
    END
  END tw_d[39]
  PIN tw_d[3]
    DIRECTION INPUT ;
    USE SIGNAL ;
    PORT
      LAYER M5 ;
        RECT  22.8 0 22.824 0.084 ;
    END
  END tw_d[3]
  PIN tw_d[400]
    DIRECTION INPUT ;
    USE SIGNAL ;
    PORT
      LAYER M5 ;
        RECT  216.048 0 216.072 0.084 ;
    END
  END tw_d[400]
  PIN tw_d[401]
    DIRECTION INPUT ;
    USE SIGNAL ;
    PORT
      LAYER M5 ;
        RECT  216.144 0 216.168 0.084 ;
    END
  END tw_d[401]
  PIN tw_d[402]
    DIRECTION INPUT ;
    USE SIGNAL ;
    PORT
      LAYER M5 ;
        RECT  216.24 0 216.264 0.084 ;
    END
  END tw_d[402]
  PIN tw_d[403]
    DIRECTION INPUT ;
    USE SIGNAL ;
    PORT
      LAYER M5 ;
        RECT  216.336 0 216.36 0.084 ;
    END
  END tw_d[403]
  PIN tw_d[404]
    DIRECTION INPUT ;
    USE SIGNAL ;
    PORT
      LAYER M5 ;
        RECT  216.432 0 216.456 0.084 ;
    END
  END tw_d[404]
  PIN tw_d[405]
    DIRECTION INPUT ;
    USE SIGNAL ;
    PORT
      LAYER M5 ;
        RECT  216.528 0 216.552 0.084 ;
    END
  END tw_d[405]
  PIN tw_d[406]
    DIRECTION INPUT ;
    USE SIGNAL ;
    PORT
      LAYER M5 ;
        RECT  216.624 0 216.648 0.084 ;
    END
  END tw_d[406]
  PIN tw_d[407]
    DIRECTION INPUT ;
    USE SIGNAL ;
    PORT
      LAYER M5 ;
        RECT  216.72 0 216.744 0.084 ;
    END
  END tw_d[407]
  PIN tw_d[408]
    DIRECTION INPUT ;
    USE SIGNAL ;
    PORT
      LAYER M5 ;
        RECT  216.816 0 216.84 0.084 ;
    END
  END tw_d[408]
  PIN tw_d[409]
    DIRECTION INPUT ;
    USE SIGNAL ;
    PORT
      LAYER M5 ;
        RECT  216.912 0 216.936 0.084 ;
    END
  END tw_d[409]
  PIN tw_d[40]
    DIRECTION INPUT ;
    USE SIGNAL ;
    PORT
      LAYER M5 ;
        RECT  29.424 0 29.448 0.084 ;
    END
  END tw_d[40]
  PIN tw_d[410]
    DIRECTION INPUT ;
    USE SIGNAL ;
    PORT
      LAYER M5 ;
        RECT  217.008 0 217.032 0.084 ;
    END
  END tw_d[410]
  PIN tw_d[411]
    DIRECTION INPUT ;
    USE SIGNAL ;
    PORT
      LAYER M5 ;
        RECT  217.104 0 217.128 0.084 ;
    END
  END tw_d[411]
  PIN tw_d[412]
    DIRECTION INPUT ;
    USE SIGNAL ;
    PORT
      LAYER M5 ;
        RECT  217.2 0 217.224 0.084 ;
    END
  END tw_d[412]
  PIN tw_d[413]
    DIRECTION INPUT ;
    USE SIGNAL ;
    PORT
      LAYER M5 ;
        RECT  217.296 0 217.32 0.084 ;
    END
  END tw_d[413]
  PIN tw_d[414]
    DIRECTION INPUT ;
    USE SIGNAL ;
    PORT
      LAYER M5 ;
        RECT  217.392 0 217.416 0.084 ;
    END
  END tw_d[414]
  PIN tw_d[415]
    DIRECTION INPUT ;
    USE SIGNAL ;
    PORT
      LAYER M5 ;
        RECT  217.488 0 217.512 0.084 ;
    END
  END tw_d[415]
  PIN tw_d[416]
    DIRECTION INPUT ;
    USE SIGNAL ;
    PORT
      LAYER M5 ;
        RECT  217.584 0 217.608 0.084 ;
    END
  END tw_d[416]
  PIN tw_d[417]
    DIRECTION INPUT ;
    USE SIGNAL ;
    PORT
      LAYER M5 ;
        RECT  217.68 0 217.704 0.084 ;
    END
  END tw_d[417]
  PIN tw_d[418]
    DIRECTION INPUT ;
    USE SIGNAL ;
    PORT
      LAYER M5 ;
        RECT  217.776 0 217.8 0.084 ;
    END
  END tw_d[418]
  PIN tw_d[419]
    DIRECTION INPUT ;
    USE SIGNAL ;
    PORT
      LAYER M5 ;
        RECT  217.872 0 217.896 0.084 ;
    END
  END tw_d[419]
  PIN tw_d[41]
    DIRECTION INPUT ;
    USE SIGNAL ;
    PORT
      LAYER M5 ;
        RECT  29.52 0 29.544 0.084 ;
    END
  END tw_d[41]
  PIN tw_d[420]
    DIRECTION INPUT ;
    USE SIGNAL ;
    PORT
      LAYER M5 ;
        RECT  217.968 0 217.992 0.084 ;
    END
  END tw_d[420]
  PIN tw_d[421]
    DIRECTION INPUT ;
    USE SIGNAL ;
    PORT
      LAYER M5 ;
        RECT  221.136 0 221.16 0.084 ;
    END
  END tw_d[421]
  PIN tw_d[422]
    DIRECTION INPUT ;
    USE SIGNAL ;
    PORT
      LAYER M5 ;
        RECT  221.232 0 221.256 0.084 ;
    END
  END tw_d[422]
  PIN tw_d[423]
    DIRECTION INPUT ;
    USE SIGNAL ;
    PORT
      LAYER M5 ;
        RECT  221.328 0 221.352 0.084 ;
    END
  END tw_d[423]
  PIN tw_d[424]
    DIRECTION INPUT ;
    USE SIGNAL ;
    PORT
      LAYER M5 ;
        RECT  221.424 0 221.448 0.084 ;
    END
  END tw_d[424]
  PIN tw_d[425]
    DIRECTION INPUT ;
    USE SIGNAL ;
    PORT
      LAYER M5 ;
        RECT  221.52 0 221.544 0.084 ;
    END
  END tw_d[425]
  PIN tw_d[426]
    DIRECTION INPUT ;
    USE SIGNAL ;
    PORT
      LAYER M5 ;
        RECT  221.616 0 221.64 0.084 ;
    END
  END tw_d[426]
  PIN tw_d[427]
    DIRECTION INPUT ;
    USE SIGNAL ;
    PORT
      LAYER M5 ;
        RECT  221.712 0 221.736 0.084 ;
    END
  END tw_d[427]
  PIN tw_d[428]
    DIRECTION INPUT ;
    USE SIGNAL ;
    PORT
      LAYER M5 ;
        RECT  221.808 0 221.832 0.084 ;
    END
  END tw_d[428]
  PIN tw_d[429]
    DIRECTION INPUT ;
    USE SIGNAL ;
    PORT
      LAYER M5 ;
        RECT  221.904 0 221.928 0.084 ;
    END
  END tw_d[429]
  PIN tw_d[42]
    DIRECTION INPUT ;
    USE SIGNAL ;
    PORT
      LAYER M5 ;
        RECT  29.616 0 29.64 0.084 ;
    END
  END tw_d[42]
  PIN tw_d[430]
    DIRECTION INPUT ;
    USE SIGNAL ;
    PORT
      LAYER M5 ;
        RECT  222 0 222.024 0.084 ;
    END
  END tw_d[430]
  PIN tw_d[431]
    DIRECTION INPUT ;
    USE SIGNAL ;
    PORT
      LAYER M5 ;
        RECT  222.096 0 222.12 0.084 ;
    END
  END tw_d[431]
  PIN tw_d[432]
    DIRECTION INPUT ;
    USE SIGNAL ;
    PORT
      LAYER M5 ;
        RECT  222.192 0 222.216 0.084 ;
    END
  END tw_d[432]
  PIN tw_d[433]
    DIRECTION INPUT ;
    USE SIGNAL ;
    PORT
      LAYER M5 ;
        RECT  222.288 0 222.312 0.084 ;
    END
  END tw_d[433]
  PIN tw_d[434]
    DIRECTION INPUT ;
    USE SIGNAL ;
    PORT
      LAYER M5 ;
        RECT  222.384 0 222.408 0.084 ;
    END
  END tw_d[434]
  PIN tw_d[435]
    DIRECTION INPUT ;
    USE SIGNAL ;
    PORT
      LAYER M5 ;
        RECT  222.48 0 222.504 0.084 ;
    END
  END tw_d[435]
  PIN tw_d[436]
    DIRECTION INPUT ;
    USE SIGNAL ;
    PORT
      LAYER M5 ;
        RECT  222.576 0 222.6 0.084 ;
    END
  END tw_d[436]
  PIN tw_d[437]
    DIRECTION INPUT ;
    USE SIGNAL ;
    PORT
      LAYER M5 ;
        RECT  222.672 0 222.696 0.084 ;
    END
  END tw_d[437]
  PIN tw_d[438]
    DIRECTION INPUT ;
    USE SIGNAL ;
    PORT
      LAYER M5 ;
        RECT  222.768 0 222.792 0.084 ;
    END
  END tw_d[438]
  PIN tw_d[439]
    DIRECTION INPUT ;
    USE SIGNAL ;
    PORT
      LAYER M5 ;
        RECT  222.864 0 222.888 0.084 ;
    END
  END tw_d[439]
  PIN tw_d[43]
    DIRECTION INPUT ;
    USE SIGNAL ;
    PORT
      LAYER M5 ;
        RECT  29.712 0 29.736 0.084 ;
    END
  END tw_d[43]
  PIN tw_d[440]
    DIRECTION INPUT ;
    USE SIGNAL ;
    PORT
      LAYER M5 ;
        RECT  222.96 0 222.984 0.084 ;
    END
  END tw_d[440]
  PIN tw_d[441]
    DIRECTION INPUT ;
    USE SIGNAL ;
    PORT
      LAYER M5 ;
        RECT  223.056 0 223.08 0.084 ;
    END
  END tw_d[441]
  PIN tw_d[442]
    DIRECTION INPUT ;
    USE SIGNAL ;
    PORT
      LAYER M5 ;
        RECT  223.152 0 223.176 0.084 ;
    END
  END tw_d[442]
  PIN tw_d[443]
    DIRECTION INPUT ;
    USE SIGNAL ;
    PORT
      LAYER M5 ;
        RECT  223.248 0 223.272 0.084 ;
    END
  END tw_d[443]
  PIN tw_d[444]
    DIRECTION INPUT ;
    USE SIGNAL ;
    PORT
      LAYER M5 ;
        RECT  223.344 0 223.368 0.084 ;
    END
  END tw_d[444]
  PIN tw_d[445]
    DIRECTION INPUT ;
    USE SIGNAL ;
    PORT
      LAYER M5 ;
        RECT  223.44 0 223.464 0.084 ;
    END
  END tw_d[445]
  PIN tw_d[446]
    DIRECTION INPUT ;
    USE SIGNAL ;
    PORT
      LAYER M5 ;
        RECT  223.536 0 223.56 0.084 ;
    END
  END tw_d[446]
  PIN tw_d[447]
    DIRECTION INPUT ;
    USE SIGNAL ;
    PORT
      LAYER M5 ;
        RECT  223.632 0 223.656 0.084 ;
    END
  END tw_d[447]
  PIN tw_d[448]
    DIRECTION INPUT ;
    USE SIGNAL ;
    PORT
      LAYER M5 ;
        RECT  223.728 0 223.752 0.084 ;
    END
  END tw_d[448]
  PIN tw_d[449]
    DIRECTION INPUT ;
    USE SIGNAL ;
    PORT
      LAYER M5 ;
        RECT  223.824 0 223.848 0.084 ;
    END
  END tw_d[449]
  PIN tw_d[44]
    DIRECTION INPUT ;
    USE SIGNAL ;
    PORT
      LAYER M5 ;
        RECT  29.808 0 29.832 0.084 ;
    END
  END tw_d[44]
  PIN tw_d[450]
    DIRECTION INPUT ;
    USE SIGNAL ;
    PORT
      LAYER M5 ;
        RECT  223.92 0 223.944 0.084 ;
    END
  END tw_d[450]
  PIN tw_d[451]
    DIRECTION INPUT ;
    USE SIGNAL ;
    PORT
      LAYER M5 ;
        RECT  224.016 0 224.04 0.084 ;
    END
  END tw_d[451]
  PIN tw_d[452]
    DIRECTION INPUT ;
    USE SIGNAL ;
    PORT
      LAYER M5 ;
        RECT  224.112 0 224.136 0.084 ;
    END
  END tw_d[452]
  PIN tw_d[453]
    DIRECTION INPUT ;
    USE SIGNAL ;
    PORT
      LAYER M5 ;
        RECT  231.12 0 231.144 0.084 ;
    END
  END tw_d[453]
  PIN tw_d[454]
    DIRECTION INPUT ;
    USE SIGNAL ;
    PORT
      LAYER M5 ;
        RECT  231.216 0 231.24 0.084 ;
    END
  END tw_d[454]
  PIN tw_d[455]
    DIRECTION INPUT ;
    USE SIGNAL ;
    PORT
      LAYER M5 ;
        RECT  231.312 0 231.336 0.084 ;
    END
  END tw_d[455]
  PIN tw_d[456]
    DIRECTION INPUT ;
    USE SIGNAL ;
    PORT
      LAYER M5 ;
        RECT  231.408 0 231.432 0.084 ;
    END
  END tw_d[456]
  PIN tw_d[457]
    DIRECTION INPUT ;
    USE SIGNAL ;
    PORT
      LAYER M5 ;
        RECT  231.504 0 231.528 0.084 ;
    END
  END tw_d[457]
  PIN tw_d[458]
    DIRECTION INPUT ;
    USE SIGNAL ;
    PORT
      LAYER M5 ;
        RECT  231.6 0 231.624 0.084 ;
    END
  END tw_d[458]
  PIN tw_d[459]
    DIRECTION INPUT ;
    USE SIGNAL ;
    PORT
      LAYER M5 ;
        RECT  231.696 0 231.72 0.084 ;
    END
  END tw_d[459]
  PIN tw_d[45]
    DIRECTION INPUT ;
    USE SIGNAL ;
    PORT
      LAYER M5 ;
        RECT  29.904 0 29.928 0.084 ;
    END
  END tw_d[45]
  PIN tw_d[460]
    DIRECTION INPUT ;
    USE SIGNAL ;
    PORT
      LAYER M5 ;
        RECT  231.792 0 231.816 0.084 ;
    END
  END tw_d[460]
  PIN tw_d[461]
    DIRECTION INPUT ;
    USE SIGNAL ;
    PORT
      LAYER M5 ;
        RECT  231.888 0 231.912 0.084 ;
    END
  END tw_d[461]
  PIN tw_d[462]
    DIRECTION INPUT ;
    USE SIGNAL ;
    PORT
      LAYER M5 ;
        RECT  231.984 0 232.008 0.084 ;
    END
  END tw_d[462]
  PIN tw_d[463]
    DIRECTION INPUT ;
    USE SIGNAL ;
    PORT
      LAYER M5 ;
        RECT  232.08 0 232.104 0.084 ;
    END
  END tw_d[463]
  PIN tw_d[464]
    DIRECTION INPUT ;
    USE SIGNAL ;
    PORT
      LAYER M5 ;
        RECT  232.176 0 232.2 0.084 ;
    END
  END tw_d[464]
  PIN tw_d[465]
    DIRECTION INPUT ;
    USE SIGNAL ;
    PORT
      LAYER M5 ;
        RECT  232.272 0 232.296 0.084 ;
    END
  END tw_d[465]
  PIN tw_d[466]
    DIRECTION INPUT ;
    USE SIGNAL ;
    PORT
      LAYER M5 ;
        RECT  232.368 0 232.392 0.084 ;
    END
  END tw_d[466]
  PIN tw_d[467]
    DIRECTION INPUT ;
    USE SIGNAL ;
    PORT
      LAYER M5 ;
        RECT  232.464 0 232.488 0.084 ;
    END
  END tw_d[467]
  PIN tw_d[468]
    DIRECTION INPUT ;
    USE SIGNAL ;
    PORT
      LAYER M5 ;
        RECT  232.56 0 232.584 0.084 ;
    END
  END tw_d[468]
  PIN tw_d[469]
    DIRECTION INPUT ;
    USE SIGNAL ;
    PORT
      LAYER M5 ;
        RECT  232.656 0 232.68 0.084 ;
    END
  END tw_d[469]
  PIN tw_d[46]
    DIRECTION INPUT ;
    USE SIGNAL ;
    PORT
      LAYER M5 ;
        RECT  30 0 30.024 0.084 ;
    END
  END tw_d[46]
  PIN tw_d[470]
    DIRECTION INPUT ;
    USE SIGNAL ;
    PORT
      LAYER M5 ;
        RECT  232.752 0 232.776 0.084 ;
    END
  END tw_d[470]
  PIN tw_d[471]
    DIRECTION INPUT ;
    USE SIGNAL ;
    PORT
      LAYER M5 ;
        RECT  232.848 0 232.872 0.084 ;
    END
  END tw_d[471]
  PIN tw_d[472]
    DIRECTION INPUT ;
    USE SIGNAL ;
    PORT
      LAYER M5 ;
        RECT  232.944 0 232.968 0.084 ;
    END
  END tw_d[472]
  PIN tw_d[473]
    DIRECTION INPUT ;
    USE SIGNAL ;
    PORT
      LAYER M5 ;
        RECT  233.04 0 233.064 0.084 ;
    END
  END tw_d[473]
  PIN tw_d[474]
    DIRECTION INPUT ;
    USE SIGNAL ;
    PORT
      LAYER M5 ;
        RECT  233.136 0 233.16 0.084 ;
    END
  END tw_d[474]
  PIN tw_d[475]
    DIRECTION INPUT ;
    USE SIGNAL ;
    PORT
      LAYER M5 ;
        RECT  233.232 0 233.256 0.084 ;
    END
  END tw_d[475]
  PIN tw_d[476]
    DIRECTION INPUT ;
    USE SIGNAL ;
    PORT
      LAYER M5 ;
        RECT  233.328 0 233.352 0.084 ;
    END
  END tw_d[476]
  PIN tw_d[477]
    DIRECTION INPUT ;
    USE SIGNAL ;
    PORT
      LAYER M5 ;
        RECT  233.424 0 233.448 0.084 ;
    END
  END tw_d[477]
  PIN tw_d[478]
    DIRECTION INPUT ;
    USE SIGNAL ;
    PORT
      LAYER M5 ;
        RECT  233.52 0 233.544 0.084 ;
    END
  END tw_d[478]
  PIN tw_d[479]
    DIRECTION INPUT ;
    USE SIGNAL ;
    PORT
      LAYER M5 ;
        RECT  233.616 0 233.64 0.084 ;
    END
  END tw_d[479]
  PIN tw_d[47]
    DIRECTION INPUT ;
    USE SIGNAL ;
    PORT
      LAYER M5 ;
        RECT  30.096 0 30.12 0.084 ;
    END
  END tw_d[47]
  PIN tw_d[480]
    DIRECTION INPUT ;
    USE SIGNAL ;
    PORT
      LAYER M5 ;
        RECT  233.712 0 233.736 0.084 ;
    END
  END tw_d[480]
  PIN tw_d[481]
    DIRECTION INPUT ;
    USE SIGNAL ;
    PORT
      LAYER M5 ;
        RECT  233.808 0 233.832 0.084 ;
    END
  END tw_d[481]
  PIN tw_d[482]
    DIRECTION INPUT ;
    USE SIGNAL ;
    PORT
      LAYER M5 ;
        RECT  233.904 0 233.928 0.084 ;
    END
  END tw_d[482]
  PIN tw_d[483]
    DIRECTION INPUT ;
    USE SIGNAL ;
    PORT
      LAYER M5 ;
        RECT  234 0 234.024 0.084 ;
    END
  END tw_d[483]
  PIN tw_d[484]
    DIRECTION INPUT ;
    USE SIGNAL ;
    PORT
      LAYER M5 ;
        RECT  234.096 0 234.12 0.084 ;
    END
  END tw_d[484]
  PIN tw_d[485]
    DIRECTION INPUT ;
    USE SIGNAL ;
    PORT
      LAYER M5 ;
        RECT  207.12 0 207.144 0.084 ;
    END
  END tw_d[485]
  PIN tw_d[486]
    DIRECTION INPUT ;
    USE SIGNAL ;
    PORT
      LAYER M5 ;
        RECT  207.216 0 207.24 0.084 ;
    END
  END tw_d[486]
  PIN tw_d[487]
    DIRECTION INPUT ;
    USE SIGNAL ;
    PORT
      LAYER M5 ;
        RECT  207.312 0 207.336 0.084 ;
    END
  END tw_d[487]
  PIN tw_d[488]
    DIRECTION INPUT ;
    USE SIGNAL ;
    PORT
      LAYER M5 ;
        RECT  207.408 0 207.432 0.084 ;
    END
  END tw_d[488]
  PIN tw_d[489]
    DIRECTION INPUT ;
    USE SIGNAL ;
    PORT
      LAYER M5 ;
        RECT  207.504 0 207.528 0.084 ;
    END
  END tw_d[489]
  PIN tw_d[48]
    DIRECTION INPUT ;
    USE SIGNAL ;
    PORT
      LAYER M5 ;
        RECT  30.192 0 30.216 0.084 ;
    END
  END tw_d[48]
  PIN tw_d[490]
    DIRECTION INPUT ;
    USE SIGNAL ;
    PORT
      LAYER M5 ;
        RECT  207.6 0 207.624 0.084 ;
    END
  END tw_d[490]
  PIN tw_d[491]
    DIRECTION INPUT ;
    USE SIGNAL ;
    PORT
      LAYER M5 ;
        RECT  207.696 0 207.72 0.084 ;
    END
  END tw_d[491]
  PIN tw_d[492]
    DIRECTION INPUT ;
    USE SIGNAL ;
    PORT
      LAYER M5 ;
        RECT  207.792 0 207.816 0.084 ;
    END
  END tw_d[492]
  PIN tw_d[493]
    DIRECTION INPUT ;
    USE SIGNAL ;
    PORT
      LAYER M5 ;
        RECT  207.888 0 207.912 0.084 ;
    END
  END tw_d[493]
  PIN tw_d[494]
    DIRECTION INPUT ;
    USE SIGNAL ;
    PORT
      LAYER M5 ;
        RECT  207.984 0 208.008 0.084 ;
    END
  END tw_d[494]
  PIN tw_d[495]
    DIRECTION INPUT ;
    USE SIGNAL ;
    PORT
      LAYER M5 ;
        RECT  208.08 0 208.104 0.084 ;
    END
  END tw_d[495]
  PIN tw_d[496]
    DIRECTION INPUT ;
    USE SIGNAL ;
    PORT
      LAYER M5 ;
        RECT  208.176 0 208.2 0.084 ;
    END
  END tw_d[496]
  PIN tw_d[497]
    DIRECTION INPUT ;
    USE SIGNAL ;
    PORT
      LAYER M5 ;
        RECT  208.272 0 208.296 0.084 ;
    END
  END tw_d[497]
  PIN tw_d[498]
    DIRECTION INPUT ;
    USE SIGNAL ;
    PORT
      LAYER M5 ;
        RECT  208.368 0 208.392 0.084 ;
    END
  END tw_d[498]
  PIN tw_d[499]
    DIRECTION INPUT ;
    USE SIGNAL ;
    PORT
      LAYER M5 ;
        RECT  208.464 0 208.488 0.084 ;
    END
  END tw_d[499]
  PIN tw_d[49]
    DIRECTION INPUT ;
    USE SIGNAL ;
    PORT
      LAYER M5 ;
        RECT  30.288 0 30.312 0.084 ;
    END
  END tw_d[49]
  PIN tw_d[4]
    DIRECTION INPUT ;
    USE SIGNAL ;
    PORT
      LAYER M5 ;
        RECT  22.896 0 22.92 0.084 ;
    END
  END tw_d[4]
  PIN tw_d[500]
    DIRECTION INPUT ;
    USE SIGNAL ;
    PORT
      LAYER M5 ;
        RECT  208.56 0 208.584 0.084 ;
    END
  END tw_d[500]
  PIN tw_d[501]
    DIRECTION INPUT ;
    USE SIGNAL ;
    PORT
      LAYER M5 ;
        RECT  208.656 0 208.68 0.084 ;
    END
  END tw_d[501]
  PIN tw_d[502]
    DIRECTION INPUT ;
    USE SIGNAL ;
    PORT
      LAYER M5 ;
        RECT  208.752 0 208.776 0.084 ;
    END
  END tw_d[502]
  PIN tw_d[503]
    DIRECTION INPUT ;
    USE SIGNAL ;
    PORT
      LAYER M5 ;
        RECT  208.848 0 208.872 0.084 ;
    END
  END tw_d[503]
  PIN tw_d[504]
    DIRECTION INPUT ;
    USE SIGNAL ;
    PORT
      LAYER M5 ;
        RECT  208.944 0 208.968 0.084 ;
    END
  END tw_d[504]
  PIN tw_d[505]
    DIRECTION INPUT ;
    USE SIGNAL ;
    PORT
      LAYER M5 ;
        RECT  209.04 0 209.064 0.084 ;
    END
  END tw_d[505]
  PIN tw_d[506]
    DIRECTION INPUT ;
    USE SIGNAL ;
    PORT
      LAYER M5 ;
        RECT  209.136 0 209.16 0.084 ;
    END
  END tw_d[506]
  PIN tw_d[507]
    DIRECTION INPUT ;
    USE SIGNAL ;
    PORT
      LAYER M5 ;
        RECT  209.232 0 209.256 0.084 ;
    END
  END tw_d[507]
  PIN tw_d[508]
    DIRECTION INPUT ;
    USE SIGNAL ;
    PORT
      LAYER M5 ;
        RECT  209.328 0 209.352 0.084 ;
    END
  END tw_d[508]
  PIN tw_d[509]
    DIRECTION INPUT ;
    USE SIGNAL ;
    PORT
      LAYER M5 ;
        RECT  209.424 0 209.448 0.084 ;
    END
  END tw_d[509]
  PIN tw_d[50]
    DIRECTION INPUT ;
    USE SIGNAL ;
    PORT
      LAYER M5 ;
        RECT  30.384 0 30.408 0.084 ;
    END
  END tw_d[50]
  PIN tw_d[510]
    DIRECTION INPUT ;
    USE SIGNAL ;
    PORT
      LAYER M5 ;
        RECT  209.52 0 209.544 0.084 ;
    END
  END tw_d[510]
  PIN tw_d[511]
    DIRECTION INPUT ;
    USE SIGNAL ;
    PORT
      LAYER M5 ;
        RECT  209.616 0 209.64 0.084 ;
    END
  END tw_d[511]
  PIN tw_d[51]
    DIRECTION INPUT ;
    USE SIGNAL ;
    PORT
      LAYER M5 ;
        RECT  30.48 0 30.504 0.084 ;
    END
  END tw_d[51]
  PIN tw_d[52]
    DIRECTION INPUT ;
    USE SIGNAL ;
    PORT
      LAYER M5 ;
        RECT  30.576 0 30.6 0.084 ;
    END
  END tw_d[52]
  PIN tw_d[53]
    DIRECTION INPUT ;
    USE SIGNAL ;
    PORT
      LAYER M5 ;
        RECT  30.672 0 30.696 0.084 ;
    END
  END tw_d[53]
  PIN tw_d[54]
    DIRECTION INPUT ;
    USE SIGNAL ;
    PORT
      LAYER M5 ;
        RECT  30.768 0 30.792 0.084 ;
    END
  END tw_d[54]
  PIN tw_d[55]
    DIRECTION INPUT ;
    USE SIGNAL ;
    PORT
      LAYER M5 ;
        RECT  30.864 0 30.888 0.084 ;
    END
  END tw_d[55]
  PIN tw_d[56]
    DIRECTION INPUT ;
    USE SIGNAL ;
    PORT
      LAYER M5 ;
        RECT  30.96 0 30.984 0.084 ;
    END
  END tw_d[56]
  PIN tw_d[57]
    DIRECTION INPUT ;
    USE SIGNAL ;
    PORT
      LAYER M5 ;
        RECT  31.056 0 31.08 0.084 ;
    END
  END tw_d[57]
  PIN tw_d[58]
    DIRECTION INPUT ;
    USE SIGNAL ;
    PORT
      LAYER M5 ;
        RECT  31.152 0 31.176 0.084 ;
    END
  END tw_d[58]
  PIN tw_d[59]
    DIRECTION INPUT ;
    USE SIGNAL ;
    PORT
      LAYER M5 ;
        RECT  31.248 0 31.272 0.084 ;
    END
  END tw_d[59]
  PIN tw_d[5]
    DIRECTION INPUT ;
    USE SIGNAL ;
    PORT
      LAYER M5 ;
        RECT  22.992 0 23.016 0.084 ;
    END
  END tw_d[5]
  PIN tw_d[60]
    DIRECTION INPUT ;
    USE SIGNAL ;
    PORT
      LAYER M5 ;
        RECT  31.344 0 31.368 0.084 ;
    END
  END tw_d[60]
  PIN tw_d[61]
    DIRECTION INPUT ;
    USE SIGNAL ;
    PORT
      LAYER M5 ;
        RECT  31.44 0 31.464 0.084 ;
    END
  END tw_d[61]
  PIN tw_d[62]
    DIRECTION INPUT ;
    USE SIGNAL ;
    PORT
      LAYER M5 ;
        RECT  31.536 0 31.56 0.084 ;
    END
  END tw_d[62]
  PIN tw_d[63]
    DIRECTION INPUT ;
    USE SIGNAL ;
    PORT
      LAYER M5 ;
        RECT  31.632 0 31.656 0.084 ;
    END
  END tw_d[63]
  PIN tw_d[64]
    DIRECTION INPUT ;
    USE SIGNAL ;
    PORT
      LAYER M5 ;
        RECT  31.728 0 31.752 0.084 ;
    END
  END tw_d[64]
  PIN tw_d[65]
    DIRECTION INPUT ;
    USE SIGNAL ;
    PORT
      LAYER M5 ;
        RECT  31.824 0 31.848 0.084 ;
    END
  END tw_d[65]
  PIN tw_d[66]
    DIRECTION INPUT ;
    USE SIGNAL ;
    PORT
      LAYER M5 ;
        RECT  31.92 0 31.944 0.084 ;
    END
  END tw_d[66]
  PIN tw_d[67]
    DIRECTION INPUT ;
    USE SIGNAL ;
    PORT
      LAYER M5 ;
        RECT  32.016 0 32.04 0.084 ;
    END
  END tw_d[67]
  PIN tw_d[68]
    DIRECTION INPUT ;
    USE SIGNAL ;
    PORT
      LAYER M5 ;
        RECT  32.112 0 32.136 0.084 ;
    END
  END tw_d[68]
  PIN tw_d[69]
    DIRECTION INPUT ;
    USE SIGNAL ;
    PORT
      LAYER M5 ;
        RECT  26.064 0 26.088 0.084 ;
    END
  END tw_d[69]
  PIN tw_d[6]
    DIRECTION INPUT ;
    USE SIGNAL ;
    PORT
      LAYER M5 ;
        RECT  23.088 0 23.112 0.084 ;
    END
  END tw_d[6]
  PIN tw_d[70]
    DIRECTION INPUT ;
    USE SIGNAL ;
    PORT
      LAYER M5 ;
        RECT  26.16 0 26.184 0.084 ;
    END
  END tw_d[70]
  PIN tw_d[71]
    DIRECTION INPUT ;
    USE SIGNAL ;
    PORT
      LAYER M5 ;
        RECT  26.256 0 26.28 0.084 ;
    END
  END tw_d[71]
  PIN tw_d[72]
    DIRECTION INPUT ;
    USE SIGNAL ;
    PORT
      LAYER M5 ;
        RECT  26.352 0 26.376 0.084 ;
    END
  END tw_d[72]
  PIN tw_d[73]
    DIRECTION INPUT ;
    USE SIGNAL ;
    PORT
      LAYER M5 ;
        RECT  26.448 0 26.472 0.084 ;
    END
  END tw_d[73]
  PIN tw_d[74]
    DIRECTION INPUT ;
    USE SIGNAL ;
    PORT
      LAYER M5 ;
        RECT  26.544 0 26.568 0.084 ;
    END
  END tw_d[74]
  PIN tw_d[75]
    DIRECTION INPUT ;
    USE SIGNAL ;
    PORT
      LAYER M5 ;
        RECT  26.64 0 26.664 0.084 ;
    END
  END tw_d[75]
  PIN tw_d[76]
    DIRECTION INPUT ;
    USE SIGNAL ;
    PORT
      LAYER M5 ;
        RECT  26.736 0 26.76 0.084 ;
    END
  END tw_d[76]
  PIN tw_d[77]
    DIRECTION INPUT ;
    USE SIGNAL ;
    PORT
      LAYER M5 ;
        RECT  26.832 0 26.856 0.084 ;
    END
  END tw_d[77]
  PIN tw_d[78]
    DIRECTION INPUT ;
    USE SIGNAL ;
    PORT
      LAYER M5 ;
        RECT  26.928 0 26.952 0.084 ;
    END
  END tw_d[78]
  PIN tw_d[79]
    DIRECTION INPUT ;
    USE SIGNAL ;
    PORT
      LAYER M5 ;
        RECT  27.024 0 27.048 0.084 ;
    END
  END tw_d[79]
  PIN tw_d[7]
    DIRECTION INPUT ;
    USE SIGNAL ;
    PORT
      LAYER M5 ;
        RECT  23.184 0 23.208 0.084 ;
    END
  END tw_d[7]
  PIN tw_d[80]
    DIRECTION INPUT ;
    USE SIGNAL ;
    PORT
      LAYER M5 ;
        RECT  27.12 0 27.144 0.084 ;
    END
  END tw_d[80]
  PIN tw_d[81]
    DIRECTION INPUT ;
    USE SIGNAL ;
    PORT
      LAYER M5 ;
        RECT  27.216 0 27.24 0.084 ;
    END
  END tw_d[81]
  PIN tw_d[82]
    DIRECTION INPUT ;
    USE SIGNAL ;
    PORT
      LAYER M5 ;
        RECT  27.312 0 27.336 0.084 ;
    END
  END tw_d[82]
  PIN tw_d[83]
    DIRECTION INPUT ;
    USE SIGNAL ;
    PORT
      LAYER M5 ;
        RECT  27.408 0 27.432 0.084 ;
    END
  END tw_d[83]
  PIN tw_d[84]
    DIRECTION INPUT ;
    USE SIGNAL ;
    PORT
      LAYER M5 ;
        RECT  27.504 0 27.528 0.084 ;
    END
  END tw_d[84]
  PIN tw_d[85]
    DIRECTION INPUT ;
    USE SIGNAL ;
    PORT
      LAYER M5 ;
        RECT  27.6 0 27.624 0.084 ;
    END
  END tw_d[85]
  PIN tw_d[86]
    DIRECTION INPUT ;
    USE SIGNAL ;
    PORT
      LAYER M5 ;
        RECT  27.696 0 27.72 0.084 ;
    END
  END tw_d[86]
  PIN tw_d[87]
    DIRECTION INPUT ;
    USE SIGNAL ;
    PORT
      LAYER M5 ;
        RECT  27.792 0 27.816 0.084 ;
    END
  END tw_d[87]
  PIN tw_d[88]
    DIRECTION INPUT ;
    USE SIGNAL ;
    PORT
      LAYER M5 ;
        RECT  27.888 0 27.912 0.084 ;
    END
  END tw_d[88]
  PIN tw_d[89]
    DIRECTION INPUT ;
    USE SIGNAL ;
    PORT
      LAYER M5 ;
        RECT  27.984 0 28.008 0.084 ;
    END
  END tw_d[89]
  PIN tw_d[8]
    DIRECTION INPUT ;
    USE SIGNAL ;
    PORT
      LAYER M5 ;
        RECT  23.28 0 23.304 0.084 ;
    END
  END tw_d[8]
  PIN tw_d[90]
    DIRECTION INPUT ;
    USE SIGNAL ;
    PORT
      LAYER M5 ;
        RECT  28.08 0 28.104 0.084 ;
    END
  END tw_d[90]
  PIN tw_d[91]
    DIRECTION INPUT ;
    USE SIGNAL ;
    PORT
      LAYER M5 ;
        RECT  28.176 0 28.2 0.084 ;
    END
  END tw_d[91]
  PIN tw_d[92]
    DIRECTION INPUT ;
    USE SIGNAL ;
    PORT
      LAYER M5 ;
        RECT  28.272 0 28.296 0.084 ;
    END
  END tw_d[92]
  PIN tw_d[93]
    DIRECTION INPUT ;
    USE SIGNAL ;
    PORT
      LAYER M5 ;
        RECT  28.368 0 28.392 0.084 ;
    END
  END tw_d[93]
  PIN tw_d[94]
    DIRECTION INPUT ;
    USE SIGNAL ;
    PORT
      LAYER M5 ;
        RECT  28.464 0 28.488 0.084 ;
    END
  END tw_d[94]
  PIN tw_d[95]
    DIRECTION INPUT ;
    USE SIGNAL ;
    PORT
      LAYER M5 ;
        RECT  28.56 0 28.584 0.084 ;
    END
  END tw_d[95]
  PIN tw_d[96]
    DIRECTION INPUT ;
    USE SIGNAL ;
    PORT
      LAYER M5 ;
        RECT  28.656 0 28.68 0.084 ;
    END
  END tw_d[96]
  PIN tw_d[97]
    DIRECTION INPUT ;
    USE SIGNAL ;
    PORT
      LAYER M5 ;
        RECT  28.752 0 28.776 0.084 ;
    END
  END tw_d[97]
  PIN tw_d[98]
    DIRECTION INPUT ;
    USE SIGNAL ;
    PORT
      LAYER M5 ;
        RECT  28.848 0 28.872 0.084 ;
    END
  END tw_d[98]
  PIN tw_d[99]
    DIRECTION INPUT ;
    USE SIGNAL ;
    PORT
      LAYER M5 ;
        RECT  28.944 0 28.968 0.084 ;
    END
  END tw_d[99]
  PIN tw_d[9]
    DIRECTION INPUT ;
    USE SIGNAL ;
    PORT
      LAYER M5 ;
        RECT  23.376 0 23.4 0.084 ;
    END
  END tw_d[9]
  PIN tw_kind[0]
    DIRECTION INPUT ;
    USE SIGNAL ;
    PORT
      LAYER M5 ;
        RECT  209.712 0 209.736 0.084 ;
    END
  END tw_kind[0]
  PIN tw_kind[1]
    DIRECTION INPUT ;
    USE SIGNAL ;
    PORT
      LAYER M5 ;
        RECT  209.808 0 209.832 0.084 ;
    END
  END tw_kind[1]
  PIN tw_we
    DIRECTION INPUT ;
    USE SIGNAL ;
    PORT
      LAYER M5 ;
        RECT  209.904 0 209.928 0.084 ;
    END
  END tw_we
  PIN VDD
    DIRECTION INOUT ;
    USE POWER ;
    PORT
      LAYER M5 ;
        RECT  244.116 4.311 244.236 211.689 ;
        RECT  239.796 4.311 239.916 211.689 ;
        RECT  235.476 4.311 235.596 211.689 ;
        RECT  231.156 4.311 231.276 211.689 ;
        RECT  226.836 4.311 226.956 211.689 ;
        RECT  222.516 4.311 222.636 211.689 ;
        RECT  218.196 4.311 218.316 211.689 ;
        RECT  213.876 4.311 213.996 211.689 ;
        RECT  209.556 4.311 209.676 211.689 ;
        RECT  205.236 4.311 205.356 211.689 ;
        RECT  200.916 4.311 201.036 211.689 ;
        RECT  196.596 4.311 196.716 211.689 ;
        RECT  192.276 4.311 192.396 211.689 ;
        RECT  187.956 4.311 188.076 211.689 ;
        RECT  183.636 4.311 183.756 211.689 ;
        RECT  179.316 4.311 179.436 211.689 ;
        RECT  174.996 181.4 175.116 211.689 ;
        RECT  174.996 4.311 175.116 36.784 ;
        RECT  170.676 181.4 170.796 211.689 ;
        RECT  170.676 4.311 170.796 36.784 ;
        RECT  166.356 181.4 166.476 211.689 ;
        RECT  166.356 4.311 166.476 36.784 ;
        RECT  162.036 181.4 162.156 211.689 ;
        RECT  162.036 4.311 162.156 36.784 ;
        RECT  157.716 181.4 157.836 211.689 ;
        RECT  157.716 4.311 157.836 36.784 ;
        RECT  153.396 181.4 153.516 211.689 ;
        RECT  153.396 4.311 153.516 36.784 ;
        RECT  149.076 181.4 149.196 211.689 ;
        RECT  149.076 4.311 149.196 36.784 ;
        RECT  144.756 181.4 144.876 211.689 ;
        RECT  144.756 4.311 144.876 36.784 ;
        RECT  140.436 181.4 140.556 211.689 ;
        RECT  140.436 4.311 140.556 36.784 ;
        RECT  136.116 4.311 136.236 211.689 ;
        RECT  131.796 4.311 131.916 211.689 ;
        RECT  127.476 4.311 127.596 211.689 ;
        RECT  123.156 4.311 123.276 211.689 ;
        RECT  118.836 4.311 118.956 211.689 ;
        RECT  114.516 4.311 114.636 211.689 ;
        RECT  110.196 181.4 110.316 211.689 ;
        RECT  110.196 4.311 110.316 36.784 ;
        RECT  105.876 181.4 105.996 211.689 ;
        RECT  105.876 4.311 105.996 36.784 ;
        RECT  101.556 181.4 101.676 211.689 ;
        RECT  101.556 4.311 101.676 36.784 ;
        RECT  97.236 181.4 97.356 211.689 ;
        RECT  97.236 4.311 97.356 36.784 ;
        RECT  92.916 181.4 93.036 211.689 ;
        RECT  92.916 4.311 93.036 36.784 ;
        RECT  88.596 181.4 88.716 211.689 ;
        RECT  88.596 4.311 88.716 36.784 ;
        RECT  84.276 181.4 84.396 211.689 ;
        RECT  84.276 4.311 84.396 36.784 ;
        RECT  79.956 181.4 80.076 211.689 ;
        RECT  79.956 4.311 80.076 36.784 ;
        RECT  75.636 181.4 75.756 211.689 ;
        RECT  75.636 4.311 75.756 36.784 ;
        RECT  71.316 4.311 71.436 211.689 ;
        RECT  66.996 4.311 67.116 211.689 ;
        RECT  62.676 4.311 62.796 211.689 ;
        RECT  58.356 4.311 58.476 211.689 ;
        RECT  54.036 4.311 54.156 211.689 ;
        RECT  49.716 4.311 49.836 211.689 ;
        RECT  45.396 4.311 45.516 211.689 ;
        RECT  41.076 4.311 41.196 211.689 ;
        RECT  36.756 4.311 36.876 211.689 ;
        RECT  32.436 4.311 32.556 211.689 ;
        RECT  28.116 4.311 28.236 211.689 ;
        RECT  23.796 4.311 23.916 211.689 ;
        RECT  19.476 4.311 19.596 211.689 ;
        RECT  15.156 4.311 15.276 211.689 ;
        RECT  10.836 4.311 10.956 211.689 ;
        RECT  6.516 4.311 6.636 211.689 ;
    END
  END VDD
  PIN VSS
    DIRECTION INOUT ;
    USE GROUND ;
    PORT
      LAYER M5 ;
        RECT  243.924 4.297 244.044 211.703 ;
        RECT  239.604 4.297 239.724 211.703 ;
        RECT  235.284 4.297 235.404 211.703 ;
        RECT  230.964 4.297 231.084 211.703 ;
        RECT  226.644 4.297 226.764 211.703 ;
        RECT  222.324 4.297 222.444 211.703 ;
        RECT  218.004 4.297 218.124 211.703 ;
        RECT  213.684 4.297 213.804 211.703 ;
        RECT  209.364 4.297 209.484 211.703 ;
        RECT  205.044 4.297 205.164 211.703 ;
        RECT  200.724 4.297 200.844 211.703 ;
        RECT  196.404 4.297 196.524 211.703 ;
        RECT  192.084 4.297 192.204 211.703 ;
        RECT  187.764 4.297 187.884 211.703 ;
        RECT  183.444 4.297 183.564 211.703 ;
        RECT  179.124 4.297 179.244 211.703 ;
        RECT  174.804 181.4 174.924 211.703 ;
        RECT  174.804 4.297 174.924 36.784 ;
        RECT  170.484 181.4 170.604 211.703 ;
        RECT  170.484 4.297 170.604 36.784 ;
        RECT  166.164 181.4 166.284 211.703 ;
        RECT  166.164 4.297 166.284 36.784 ;
        RECT  161.844 181.4 161.964 211.703 ;
        RECT  161.844 4.297 161.964 36.784 ;
        RECT  157.524 181.4 157.644 211.703 ;
        RECT  157.524 4.297 157.644 36.784 ;
        RECT  153.204 181.4 153.324 211.703 ;
        RECT  153.204 4.297 153.324 36.784 ;
        RECT  148.884 181.4 149.004 211.703 ;
        RECT  148.884 4.297 149.004 36.784 ;
        RECT  144.564 181.4 144.684 211.703 ;
        RECT  144.564 4.297 144.684 36.784 ;
        RECT  140.244 181.4 140.364 211.703 ;
        RECT  140.244 4.297 140.364 36.784 ;
        RECT  135.924 4.297 136.044 211.703 ;
        RECT  131.604 4.297 131.724 211.703 ;
        RECT  127.284 4.297 127.404 211.703 ;
        RECT  122.964 4.297 123.084 211.703 ;
        RECT  118.644 4.297 118.764 211.703 ;
        RECT  114.324 4.297 114.444 211.703 ;
        RECT  110.004 181.4 110.124 211.703 ;
        RECT  110.004 4.297 110.124 36.784 ;
        RECT  105.684 181.4 105.804 211.703 ;
        RECT  105.684 4.297 105.804 36.784 ;
        RECT  101.364 181.4 101.484 211.703 ;
        RECT  101.364 4.297 101.484 36.784 ;
        RECT  97.044 181.4 97.164 211.703 ;
        RECT  97.044 4.297 97.164 36.784 ;
        RECT  92.724 181.4 92.844 211.703 ;
        RECT  92.724 4.297 92.844 36.784 ;
        RECT  88.404 181.4 88.524 211.703 ;
        RECT  88.404 4.297 88.524 36.784 ;
        RECT  84.084 181.4 84.204 211.703 ;
        RECT  84.084 4.297 84.204 36.784 ;
        RECT  79.764 181.4 79.884 211.703 ;
        RECT  79.764 4.297 79.884 36.784 ;
        RECT  75.444 181.4 75.564 211.703 ;
        RECT  75.444 4.297 75.564 36.784 ;
        RECT  71.124 4.297 71.244 211.703 ;
        RECT  66.804 4.297 66.924 211.703 ;
        RECT  62.484 4.297 62.604 211.703 ;
        RECT  58.164 4.297 58.284 211.703 ;
        RECT  53.844 4.297 53.964 211.703 ;
        RECT  49.524 4.297 49.644 211.703 ;
        RECT  45.204 4.297 45.324 211.703 ;
        RECT  40.884 4.297 41.004 211.703 ;
        RECT  36.564 4.297 36.684 211.703 ;
        RECT  32.244 4.297 32.364 211.703 ;
        RECT  27.924 4.297 28.044 211.703 ;
        RECT  23.604 4.297 23.724 211.703 ;
        RECT  19.284 4.297 19.404 211.703 ;
        RECT  14.964 4.297 15.084 211.703 ;
        RECT  10.644 4.297 10.764 211.703 ;
        RECT  6.324 4.297 6.444 211.703 ;
    END
  END VSS
  PIN ft_ck_i
    DIRECTION INPUT ;
    USE SIGNAL ;
    PORT
      LAYER M5 ;
        RECT  122.688 109.968 122.712 110.352 ;
    END
  END ft_ck_i
  PIN ft_ck_o
    DIRECTION OUTPUT ;
    USE SIGNAL ;
    PORT
      LAYER M5 ;
        RECT  127.872 109.968 127.896 110.352 ;
    END
  END ft_ck_o
  PIN ft_rst_i
    DIRECTION INPUT ;
    USE SIGNAL ;
    PORT
      LAYER M5 ;
        RECT  122.688 105.648 122.712 106.032 ;
    END
  END ft_rst_i
  PIN ft_rst_o
    DIRECTION OUTPUT ;
    USE SIGNAL ;
    PORT
      LAYER M5 ;
        RECT  127.872 105.648 127.896 106.032 ;
    END
  END ft_rst_o
  OBS
      LAYER RVTN ;
     RECT  0 0 246.24 211.703 ;
      LAYER RVTP ;
     RECT  0 0 246.24 211.703 ;
      LAYER M1 ;
     RECT  0 0 246.24 211.703 ;
      LAYER M2 ;
     RECT  0 0 246.24 211.703 ;
      LAYER M3 ;
     RECT  0 0 246.24 211.703 ;
      LAYER M4 ;
     RECT  0 0 246.24 211.703 ;
      LAYER M5 ;
     RECT  0 0 246.24 211.703 ;
      LAYER M6 ;
     RECT  6.133 193.536 7.907 193.568 ;
     RECT  6.181 200.576 7.907 200.608 ;
     RECT  5.077 195.264 9.205 195.296 ;
     RECT  7.381 197.824 9.251 197.856 ;
     RECT  8.485 185.536 9.349 185.568 ;
     RECT  7.381 157.824 9.395 157.856 ;
     RECT  9.205 195.264 9.395 196.064 ;
     RECT  9.349 185.28 10.261 185.568 ;
     RECT  10.261 184.192 10.307 185.568 ;
     RECT  6.997 180.416 10.547 180.448 ;
     RECT  10.213 165.824 11.123 165.856 ;
     RECT  9.637 172.736 11.123 172.768 ;
     RECT  7.909 193.664 11.653 193.696 ;
     RECT  10.307 185.536 11.699 185.568 ;
     RECT  10.307 184.192 15.443 184.224 ;
     RECT  11.653 193.664 16.453 194.464 ;
     RECT  16.453 193.472 16.595 194.464 ;
     RECT  18.949 7.936 20.243 7.968 ;
     RECT  20.197 11.648 22.165 11.68 ;
     RECT  7.957 190.912 23.363 190.944 ;
     RECT  22.165 11.648 26.197 11.936 ;
     RECT  26.197 11.648 26.243 12.768 ;
     RECT  26.243 11.904 29.123 12.768 ;
     RECT  29.123 11.904 30.709 11.936 ;
     RECT  30.709 11.328 30.755 11.936 ;
     RECT  30.755 11.328 33.013 11.36 ;
     RECT  33.013 11.328 36.133 12.256 ;
     RECT  36.133 10.752 36.179 12.256 ;
     RECT  36.179 10.752 37.667 11.36 ;
     RECT  37.667 10.752 39.349 10.784 ;
     RECT  39.349 10.56 39.395 10.784 ;
     RECT  9.395 196.032 40.405 196.064 ;
     RECT  40.405 196.032 40.451 196.384 ;
     RECT  39.395 10.56 42.803 10.592 ;
     RECT  40.451 196.352 45.683 196.384 ;
     RECT  44.005 186.368 60.373 186.4 ;
     RECT  60.373 185.28 60.611 186.4 ;
     RECT  16.595 193.472 67.237 193.696 ;
     RECT  67.237 193.024 67.283 193.696 ;
     RECT  72.901 32.448 73.189 32.48 ;
     RECT  57.541 18.496 73.235 18.528 ;
     RECT  67.283 193.024 74.053 193.504 ;
     RECT  60.611 185.28 77.509 185.504 ;
     RECT  30.085 25.472 77.555 25.504 ;
     RECT  77.509 185.28 78.707 186.016 ;
     RECT  78.707 185.28 79.283 185.888 ;
     RECT  74.053 192.832 80.243 193.504 ;
     RECT  79.283 185.856 81.683 185.888 ;
     RECT  81.637 187.2 82.597 187.232 ;
     RECT  82.597 187.2 87.155 188 ;
     RECT  87.155 187.2 89.893 187.232 ;
     RECT  89.893 186.88 89.939 187.232 ;
     RECT  80.243 192.832 90.613 193.248 ;
     RECT  89.939 186.88 93.155 186.912 ;
     RECT  90.613 192.832 93.539 193.44 ;
     RECT  93.539 192.832 93.733 193.12 ;
     RECT  81.445 198.784 93.779 198.816 ;
     RECT  96.421 185.792 101.221 185.824 ;
     RECT  73.189 31.872 105.445 32.48 ;
     RECT  93.733 192.704 107.221 193.12 ;
     RECT  101.221 185.536 107.603 185.824 ;
     RECT  105.445 31.68 108.323 32.48 ;
     RECT  78.037 25.408 111.541 25.44 ;
     RECT  108.323 32.448 111.877 32.48 ;
     RECT  111.877 31.872 111.923 32.48 ;
     RECT  106.453 183.936 112.883 183.968 ;
     RECT  107.603 185.792 115.861 185.824 ;
     RECT  123.637 109.12 124.837 109.152 ;
     RECT  111.541 25.152 124.883 25.44 ;
     RECT  120.373 152.896 124.883 152.928 ;
     RECT  107.221 192.512 124.883 193.12 ;
     RECT  124.933 151.296 125.123 151.328 ;
     RECT  124.693 144.384 125.603 144.416 ;
     RECT  124.837 108.928 127.715 109.152 ;
     RECT  127.715 109.12 127.763 109.152 ;
     RECT  115.861 185.6 131.123 185.824 ;
     RECT  131.123 185.792 135.781 185.824 ;
     RECT  135.781 185.792 135.827 186.4 ;
     RECT  111.923 31.872 136.403 31.904 ;
     RECT  127.045 33.536 136.643 33.568 ;
     RECT  136.741 30.592 143.939 30.624 ;
     RECT  135.827 186.368 144.421 186.4 ;
     RECT  144.421 186.368 144.467 187.232 ;
     RECT  143.893 32.448 147.683 32.48 ;
     RECT  144.467 187.2 147.731 187.232 ;
     RECT  151.573 185.28 156.517 185.312 ;
     RECT  156.517 185.28 157.957 185.568 ;
     RECT  157.957 185.28 158.003 186.656 ;
     RECT  158.003 185.536 160.787 186.656 ;
     RECT  126.661 198.784 163.043 198.816 ;
     RECT  160.787 185.536 163.763 185.568 ;
     RECT  164.677 188.8 168.757 188.832 ;
     RECT  168.757 188.8 168.803 189.088 ;
     RECT  163.717 187.456 169.331 187.488 ;
     RECT  125.365 25.472 171.635 25.504 ;
     RECT  168.803 189.056 171.635 189.088 ;
     RECT  171.589 185.792 174.707 185.824 ;
     RECT  193.813 9.984 204.323 10.016 ;
     RECT  169.237 7.616 210.325 7.648 ;
     RECT  210.325 7.616 210.371 7.904 ;
     RECT  204.277 12.224 215.125 12.256 ;
     RECT  210.371 7.872 215.171 7.904 ;
     RECT  215.125 11.904 218.483 12.256 ;
     RECT  172.117 24.192 220.019 24.224 ;
     RECT  221.701 8.96 224.579 8.992 ;
     RECT  218.483 12.224 226.355 12.256 ;
     RECT  225.109 9.536 231.971 9.568 ;
     RECT  231.925 7.296 233.171 7.328 ;
  END
END qfd_dv_s8_crh_rp1
END LIBRARY
